VERSION 5.7 ;
  NOWIREEXTENSIONATPIN ON ;
  DIVIDERCHAR "/" ;
  BUSBITCHARS "[]" ;
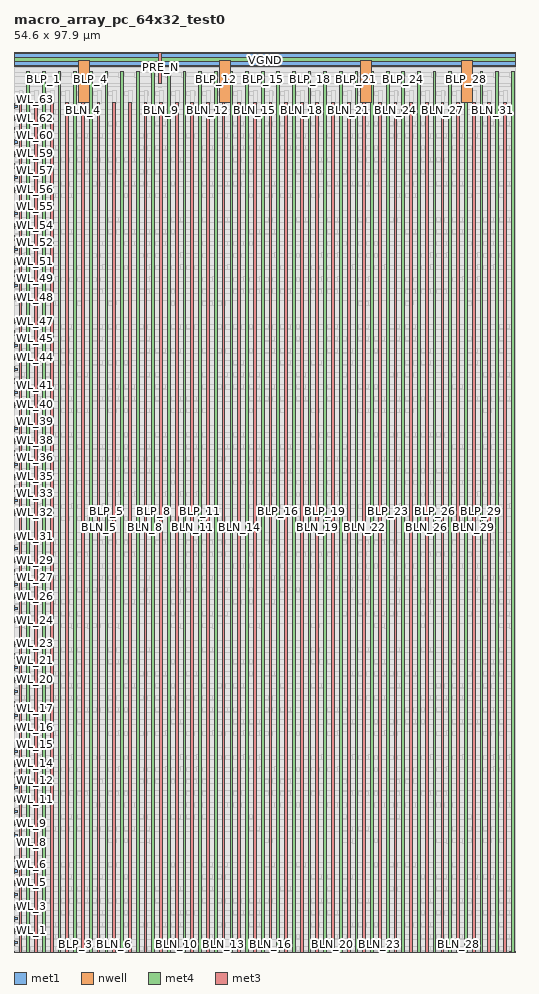
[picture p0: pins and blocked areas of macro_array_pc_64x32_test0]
MACRO macro_array_pc_64x32_test0
  CLASS BLOCK ;
  FOREIGN macro_array_pc_64x32_test0 ;
  ORIGIN 0.000 0.000 ;
  SIZE 54.600 BY 97.900 ;
  PIN VPWR
    USE POWER ;
    PORT
      LAYER met1 ;
        RECT 0.000 96.450 54.500 96.850 ;
    END
    PORT
      LAYER nwell ;
        RECT 7.050 92.400 8.250 96.980 ;
    END
    PORT
      LAYER nwell ;
        RECT 22.350 92.400 23.550 96.980 ;
    END
    PORT
      LAYER nwell ;
        RECT 37.650 92.400 38.850 96.980 ;
    END
    PORT
      LAYER nwell ;
        RECT 48.700 92.400 49.900 96.980 ;
    END
    PORT
      LAYER met4 ;
        RECT 0.000 96.350 54.500 97.650 ;
    END
  END VPWR
  PIN VGND
    USE GROUND ;
    PORT
      LAYER met1 ;
        RECT 0.000 97.300 54.500 97.700 ;
    END
  END VGND
  PIN PRE_N
    ANTENNAGATEAREA 9.599999 ;
    PORT
      LAYER met3 ;
        RECT 15.685 94.435 16.095 97.900 ;
    END
  END PRE_N
  PIN BLP_0
    ANTENNADIFFAREA 1.995200 ;
    PORT
      LAYER met4 ;
        RECT 1.400 0.000 1.700 95.800 ;
    END
  END BLP_0
  PIN BLN_0
    ANTENNADIFFAREA 3.456800 ;
    PORT
      LAYER met3 ;
        RECT 0.550 0.000 0.850 92.400 ;
    END
  END BLN_0
  PIN BLP_1
    ANTENNADIFFAREA 1.629800 ;
    PORT
      LAYER met4 ;
        RECT 3.100 0.000 3.400 95.800 ;
    END
  END BLP_1
  PIN BLN_1
    ANTENNADIFFAREA 2.969600 ;
    PORT
      LAYER met3 ;
        RECT 2.250 0.000 2.550 92.400 ;
    END
  END BLN_1
  PIN BLP_2
    ANTENNADIFFAREA 2.604200 ;
    PORT
      LAYER met4 ;
        RECT 4.800 0.000 5.100 95.800 ;
    END
  END BLP_2
  PIN BLN_2
    ANTENNADIFFAREA 1.995200 ;
    PORT
      LAYER met3 ;
        RECT 3.950 0.000 4.250 92.400 ;
    END
  END BLN_2
  PIN BLP_3
    ANTENNADIFFAREA 2.117000 ;
    PORT
      LAYER met4 ;
        RECT 6.500 0.000 6.800 95.800 ;
    END
  END BLP_3
  PIN BLN_3
    ANTENNADIFFAREA 2.726000 ;
    PORT
      LAYER met3 ;
        RECT 5.650 0.000 5.950 92.400 ;
    END
  END BLN_3
  PIN BLP_4
    ANTENNADIFFAREA 1.995200 ;
    PORT
      LAYER met4 ;
        RECT 8.200 0.000 8.500 95.800 ;
    END
  END BLP_4
  PIN BLN_4
    ANTENNADIFFAREA 2.969600 ;
    PORT
      LAYER met3 ;
        RECT 7.350 0.000 7.650 92.400 ;
    END
  END BLN_4
  PIN BLP_5
    ANTENNADIFFAREA 2.604200 ;
    PORT
      LAYER met4 ;
        RECT 9.900 0.000 10.200 95.800 ;
    END
  END BLP_5
  PIN BLN_5
    ANTENNADIFFAREA 1.873400 ;
    PORT
      LAYER met3 ;
        RECT 9.050 0.000 9.350 92.400 ;
    END
  END BLN_5
  PIN BLP_6
    ANTENNADIFFAREA 1.629800 ;
    PORT
      LAYER met4 ;
        RECT 11.600 0.000 11.900 95.800 ;
    END
  END BLP_6
  PIN BLN_6
    ANTENNADIFFAREA 2.360600 ;
    PORT
      LAYER met3 ;
        RECT 10.750 0.000 11.050 92.400 ;
    END
  END BLN_6
  PIN BLP_7
    ANTENNADIFFAREA 1.873400 ;
    PORT
      LAYER met4 ;
        RECT 13.300 0.000 13.600 95.800 ;
    END
  END BLP_7
  PIN BLN_7
    ANTENNADIFFAREA 2.726000 ;
    PORT
      LAYER met3 ;
        RECT 12.450 0.000 12.750 92.400 ;
    END
  END BLN_7
  PIN BLP_8
    ANTENNADIFFAREA 2.482400 ;
    PORT
      LAYER met4 ;
        RECT 15.000 0.000 15.300 95.800 ;
    END
  END BLP_8
  PIN BLN_8
    ANTENNADIFFAREA 2.360600 ;
    PORT
      LAYER met3 ;
        RECT 14.150 0.000 14.450 92.400 ;
    END
  END BLN_8
  PIN BLP_9
    ANTENNADIFFAREA 2.238800 ;
    PORT
      LAYER met4 ;
        RECT 16.700 0.000 17.000 95.800 ;
    END
  END BLP_9
  PIN BLN_9
    ANTENNADIFFAREA 1.751600 ;
    PORT
      LAYER met3 ;
        RECT 15.850 0.000 16.150 92.400 ;
    END
  END BLN_9
  PIN BLP_10
    ANTENNADIFFAREA 2.847800 ;
    PORT
      LAYER met4 ;
        RECT 18.400 0.000 18.700 95.800 ;
    END
  END BLP_10
  PIN BLN_10
    ANTENNADIFFAREA 2.117000 ;
    PORT
      LAYER met3 ;
        RECT 17.550 0.000 17.850 92.400 ;
    END
  END BLN_10
  PIN BLP_11
    ANTENNADIFFAREA 1.873400 ;
    PORT
      LAYER met4 ;
        RECT 20.100 0.000 20.400 95.800 ;
    END
  END BLP_11
  PIN BLN_11
    ANTENNADIFFAREA 1.629800 ;
    PORT
      LAYER met3 ;
        RECT 19.250 0.000 19.550 92.400 ;
    END
  END BLN_11
  PIN BLP_12
    ANTENNADIFFAREA 2.482400 ;
    PORT
      LAYER met4 ;
        RECT 21.800 0.000 22.100 95.800 ;
    END
  END BLP_12
  PIN BLN_12
    ANTENNADIFFAREA 3.091400 ;
    PORT
      LAYER met3 ;
        RECT 20.950 0.000 21.250 92.400 ;
    END
  END BLN_12
  PIN BLP_13
    ANTENNADIFFAREA 1.751600 ;
    PORT
      LAYER met4 ;
        RECT 23.500 0.000 23.800 95.800 ;
    END
  END BLP_13
  PIN BLN_13
    ANTENNADIFFAREA 1.995200 ;
    PORT
      LAYER met3 ;
        RECT 22.650 0.000 22.950 92.400 ;
    END
  END BLN_13
  PIN BLP_14
    ANTENNADIFFAREA 2.604200 ;
    PORT
      LAYER met4 ;
        RECT 25.200 0.000 25.500 95.800 ;
    END
  END BLP_14
  PIN BLN_14
    ANTENNADIFFAREA 1.751600 ;
    PORT
      LAYER met3 ;
        RECT 24.350 0.000 24.650 92.400 ;
    END
  END BLN_14
  PIN BLP_15
    ANTENNADIFFAREA 2.969600 ;
    PORT
      LAYER met4 ;
        RECT 26.900 0.000 27.200 95.800 ;
    END
  END BLP_15
  PIN BLN_15
    ANTENNADIFFAREA 1.995200 ;
    PORT
      LAYER met3 ;
        RECT 26.050 0.000 26.350 92.400 ;
    END
  END BLN_15
  PIN BLP_16
    ANTENNADIFFAREA 1.873400 ;
    PORT
      LAYER met4 ;
        RECT 28.600 0.000 28.900 95.800 ;
    END
  END BLP_16
  PIN BLN_16
    ANTENNADIFFAREA 2.482400 ;
    PORT
      LAYER met3 ;
        RECT 27.750 0.000 28.050 92.400 ;
    END
  END BLN_16
  PIN BLP_17
    ANTENNADIFFAREA 1.873400 ;
    PORT
      LAYER met4 ;
        RECT 30.300 0.000 30.600 95.800 ;
    END
  END BLP_17
  PIN BLN_17
    ANTENNADIFFAREA 1.873400 ;
    PORT
      LAYER met3 ;
        RECT 29.450 0.000 29.750 92.400 ;
    END
  END BLN_17
  PIN BLP_18
    ANTENNADIFFAREA 1.508000 ;
    PORT
      LAYER met4 ;
        RECT 32.000 0.000 32.300 95.800 ;
    END
  END BLP_18
  PIN BLN_18
    ANTENNADIFFAREA 1.873400 ;
    PORT
      LAYER met3 ;
        RECT 31.150 0.000 31.450 92.400 ;
    END
  END BLN_18
  PIN BLP_19
    ANTENNADIFFAREA 1.751600 ;
    PORT
      LAYER met4 ;
        RECT 33.700 0.000 34.000 95.800 ;
    END
  END BLP_19
  PIN BLN_19
    ANTENNADIFFAREA 2.117000 ;
    PORT
      LAYER met3 ;
        RECT 32.850 0.000 33.150 92.400 ;
    END
  END BLN_19
  PIN BLP_20
    ANTENNADIFFAREA 2.969600 ;
    PORT
      LAYER met4 ;
        RECT 35.400 0.000 35.700 95.800 ;
    END
  END BLP_20
  PIN BLN_20
    ANTENNADIFFAREA 1.873400 ;
    PORT
      LAYER met3 ;
        RECT 34.550 0.000 34.850 92.400 ;
    END
  END BLN_20
  PIN BLP_21
    ANTENNADIFFAREA 2.117000 ;
    PORT
      LAYER met4 ;
        RECT 37.100 0.000 37.400 95.800 ;
    END
  END BLP_21
  PIN BLN_21
    ANTENNADIFFAREA 2.847800 ;
    PORT
      LAYER met3 ;
        RECT 36.250 0.000 36.550 92.400 ;
    END
  END BLN_21
  PIN BLP_22
    ANTENNADIFFAREA 2.360600 ;
    PORT
      LAYER met4 ;
        RECT 38.800 0.000 39.100 95.800 ;
    END
  END BLP_22
  PIN BLN_22
    ANTENNADIFFAREA 1.873400 ;
    PORT
      LAYER met3 ;
        RECT 37.950 0.000 38.250 92.400 ;
    END
  END BLN_22
  PIN BLP_23
    ANTENNADIFFAREA 2.117000 ;
    PORT
      LAYER met4 ;
        RECT 40.500 0.000 40.800 95.800 ;
    END
  END BLP_23
  PIN BLN_23
    ANTENNADIFFAREA 2.360600 ;
    PORT
      LAYER met3 ;
        RECT 39.650 0.000 39.950 92.400 ;
    END
  END BLN_23
  PIN BLP_24
    ANTENNADIFFAREA 2.117000 ;
    PORT
      LAYER met4 ;
        RECT 42.200 0.000 42.500 95.800 ;
    END
  END BLP_24
  PIN BLN_24
    ANTENNADIFFAREA 2.238800 ;
    PORT
      LAYER met3 ;
        RECT 41.350 0.000 41.650 92.400 ;
    END
  END BLN_24
  PIN BLP_25
    ANTENNADIFFAREA 1.751600 ;
    PORT
      LAYER met4 ;
        RECT 43.900 0.000 44.200 95.800 ;
    END
  END BLP_25
  PIN BLN_25
    ANTENNADIFFAREA 2.482400 ;
    PORT
      LAYER met3 ;
        RECT 43.050 0.000 43.350 92.400 ;
    END
  END BLN_25
  PIN BLP_26
    ANTENNADIFFAREA 2.604200 ;
    PORT
      LAYER met4 ;
        RECT 45.600 0.000 45.900 95.800 ;
    END
  END BLP_26
  PIN BLN_26
    ANTENNADIFFAREA 2.117000 ;
    PORT
      LAYER met3 ;
        RECT 44.750 0.000 45.050 92.400 ;
    END
  END BLN_26
  PIN BLP_27
    ANTENNADIFFAREA 2.238800 ;
    PORT
      LAYER met4 ;
        RECT 47.300 0.000 47.600 95.800 ;
    END
  END BLP_27
  PIN BLN_27
    ANTENNADIFFAREA 1.508000 ;
    PORT
      LAYER met3 ;
        RECT 46.450 0.000 46.750 92.400 ;
    END
  END BLN_27
  PIN BLP_28
    ANTENNADIFFAREA 2.360600 ;
    PORT
      LAYER met4 ;
        RECT 49.000 0.000 49.300 95.800 ;
    END
  END BLP_28
  PIN BLN_28
    ANTENNADIFFAREA 2.117000 ;
    PORT
      LAYER met3 ;
        RECT 48.150 0.000 48.450 92.400 ;
    END
  END BLN_28
  PIN BLP_29
    ANTENNADIFFAREA 1.995200 ;
    PORT
      LAYER met4 ;
        RECT 50.700 0.000 51.000 95.800 ;
    END
  END BLP_29
  PIN BLN_29
    ANTENNADIFFAREA 2.117000 ;
    PORT
      LAYER met3 ;
        RECT 49.850 0.000 50.150 92.400 ;
    END
  END BLN_29
  PIN BLP_30
    ANTENNADIFFAREA 1.995200 ;
    PORT
      LAYER met4 ;
        RECT 52.400 0.000 52.700 95.800 ;
    END
  END BLP_30
  PIN BLN_30
    ANTENNADIFFAREA 1.995200 ;
    PORT
      LAYER met3 ;
        RECT 51.550 0.000 51.850 92.400 ;
    END
  END BLN_30
  PIN BLP_31
    ANTENNADIFFAREA 2.847800 ;
    PORT
      LAYER met4 ;
        RECT 54.100 0.000 54.400 95.800 ;
    END
  END BLP_31
  PIN BLN_31
    ANTENNADIFFAREA 2.117000 ;
    PORT
      LAYER met3 ;
        RECT 53.250 0.000 53.550 92.400 ;
    END
  END BLN_31
  PIN WL_0
    ANTENNAGATEAREA 2.284800 ;
    PORT
      LAYER met1 ;
        RECT 0.000 0.900 0.390 1.120 ;
    END
  END WL_0
  PIN WL_1
    ANTENNAGATEAREA 2.284800 ;
    PORT
      LAYER met1 ;
        RECT 0.000 2.200 0.390 2.420 ;
    END
  END WL_1
  PIN WL_2
    ANTENNAGATEAREA 2.284800 ;
    PORT
      LAYER met1 ;
        RECT 0.000 3.500 0.390 3.720 ;
    END
  END WL_2
  PIN WL_3
    ANTENNAGATEAREA 2.284800 ;
    PORT
      LAYER met1 ;
        RECT 0.000 4.800 0.390 5.020 ;
    END
  END WL_3
  PIN WL_4
    ANTENNAGATEAREA 2.284800 ;
    PORT
      LAYER met1 ;
        RECT 0.000 6.100 0.390 6.320 ;
    END
  END WL_4
  PIN WL_5
    ANTENNAGATEAREA 2.284800 ;
    PORT
      LAYER met1 ;
        RECT 0.000 7.400 0.390 7.620 ;
    END
  END WL_5
  PIN WL_6
    ANTENNAGATEAREA 2.284800 ;
    PORT
      LAYER met1 ;
        RECT 0.000 8.700 0.390 8.920 ;
    END
  END WL_6
  PIN WL_7
    ANTENNAGATEAREA 2.284800 ;
    PORT
      LAYER met1 ;
        RECT 0.000 10.000 0.390 10.220 ;
    END
  END WL_7
  PIN WL_8
    ANTENNAGATEAREA 2.284800 ;
    PORT
      LAYER met1 ;
        RECT 0.000 12.600 0.390 12.820 ;
    END
  END WL_8
  PIN WL_9
    ANTENNAGATEAREA 2.284800 ;
    PORT
      LAYER met1 ;
        RECT 0.000 13.900 0.390 14.120 ;
    END
  END WL_9
  PIN WL_10
    ANTENNAGATEAREA 2.284800 ;
    PORT
      LAYER met1 ;
        RECT 0.000 15.200 0.390 15.420 ;
    END
  END WL_10
  PIN WL_11
    ANTENNAGATEAREA 2.284800 ;
    PORT
      LAYER met1 ;
        RECT 0.000 16.500 0.390 16.720 ;
    END
  END WL_11
  PIN WL_12
    ANTENNAGATEAREA 2.284800 ;
    PORT
      LAYER met1 ;
        RECT 0.000 17.800 0.390 18.020 ;
    END
  END WL_12
  PIN WL_13
    ANTENNAGATEAREA 2.284800 ;
    PORT
      LAYER met1 ;
        RECT 0.000 19.100 0.390 19.320 ;
    END
  END WL_13
  PIN WL_14
    ANTENNAGATEAREA 2.284800 ;
    PORT
      LAYER met1 ;
        RECT 0.000 20.400 0.390 20.620 ;
    END
  END WL_14
  PIN WL_15
    ANTENNAGATEAREA 2.284800 ;
    PORT
      LAYER met1 ;
        RECT 0.000 21.700 0.390 21.920 ;
    END
  END WL_15
  PIN WL_16
    ANTENNAGATEAREA 2.284800 ;
    PORT
      LAYER met1 ;
        RECT 0.000 24.300 0.390 24.520 ;
    END
  END WL_16
  PIN WL_17
    ANTENNAGATEAREA 2.284800 ;
    PORT
      LAYER met1 ;
        RECT 0.000 25.600 0.390 25.820 ;
    END
  END WL_17
  PIN WL_18
    ANTENNAGATEAREA 2.284800 ;
    PORT
      LAYER met1 ;
        RECT 0.000 26.900 0.390 27.120 ;
    END
  END WL_18
  PIN WL_19
    ANTENNAGATEAREA 2.284800 ;
    PORT
      LAYER met1 ;
        RECT 0.000 28.200 0.390 28.420 ;
    END
  END WL_19
  PIN WL_20
    ANTENNAGATEAREA 2.284800 ;
    PORT
      LAYER met1 ;
        RECT 0.000 29.500 0.390 29.720 ;
    END
  END WL_20
  PIN WL_21
    ANTENNAGATEAREA 2.284800 ;
    PORT
      LAYER met1 ;
        RECT 0.000 30.800 0.390 31.020 ;
    END
  END WL_21
  PIN WL_22
    ANTENNAGATEAREA 2.284800 ;
    PORT
      LAYER met1 ;
        RECT 0.000 32.100 0.390 32.320 ;
    END
  END WL_22
  PIN WL_23
    ANTENNAGATEAREA 2.284800 ;
    PORT
      LAYER met1 ;
        RECT 0.000 33.400 0.390 33.620 ;
    END
  END WL_23
  PIN WL_24
    ANTENNAGATEAREA 2.284800 ;
    PORT
      LAYER met1 ;
        RECT 0.000 36.000 0.390 36.220 ;
    END
  END WL_24
  PIN WL_25
    ANTENNAGATEAREA 2.284800 ;
    PORT
      LAYER met1 ;
        RECT 0.000 37.300 0.390 37.520 ;
    END
  END WL_25
  PIN WL_26
    ANTENNAGATEAREA 2.284800 ;
    PORT
      LAYER met1 ;
        RECT 0.000 38.600 0.390 38.820 ;
    END
  END WL_26
  PIN WL_27
    ANTENNAGATEAREA 2.284800 ;
    PORT
      LAYER met1 ;
        RECT 0.000 39.900 0.390 40.120 ;
    END
  END WL_27
  PIN WL_28
    ANTENNAGATEAREA 2.284800 ;
    PORT
      LAYER met1 ;
        RECT 0.000 41.200 0.390 41.420 ;
    END
  END WL_28
  PIN WL_29
    ANTENNAGATEAREA 2.284800 ;
    PORT
      LAYER met1 ;
        RECT 0.000 42.500 0.390 42.720 ;
    END
  END WL_29
  PIN WL_30
    ANTENNAGATEAREA 2.284800 ;
    PORT
      LAYER met1 ;
        RECT 0.000 43.800 0.390 44.020 ;
    END
  END WL_30
  PIN WL_31
    ANTENNAGATEAREA 2.284800 ;
    PORT
      LAYER met1 ;
        RECT 0.000 45.100 0.390 45.320 ;
    END
  END WL_31
  PIN WL_32
    ANTENNAGATEAREA 2.284800 ;
    PORT
      LAYER met1 ;
        RECT 0.000 47.700 0.390 47.920 ;
    END
  END WL_32
  PIN WL_33
    ANTENNAGATEAREA 2.284800 ;
    PORT
      LAYER met1 ;
        RECT 0.000 49.000 0.390 49.220 ;
    END
  END WL_33
  PIN WL_34
    ANTENNAGATEAREA 2.284800 ;
    PORT
      LAYER met1 ;
        RECT 0.000 50.300 0.390 50.520 ;
    END
  END WL_34
  PIN WL_35
    ANTENNAGATEAREA 2.284800 ;
    PORT
      LAYER met1 ;
        RECT 0.000 51.600 0.390 51.820 ;
    END
  END WL_35
  PIN WL_36
    ANTENNAGATEAREA 2.284800 ;
    PORT
      LAYER met1 ;
        RECT 0.000 52.900 0.390 53.120 ;
    END
  END WL_36
  PIN WL_37
    ANTENNAGATEAREA 2.284800 ;
    PORT
      LAYER met1 ;
        RECT 0.000 54.200 0.390 54.420 ;
    END
  END WL_37
  PIN WL_38
    ANTENNAGATEAREA 2.284800 ;
    PORT
      LAYER met1 ;
        RECT 0.000 55.500 0.390 55.720 ;
    END
  END WL_38
  PIN WL_39
    ANTENNAGATEAREA 2.284800 ;
    PORT
      LAYER met1 ;
        RECT 0.000 56.800 0.390 57.020 ;
    END
  END WL_39
  PIN WL_40
    ANTENNAGATEAREA 2.284800 ;
    PORT
      LAYER met1 ;
        RECT 0.000 59.400 0.390 59.620 ;
    END
  END WL_40
  PIN WL_41
    ANTENNAGATEAREA 2.284800 ;
    PORT
      LAYER met1 ;
        RECT 0.000 60.700 0.390 60.920 ;
    END
  END WL_41
  PIN WL_42
    ANTENNAGATEAREA 2.284800 ;
    PORT
      LAYER met1 ;
        RECT 0.000 62.000 0.390 62.220 ;
    END
  END WL_42
  PIN WL_43
    ANTENNAGATEAREA 2.284800 ;
    PORT
      LAYER met1 ;
        RECT 0.000 63.300 0.390 63.520 ;
    END
  END WL_43
  PIN WL_44
    ANTENNAGATEAREA 2.284800 ;
    PORT
      LAYER met1 ;
        RECT 0.000 64.600 0.390 64.820 ;
    END
  END WL_44
  PIN WL_45
    ANTENNAGATEAREA 2.284800 ;
    PORT
      LAYER met1 ;
        RECT 0.000 65.900 0.390 66.120 ;
    END
  END WL_45
  PIN WL_46
    ANTENNAGATEAREA 2.284800 ;
    PORT
      LAYER met1 ;
        RECT 0.000 67.200 0.390 67.420 ;
    END
  END WL_46
  PIN WL_47
    ANTENNAGATEAREA 2.284800 ;
    PORT
      LAYER met1 ;
        RECT 0.000 68.500 0.390 68.720 ;
    END
  END WL_47
  PIN WL_48
    ANTENNAGATEAREA 2.284800 ;
    PORT
      LAYER met1 ;
        RECT 0.000 71.100 0.390 71.320 ;
    END
  END WL_48
  PIN WL_49
    ANTENNAGATEAREA 2.284800 ;
    PORT
      LAYER met1 ;
        RECT 0.000 72.400 0.390 72.620 ;
    END
  END WL_49
  PIN WL_50
    ANTENNAGATEAREA 2.284800 ;
    PORT
      LAYER met1 ;
        RECT 0.000 73.700 0.390 73.920 ;
    END
  END WL_50
  PIN WL_51
    ANTENNAGATEAREA 2.284800 ;
    PORT
      LAYER met1 ;
        RECT 0.000 75.000 0.390 75.220 ;
    END
  END WL_51
  PIN WL_52
    ANTENNAGATEAREA 2.284800 ;
    PORT
      LAYER met1 ;
        RECT 0.000 76.300 0.390 76.520 ;
    END
  END WL_52
  PIN WL_53
    ANTENNAGATEAREA 2.284800 ;
    PORT
      LAYER met1 ;
        RECT 0.000 77.600 0.390 77.820 ;
    END
  END WL_53
  PIN WL_54
    ANTENNAGATEAREA 2.284800 ;
    PORT
      LAYER met1 ;
        RECT 0.000 78.900 0.390 79.120 ;
    END
  END WL_54
  PIN WL_55
    ANTENNAGATEAREA 2.284800 ;
    PORT
      LAYER met1 ;
        RECT 0.000 80.200 0.390 80.420 ;
    END
  END WL_55
  PIN WL_56
    ANTENNAGATEAREA 2.284800 ;
    PORT
      LAYER met1 ;
        RECT 0.000 82.800 0.390 83.020 ;
    END
  END WL_56
  PIN WL_57
    ANTENNAGATEAREA 2.284800 ;
    PORT
      LAYER met1 ;
        RECT 0.000 84.100 0.390 84.320 ;
    END
  END WL_57
  PIN WL_58
    ANTENNAGATEAREA 2.284800 ;
    PORT
      LAYER met1 ;
        RECT 0.000 85.400 0.390 85.620 ;
    END
  END WL_58
  PIN WL_59
    ANTENNAGATEAREA 2.284800 ;
    PORT
      LAYER met1 ;
        RECT 0.000 86.700 0.390 86.920 ;
    END
  END WL_59
  PIN WL_60
    ANTENNAGATEAREA 2.284800 ;
    PORT
      LAYER met1 ;
        RECT 0.000 88.000 0.390 88.220 ;
    END
  END WL_60
  PIN WL_61
    ANTENNAGATEAREA 2.284800 ;
    PORT
      LAYER met1 ;
        RECT 0.000 89.300 0.390 89.520 ;
    END
  END WL_61
  PIN WL_62
    ANTENNAGATEAREA 2.284800 ;
    PORT
      LAYER met1 ;
        RECT 0.000 90.600 0.390 90.820 ;
    END
  END WL_62
  PIN WL_63
    ANTENNAGATEAREA 2.284800 ;
    PORT
      LAYER met1 ;
        RECT 0.000 91.900 0.390 92.120 ;
    END
  END WL_63
  OBS
      LAYER li1 ;
        RECT 0.140 0.040 53.830 97.650 ;
      LAYER met1 ;
        RECT 0.080 92.400 54.600 96.170 ;
        RECT 0.670 91.620 54.600 92.400 ;
        RECT 0.080 91.100 54.600 91.620 ;
        RECT 0.670 90.320 54.600 91.100 ;
        RECT 0.080 89.800 54.600 90.320 ;
        RECT 0.670 89.020 54.600 89.800 ;
        RECT 0.080 88.500 54.600 89.020 ;
        RECT 0.670 87.720 54.600 88.500 ;
        RECT 0.080 87.200 54.600 87.720 ;
        RECT 0.670 86.420 54.600 87.200 ;
        RECT 0.080 85.900 54.600 86.420 ;
        RECT 0.670 85.120 54.600 85.900 ;
        RECT 0.080 84.600 54.600 85.120 ;
        RECT 0.670 83.820 54.600 84.600 ;
        RECT 0.080 83.300 54.600 83.820 ;
        RECT 0.670 82.520 54.600 83.300 ;
        RECT 0.080 80.700 54.600 82.520 ;
        RECT 0.670 79.920 54.600 80.700 ;
        RECT 0.080 79.400 54.600 79.920 ;
        RECT 0.670 78.620 54.600 79.400 ;
        RECT 0.080 78.100 54.600 78.620 ;
        RECT 0.670 77.320 54.600 78.100 ;
        RECT 0.080 76.800 54.600 77.320 ;
        RECT 0.670 76.020 54.600 76.800 ;
        RECT 0.080 75.500 54.600 76.020 ;
        RECT 0.670 74.720 54.600 75.500 ;
        RECT 0.080 74.200 54.600 74.720 ;
        RECT 0.670 73.420 54.600 74.200 ;
        RECT 0.080 72.900 54.600 73.420 ;
        RECT 0.670 72.120 54.600 72.900 ;
        RECT 0.080 71.600 54.600 72.120 ;
        RECT 0.670 70.820 54.600 71.600 ;
        RECT 0.080 69.000 54.600 70.820 ;
        RECT 0.670 68.220 54.600 69.000 ;
        RECT 0.080 67.700 54.600 68.220 ;
        RECT 0.670 66.920 54.600 67.700 ;
        RECT 0.080 66.400 54.600 66.920 ;
        RECT 0.670 65.620 54.600 66.400 ;
        RECT 0.080 65.100 54.600 65.620 ;
        RECT 0.670 64.320 54.600 65.100 ;
        RECT 0.080 63.800 54.600 64.320 ;
        RECT 0.670 63.020 54.600 63.800 ;
        RECT 0.080 62.500 54.600 63.020 ;
        RECT 0.670 61.720 54.600 62.500 ;
        RECT 0.080 61.200 54.600 61.720 ;
        RECT 0.670 60.420 54.600 61.200 ;
        RECT 0.080 59.900 54.600 60.420 ;
        RECT 0.670 59.120 54.600 59.900 ;
        RECT 0.080 57.300 54.600 59.120 ;
        RECT 0.670 56.520 54.600 57.300 ;
        RECT 0.080 56.000 54.600 56.520 ;
        RECT 0.670 55.220 54.600 56.000 ;
        RECT 0.080 54.700 54.600 55.220 ;
        RECT 0.670 53.920 54.600 54.700 ;
        RECT 0.080 53.400 54.600 53.920 ;
        RECT 0.670 52.620 54.600 53.400 ;
        RECT 0.080 52.100 54.600 52.620 ;
        RECT 0.670 51.320 54.600 52.100 ;
        RECT 0.080 50.800 54.600 51.320 ;
        RECT 0.670 50.020 54.600 50.800 ;
        RECT 0.080 49.500 54.600 50.020 ;
        RECT 0.670 48.720 54.600 49.500 ;
        RECT 0.080 48.200 54.600 48.720 ;
        RECT 0.670 47.420 54.600 48.200 ;
        RECT 0.080 45.600 54.600 47.420 ;
        RECT 0.670 44.820 54.600 45.600 ;
        RECT 0.080 44.300 54.600 44.820 ;
        RECT 0.670 43.520 54.600 44.300 ;
        RECT 0.080 43.000 54.600 43.520 ;
        RECT 0.670 42.220 54.600 43.000 ;
        RECT 0.080 41.700 54.600 42.220 ;
        RECT 0.670 40.920 54.600 41.700 ;
        RECT 0.080 40.400 54.600 40.920 ;
        RECT 0.670 39.620 54.600 40.400 ;
        RECT 0.080 39.100 54.600 39.620 ;
        RECT 0.670 38.320 54.600 39.100 ;
        RECT 0.080 37.800 54.600 38.320 ;
        RECT 0.670 37.020 54.600 37.800 ;
        RECT 0.080 36.500 54.600 37.020 ;
        RECT 0.670 35.720 54.600 36.500 ;
        RECT 0.080 33.900 54.600 35.720 ;
        RECT 0.670 33.120 54.600 33.900 ;
        RECT 0.080 32.600 54.600 33.120 ;
        RECT 0.670 31.820 54.600 32.600 ;
        RECT 0.080 31.300 54.600 31.820 ;
        RECT 0.670 30.520 54.600 31.300 ;
        RECT 0.080 30.000 54.600 30.520 ;
        RECT 0.670 29.220 54.600 30.000 ;
        RECT 0.080 28.700 54.600 29.220 ;
        RECT 0.670 27.920 54.600 28.700 ;
        RECT 0.080 27.400 54.600 27.920 ;
        RECT 0.670 26.620 54.600 27.400 ;
        RECT 0.080 26.100 54.600 26.620 ;
        RECT 0.670 25.320 54.600 26.100 ;
        RECT 0.080 24.800 54.600 25.320 ;
        RECT 0.670 24.020 54.600 24.800 ;
        RECT 0.080 22.200 54.600 24.020 ;
        RECT 0.670 21.420 54.600 22.200 ;
        RECT 0.080 20.900 54.600 21.420 ;
        RECT 0.670 20.120 54.600 20.900 ;
        RECT 0.080 19.600 54.600 20.120 ;
        RECT 0.670 18.820 54.600 19.600 ;
        RECT 0.080 18.300 54.600 18.820 ;
        RECT 0.670 17.520 54.600 18.300 ;
        RECT 0.080 17.000 54.600 17.520 ;
        RECT 0.670 16.220 54.600 17.000 ;
        RECT 0.080 15.700 54.600 16.220 ;
        RECT 0.670 14.920 54.600 15.700 ;
        RECT 0.080 14.400 54.600 14.920 ;
        RECT 0.670 13.620 54.600 14.400 ;
        RECT 0.080 13.100 54.600 13.620 ;
        RECT 0.670 12.320 54.600 13.100 ;
        RECT 0.080 10.500 54.600 12.320 ;
        RECT 0.670 9.720 54.600 10.500 ;
        RECT 0.080 9.200 54.600 9.720 ;
        RECT 0.670 8.420 54.600 9.200 ;
        RECT 0.080 7.900 54.600 8.420 ;
        RECT 0.670 7.120 54.600 7.900 ;
        RECT 0.080 6.600 54.600 7.120 ;
        RECT 0.670 5.820 54.600 6.600 ;
        RECT 0.080 5.300 54.600 5.820 ;
        RECT 0.670 4.520 54.600 5.300 ;
        RECT 0.080 4.000 54.600 4.520 ;
        RECT 0.670 3.220 54.600 4.000 ;
        RECT 0.080 2.700 54.600 3.220 ;
        RECT 0.670 1.920 54.600 2.700 ;
        RECT 0.080 1.400 54.600 1.920 ;
        RECT 0.670 0.620 54.600 1.400 ;
        RECT 0.080 0.170 54.600 0.620 ;
      LAYER met2 ;
        RECT 1.780 48.270 3.245 48.710 ;
        RECT 5.180 48.270 6.645 48.710 ;
        RECT 6.880 48.270 7.680 48.710 ;
        RECT 8.580 48.270 10.045 48.710 ;
        RECT 15.380 48.270 16.180 48.710 ;
        RECT 20.480 48.270 21.280 48.710 ;
        RECT 25.580 48.270 27.045 48.710 ;
        RECT 28.980 48.270 29.780 48.710 ;
        RECT 34.080 48.270 34.880 48.710 ;
        RECT 37.480 48.270 38.945 48.710 ;
        RECT 39.180 48.270 40.645 48.710 ;
        RECT 40.880 48.270 42.345 48.710 ;
        RECT 42.580 48.270 43.380 48.710 ;
        RECT 45.980 48.270 46.780 48.710 ;
        RECT 47.680 48.270 48.480 48.710 ;
        RECT 49.380 48.270 50.180 48.710 ;
        RECT 52.780 48.270 54.245 48.710 ;
        RECT 0.100 94.110 54.040 94.490 ;
        RECT 42.580 72.970 43.380 73.410 ;
        RECT 47.680 72.970 49.145 73.410 ;
        RECT 49.380 72.970 50.845 73.410 ;
        RECT 44.280 74.270 45.745 74.710 ;
        RECT 49.380 74.270 50.845 74.710 ;
        RECT 51.080 74.270 52.545 74.710 ;
        RECT 44.280 75.570 45.745 76.010 ;
        RECT 45.980 75.570 47.445 76.010 ;
        RECT 49.380 75.570 50.845 76.010 ;
        RECT 51.080 75.570 51.880 76.010 ;
        RECT 52.780 75.570 53.580 76.010 ;
        RECT 45.980 76.870 47.445 77.310 ;
        RECT 49.380 76.870 50.180 77.310 ;
        RECT 51.080 76.870 52.545 77.310 ;
        RECT 42.580 78.170 44.045 78.610 ;
        RECT 45.980 78.170 47.445 78.610 ;
        RECT 47.680 78.170 49.145 78.610 ;
        RECT 51.080 78.170 52.545 78.610 ;
        RECT 40.880 79.470 41.680 79.910 ;
        RECT 45.980 79.470 46.780 79.910 ;
        RECT 47.680 79.470 49.145 79.910 ;
        RECT 51.080 79.470 52.545 79.910 ;
        RECT 52.780 79.470 54.245 79.910 ;
        RECT 40.880 82.070 42.345 82.510 ;
        RECT 42.580 82.070 44.045 82.510 ;
        RECT 49.380 82.070 50.180 82.510 ;
        RECT 52.780 82.070 53.580 82.510 ;
        RECT 42.580 83.370 43.380 83.810 ;
        RECT 45.980 83.370 47.445 83.810 ;
        RECT 47.680 83.370 49.145 83.810 ;
        RECT 52.780 83.370 54.245 83.810 ;
        RECT 42.580 84.670 44.045 85.110 ;
        RECT 44.280 84.670 45.080 85.110 ;
        RECT 47.680 84.670 48.480 85.110 ;
        RECT 44.280 85.970 45.745 86.410 ;
        RECT 45.980 85.970 46.780 86.410 ;
        RECT 44.280 87.270 45.080 87.710 ;
        RECT 47.680 87.270 48.480 87.710 ;
        RECT 49.380 87.270 50.180 87.710 ;
        RECT 52.780 87.270 54.245 87.710 ;
        RECT 40.880 88.570 41.680 89.010 ;
        RECT 42.580 88.570 43.380 89.010 ;
        RECT 44.280 88.570 45.745 89.010 ;
        RECT 45.980 88.570 47.445 89.010 ;
        RECT 47.680 88.570 49.145 89.010 ;
        RECT 49.380 88.570 50.845 89.010 ;
        RECT 40.880 89.870 41.680 90.310 ;
        RECT 42.580 89.870 44.045 90.310 ;
        RECT 44.280 89.870 45.080 90.310 ;
        RECT 51.080 89.870 52.545 90.310 ;
        RECT 52.780 89.870 54.245 90.310 ;
        RECT 40.880 91.170 42.345 91.610 ;
        RECT 44.280 91.170 45.080 91.610 ;
        RECT 45.980 91.170 46.780 91.610 ;
        RECT 51.080 91.170 51.880 91.610 ;
        RECT 40.900 93.160 41.790 93.630 ;
        RECT 42.600 93.160 43.490 93.630 ;
        RECT 44.300 93.160 45.190 93.630 ;
        RECT 46.000 93.160 46.890 93.630 ;
        RECT 47.700 93.160 48.590 93.630 ;
        RECT 49.400 93.160 50.290 93.630 ;
        RECT 51.100 93.160 51.990 93.630 ;
        RECT 52.800 93.160 53.690 93.630 ;
        RECT 40.900 95.210 42.435 95.680 ;
        RECT 42.600 95.210 44.135 95.680 ;
        RECT 44.300 95.210 45.835 95.680 ;
        RECT 46.000 95.210 47.535 95.680 ;
        RECT 47.700 95.210 49.235 95.680 ;
        RECT 49.400 95.210 50.935 95.680 ;
        RECT 51.100 95.210 52.635 95.680 ;
        RECT 52.800 95.210 54.335 95.680 ;
        RECT 32.380 85.970 33.845 86.410 ;
        RECT 34.080 85.970 34.880 86.410 ;
        RECT 37.480 85.970 38.280 86.410 ;
        RECT 39.180 85.970 40.645 86.410 ;
        RECT 27.280 78.170 28.745 78.610 ;
        RECT 34.080 78.170 35.545 78.610 ;
        RECT 28.980 87.270 30.445 87.710 ;
        RECT 30.680 87.270 32.145 87.710 ;
        RECT 37.480 87.270 38.280 87.710 ;
        RECT 39.180 87.270 39.980 87.710 ;
        RECT 37.480 72.970 38.945 73.410 ;
        RECT 27.280 72.970 28.080 73.410 ;
        RECT 27.280 75.570 28.745 76.010 ;
        RECT 30.680 75.570 31.480 76.010 ;
        RECT 28.980 88.570 29.780 89.010 ;
        RECT 30.680 88.570 32.145 89.010 ;
        RECT 34.080 88.570 34.880 89.010 ;
        RECT 35.780 88.570 37.245 89.010 ;
        RECT 37.480 88.570 38.280 89.010 ;
        RECT 27.280 79.470 28.080 79.910 ;
        RECT 30.680 79.470 32.145 79.910 ;
        RECT 34.080 79.470 35.545 79.910 ;
        RECT 37.480 79.470 38.280 79.910 ;
        RECT 32.380 75.570 33.845 76.010 ;
        RECT 34.080 75.570 35.545 76.010 ;
        RECT 27.280 89.870 28.080 90.310 ;
        RECT 28.980 89.870 29.780 90.310 ;
        RECT 32.380 89.870 33.180 90.310 ;
        RECT 37.480 89.870 38.945 90.310 ;
        RECT 39.180 89.870 39.980 90.310 ;
        RECT 37.480 75.570 38.280 76.010 ;
        RECT 39.180 75.570 39.980 76.010 ;
        RECT 30.680 72.970 31.480 73.410 ;
        RECT 27.280 82.070 28.080 82.510 ;
        RECT 28.980 82.070 30.445 82.510 ;
        RECT 27.280 91.170 28.080 91.610 ;
        RECT 28.980 91.170 29.780 91.610 ;
        RECT 30.680 91.170 31.480 91.610 ;
        RECT 32.380 91.170 33.845 91.610 ;
        RECT 34.080 91.170 35.545 91.610 ;
        RECT 35.780 91.170 36.580 91.610 ;
        RECT 32.380 82.070 33.180 82.510 ;
        RECT 32.380 72.970 33.845 73.410 ;
        RECT 28.980 74.270 29.780 74.710 ;
        RECT 32.380 74.270 33.180 74.710 ;
        RECT 27.300 93.160 28.190 93.630 ;
        RECT 29.000 93.160 29.890 93.630 ;
        RECT 30.700 93.160 31.590 93.630 ;
        RECT 32.400 93.160 33.290 93.630 ;
        RECT 34.100 93.160 34.990 93.630 ;
        RECT 35.800 93.160 36.690 93.630 ;
        RECT 37.500 93.160 38.390 93.630 ;
        RECT 39.200 93.160 40.090 93.630 ;
        RECT 34.080 74.270 34.880 74.710 ;
        RECT 27.280 83.370 28.745 83.810 ;
        RECT 34.080 83.370 35.545 83.810 ;
        RECT 35.780 83.370 37.245 83.810 ;
        RECT 37.480 83.370 38.945 83.810 ;
        RECT 34.080 76.870 35.545 77.310 ;
        RECT 35.780 76.870 36.580 77.310 ;
        RECT 37.480 76.870 38.280 77.310 ;
        RECT 27.300 95.210 28.835 95.680 ;
        RECT 29.000 95.210 30.535 95.680 ;
        RECT 30.700 95.210 32.235 95.680 ;
        RECT 32.400 95.210 33.935 95.680 ;
        RECT 34.100 95.210 35.635 95.680 ;
        RECT 35.800 95.210 37.335 95.680 ;
        RECT 37.500 95.210 39.035 95.680 ;
        RECT 39.200 95.210 40.735 95.680 ;
        RECT 39.180 76.870 39.980 77.310 ;
        RECT 30.680 84.670 32.145 85.110 ;
        RECT 32.380 84.670 33.845 85.110 ;
        RECT 35.780 84.670 36.580 85.110 ;
        RECT 39.180 84.670 39.980 85.110 ;
        RECT 35.780 74.270 37.245 74.710 ;
        RECT 39.180 74.270 40.645 74.710 ;
        RECT 34.080 72.970 35.545 73.410 ;
        RECT 30.680 59.970 32.145 60.410 ;
        RECT 34.080 59.970 34.880 60.410 ;
        RECT 39.180 59.970 40.645 60.410 ;
        RECT 27.280 61.270 28.745 61.710 ;
        RECT 30.680 61.270 32.145 61.710 ;
        RECT 34.080 61.270 34.880 61.710 ;
        RECT 35.780 61.270 36.580 61.710 ;
        RECT 37.480 61.270 38.945 61.710 ;
        RECT 39.180 61.270 39.980 61.710 ;
        RECT 30.680 62.570 32.145 63.010 ;
        RECT 35.780 62.570 36.580 63.010 ;
        RECT 28.980 63.870 30.445 64.310 ;
        RECT 32.380 63.870 33.845 64.310 ;
        RECT 35.780 63.870 37.245 64.310 ;
        RECT 27.280 65.170 28.745 65.610 ;
        RECT 28.980 65.170 30.445 65.610 ;
        RECT 34.080 65.170 35.545 65.610 ;
        RECT 35.780 65.170 37.245 65.610 ;
        RECT 39.180 65.170 39.980 65.610 ;
        RECT 27.280 66.470 28.745 66.910 ;
        RECT 30.680 66.470 31.480 66.910 ;
        RECT 34.080 66.470 35.545 66.910 ;
        RECT 35.780 66.470 36.580 66.910 ;
        RECT 37.480 66.470 38.945 66.910 ;
        RECT 39.180 66.470 40.645 66.910 ;
        RECT 27.280 67.770 28.080 68.210 ;
        RECT 28.980 67.770 30.445 68.210 ;
        RECT 30.680 67.770 31.480 68.210 ;
        RECT 34.080 67.770 35.545 68.210 ;
        RECT 37.480 67.770 38.945 68.210 ;
        RECT 37.480 70.370 38.945 70.810 ;
        RECT 27.280 71.670 28.080 72.110 ;
        RECT 28.980 71.670 30.445 72.110 ;
        RECT 32.380 71.670 33.845 72.110 ;
        RECT 34.080 71.670 35.545 72.110 ;
        RECT 30.680 49.570 31.480 50.010 ;
        RECT 34.080 49.570 35.545 50.010 ;
        RECT 35.780 49.570 36.580 50.010 ;
        RECT 30.680 50.870 32.145 51.310 ;
        RECT 34.080 50.870 34.880 51.310 ;
        RECT 27.280 52.170 28.745 52.610 ;
        RECT 28.980 52.170 30.445 52.610 ;
        RECT 35.780 52.170 36.580 52.610 ;
        RECT 27.280 53.470 28.080 53.910 ;
        RECT 28.980 53.470 29.780 53.910 ;
        RECT 27.280 49.570 28.080 50.010 ;
        RECT 34.080 53.470 35.545 53.910 ;
        RECT 35.780 53.470 36.580 53.910 ;
        RECT 39.180 53.470 40.645 53.910 ;
        RECT 28.980 54.770 30.445 55.210 ;
        RECT 32.380 54.770 33.180 55.210 ;
        RECT 35.780 54.770 36.580 55.210 ;
        RECT 32.380 56.070 33.180 56.510 ;
        RECT 34.080 56.070 34.880 56.510 ;
        RECT 35.780 56.070 36.580 56.510 ;
        RECT 39.180 56.070 39.980 56.510 ;
        RECT 28.980 58.670 29.780 59.110 ;
        RECT 32.380 58.670 33.180 59.110 ;
        RECT 37.480 58.670 38.945 59.110 ;
        RECT 39.180 58.670 40.645 59.110 ;
        RECT 27.280 59.970 28.080 60.410 ;
        RECT 28.980 59.970 29.780 60.410 ;
        RECT 47.680 50.870 49.145 51.310 ;
        RECT 40.880 53.470 42.345 53.910 ;
        RECT 51.080 50.870 51.880 51.310 ;
        RECT 40.880 59.970 42.345 60.410 ;
        RECT 42.580 59.970 43.380 60.410 ;
        RECT 40.880 67.770 42.345 68.210 ;
        RECT 42.580 67.770 44.045 68.210 ;
        RECT 52.780 67.770 54.245 68.210 ;
        RECT 44.280 59.970 45.080 60.410 ;
        RECT 42.580 70.370 43.380 70.810 ;
        RECT 49.380 70.370 50.180 70.810 ;
        RECT 49.380 59.970 50.845 60.410 ;
        RECT 51.080 59.970 51.880 60.410 ;
        RECT 52.780 59.970 54.245 60.410 ;
        RECT 52.780 50.870 54.245 51.310 ;
        RECT 42.580 71.670 44.045 72.110 ;
        RECT 44.280 71.670 45.745 72.110 ;
        RECT 45.980 71.670 47.445 72.110 ;
        RECT 49.380 71.670 50.180 72.110 ;
        RECT 49.380 49.570 50.845 50.010 ;
        RECT 47.680 54.770 49.145 55.210 ;
        RECT 51.080 54.770 51.880 55.210 ;
        RECT 51.080 49.570 51.880 50.010 ;
        RECT 52.780 49.570 53.580 50.010 ;
        RECT 47.680 61.270 49.145 61.710 ;
        RECT 42.580 52.170 43.380 52.610 ;
        RECT 44.280 52.170 45.080 52.610 ;
        RECT 40.880 62.570 41.680 63.010 ;
        RECT 42.580 62.570 43.380 63.010 ;
        RECT 47.680 62.570 48.480 63.010 ;
        RECT 51.080 62.570 51.880 63.010 ;
        RECT 52.780 62.570 54.245 63.010 ;
        RECT 40.880 56.070 41.680 56.510 ;
        RECT 42.580 56.070 44.045 56.510 ;
        RECT 44.280 56.070 45.745 56.510 ;
        RECT 42.580 63.870 43.380 64.310 ;
        RECT 44.280 63.870 45.745 64.310 ;
        RECT 49.380 63.870 50.845 64.310 ;
        RECT 45.980 56.070 46.780 56.510 ;
        RECT 51.080 56.070 51.880 56.510 ;
        RECT 45.980 52.170 47.445 52.610 ;
        RECT 52.780 52.170 53.580 52.610 ;
        RECT 44.280 49.570 45.080 50.010 ;
        RECT 44.280 65.170 45.745 65.610 ;
        RECT 49.380 65.170 50.845 65.610 ;
        RECT 52.780 65.170 53.580 65.610 ;
        RECT 47.680 49.570 48.480 50.010 ;
        RECT 40.880 58.670 42.345 59.110 ;
        RECT 42.580 58.670 43.380 59.110 ;
        RECT 51.080 58.670 51.880 59.110 ;
        RECT 42.580 50.870 43.380 51.310 ;
        RECT 44.280 50.870 45.745 51.310 ;
        RECT 40.880 66.470 42.345 66.910 ;
        RECT 42.580 66.470 44.045 66.910 ;
        RECT 49.380 66.470 50.180 66.910 ;
        RECT 52.780 66.470 53.580 66.910 ;
        RECT 13.680 74.270 15.145 74.710 ;
        RECT 15.380 74.270 16.180 74.710 ;
        RECT 17.080 74.270 18.545 74.710 ;
        RECT 18.780 74.270 19.580 74.710 ;
        RECT 22.180 74.270 23.645 74.710 ;
        RECT 13.680 75.570 14.480 76.010 ;
        RECT 15.380 75.570 16.180 76.010 ;
        RECT 17.080 75.570 18.545 76.010 ;
        RECT 20.480 75.570 21.280 76.010 ;
        RECT 23.880 75.570 24.680 76.010 ;
        RECT 13.680 76.870 15.145 77.310 ;
        RECT 15.380 76.870 16.845 77.310 ;
        RECT 20.480 76.870 21.280 77.310 ;
        RECT 22.180 76.870 23.645 77.310 ;
        RECT 23.880 76.870 25.345 77.310 ;
        RECT 25.580 76.870 26.380 77.310 ;
        RECT 13.680 78.170 15.145 78.610 ;
        RECT 15.380 78.170 16.845 78.610 ;
        RECT 17.080 78.170 17.880 78.610 ;
        RECT 25.580 78.170 27.045 78.610 ;
        RECT 17.080 79.470 18.545 79.910 ;
        RECT 20.480 79.470 21.280 79.910 ;
        RECT 22.180 79.470 23.645 79.910 ;
        RECT 13.680 82.070 15.145 82.510 ;
        RECT 15.380 82.070 16.845 82.510 ;
        RECT 20.480 82.070 21.945 82.510 ;
        RECT 25.580 82.070 26.380 82.510 ;
        RECT 13.680 83.370 14.480 83.810 ;
        RECT 17.080 83.370 17.880 83.810 ;
        RECT 20.480 83.370 21.945 83.810 ;
        RECT 22.180 83.370 23.645 83.810 ;
        RECT 23.880 83.370 24.680 83.810 ;
        RECT 13.680 84.670 14.480 85.110 ;
        RECT 15.380 84.670 16.180 85.110 ;
        RECT 23.880 84.670 25.345 85.110 ;
        RECT 25.580 84.670 26.380 85.110 ;
        RECT 13.680 85.970 15.145 86.410 ;
        RECT 17.080 85.970 18.545 86.410 ;
        RECT 20.480 85.970 21.280 86.410 ;
        RECT 23.880 85.970 24.680 86.410 ;
        RECT 13.680 87.270 14.480 87.710 ;
        RECT 15.380 87.270 16.845 87.710 ;
        RECT 20.480 87.270 21.945 87.710 ;
        RECT 23.880 87.270 25.345 87.710 ;
        RECT 25.580 87.270 27.045 87.710 ;
        RECT 13.680 88.570 14.480 89.010 ;
        RECT 18.780 88.570 19.580 89.010 ;
        RECT 22.180 88.570 23.645 89.010 ;
        RECT 23.880 88.570 25.345 89.010 ;
        RECT 25.580 88.570 27.045 89.010 ;
        RECT 15.380 89.870 16.845 90.310 ;
        RECT 23.880 89.870 25.345 90.310 ;
        RECT 13.680 91.170 14.480 91.610 ;
        RECT 15.380 91.170 16.845 91.610 ;
        RECT 25.580 91.170 26.380 91.610 ;
        RECT 13.700 93.160 14.590 93.630 ;
        RECT 15.400 93.160 16.290 93.630 ;
        RECT 17.100 93.160 17.990 93.630 ;
        RECT 18.800 93.160 19.690 93.630 ;
        RECT 20.500 93.160 21.390 93.630 ;
        RECT 22.200 93.160 23.090 93.630 ;
        RECT 23.900 93.160 24.790 93.630 ;
        RECT 25.600 93.160 26.490 93.630 ;
        RECT 13.700 95.210 15.235 95.680 ;
        RECT 15.400 95.210 16.935 95.680 ;
        RECT 17.100 95.210 18.635 95.680 ;
        RECT 18.800 95.210 20.335 95.680 ;
        RECT 20.500 95.210 22.035 95.680 ;
        RECT 22.200 95.210 23.735 95.680 ;
        RECT 23.900 95.210 25.435 95.680 ;
        RECT 25.600 95.210 27.135 95.680 ;
        RECT 13.680 72.970 15.145 73.410 ;
        RECT 20.480 72.970 21.945 73.410 ;
        RECT 23.880 72.970 25.345 73.410 ;
        RECT 25.580 72.970 27.045 73.410 ;
        RECT 5.180 82.070 6.645 82.510 ;
        RECT 11.980 82.070 12.780 82.510 ;
        RECT 6.880 74.270 7.680 74.710 ;
        RECT 8.580 74.270 10.045 74.710 ;
        RECT 0.080 75.570 1.545 76.010 ;
        RECT 0.080 88.570 0.880 89.010 ;
        RECT 1.780 88.570 3.245 89.010 ;
        RECT 6.880 88.570 8.345 89.010 ;
        RECT 8.580 88.570 10.045 89.010 ;
        RECT 0.080 78.170 0.880 78.610 ;
        RECT 0.080 83.370 1.545 83.810 ;
        RECT 3.480 83.370 4.280 83.810 ;
        RECT 5.180 83.370 5.980 83.810 ;
        RECT 8.580 83.370 9.380 83.810 ;
        RECT 3.480 89.870 4.280 90.310 ;
        RECT 10.280 89.870 11.080 90.310 ;
        RECT 11.980 83.370 13.445 83.810 ;
        RECT 5.180 78.170 6.645 78.610 ;
        RECT 0.080 91.170 1.545 91.610 ;
        RECT 1.780 91.170 2.580 91.610 ;
        RECT 3.480 91.170 4.945 91.610 ;
        RECT 6.880 91.170 8.345 91.610 ;
        RECT 10.280 78.170 11.080 78.610 ;
        RECT 11.980 78.170 13.445 78.610 ;
        RECT 1.780 75.570 2.580 76.010 ;
        RECT 0.100 93.160 0.990 93.630 ;
        RECT 1.800 93.160 2.690 93.630 ;
        RECT 3.500 93.160 4.390 93.630 ;
        RECT 5.200 93.160 6.090 93.630 ;
        RECT 6.900 93.160 7.790 93.630 ;
        RECT 8.600 93.160 9.490 93.630 ;
        RECT 10.300 93.160 11.190 93.630 ;
        RECT 12.000 93.160 12.890 93.630 ;
        RECT 0.080 76.870 1.545 77.310 ;
        RECT 6.880 84.670 8.345 85.110 ;
        RECT 10.280 84.670 11.080 85.110 ;
        RECT 8.580 76.870 10.045 77.310 ;
        RECT 11.980 76.870 13.445 77.310 ;
        RECT 3.480 79.470 4.280 79.910 ;
        RECT 10.280 79.470 11.745 79.910 ;
        RECT 0.080 85.970 0.880 86.410 ;
        RECT 1.780 72.970 3.245 73.410 ;
        RECT 3.480 72.970 4.945 73.410 ;
        RECT 5.180 72.970 5.980 73.410 ;
        RECT 0.100 95.210 1.635 95.680 ;
        RECT 1.800 95.210 3.335 95.680 ;
        RECT 3.500 95.210 5.035 95.680 ;
        RECT 5.200 95.210 6.735 95.680 ;
        RECT 6.900 95.210 8.435 95.680 ;
        RECT 8.600 95.210 10.135 95.680 ;
        RECT 10.300 95.210 11.835 95.680 ;
        RECT 12.000 95.210 13.535 95.680 ;
        RECT 5.180 85.970 5.980 86.410 ;
        RECT 6.880 85.970 8.345 86.410 ;
        RECT 8.580 85.970 9.380 86.410 ;
        RECT 10.280 85.970 11.080 86.410 ;
        RECT 11.980 85.970 13.445 86.410 ;
        RECT 3.480 75.570 4.280 76.010 ;
        RECT 8.580 75.570 9.380 76.010 ;
        RECT 11.980 74.270 12.780 74.710 ;
        RECT 6.880 72.970 7.680 73.410 ;
        RECT 8.580 72.970 9.380 73.410 ;
        RECT 3.480 82.070 4.945 82.510 ;
        RECT 1.780 87.270 2.580 87.710 ;
        RECT 3.480 87.270 4.945 87.710 ;
        RECT 6.880 87.270 7.680 87.710 ;
        RECT 0.080 74.270 0.880 74.710 ;
        RECT 1.780 74.270 2.580 74.710 ;
        RECT 7.940 96.390 8.460 96.910 ;
        RECT 0.080 52.170 0.880 52.610 ;
        RECT 10.280 61.270 11.745 61.710 ;
        RECT 11.980 61.270 13.445 61.710 ;
        RECT 6.880 70.370 7.680 70.810 ;
        RECT 10.280 70.370 11.080 70.810 ;
        RECT 8.580 59.970 10.045 60.410 ;
        RECT 10.280 59.970 11.745 60.410 ;
        RECT 11.980 59.970 13.445 60.410 ;
        RECT 0.080 71.670 1.545 72.110 ;
        RECT 3.480 71.670 4.280 72.110 ;
        RECT 5.180 66.470 5.980 66.910 ;
        RECT 8.580 66.470 10.045 66.910 ;
        RECT 5.180 58.670 6.645 59.110 ;
        RECT 6.880 58.670 8.345 59.110 ;
        RECT 10.280 58.670 11.080 59.110 ;
        RECT 3.480 61.270 4.945 61.710 ;
        RECT 11.980 54.770 12.780 55.210 ;
        RECT 1.780 63.870 3.245 64.310 ;
        RECT 3.480 63.870 4.280 64.310 ;
        RECT 5.180 63.870 5.980 64.310 ;
        RECT 8.580 63.870 10.045 64.310 ;
        RECT 10.280 63.870 11.080 64.310 ;
        RECT 6.880 50.870 7.680 51.310 ;
        RECT 11.980 58.670 12.780 59.110 ;
        RECT 8.580 53.470 10.045 53.910 ;
        RECT 0.080 67.770 0.880 68.210 ;
        RECT 8.580 71.670 10.045 72.110 ;
        RECT 10.280 49.570 11.745 50.010 ;
        RECT 11.980 49.570 13.445 50.010 ;
        RECT 11.980 63.870 12.780 64.310 ;
        RECT 11.980 56.070 12.780 56.510 ;
        RECT 0.080 62.570 1.545 63.010 ;
        RECT 3.480 62.570 4.280 63.010 ;
        RECT 6.880 62.570 8.345 63.010 ;
        RECT 5.180 61.270 5.980 61.710 ;
        RECT 6.880 49.570 7.680 50.010 ;
        RECT 3.480 53.470 4.945 53.910 ;
        RECT 5.180 53.470 5.980 53.910 ;
        RECT 1.780 67.770 2.580 68.210 ;
        RECT 5.180 67.770 6.645 68.210 ;
        RECT 8.580 67.770 10.045 68.210 ;
        RECT 10.280 67.770 11.080 68.210 ;
        RECT 10.280 53.470 11.745 53.910 ;
        RECT 0.080 66.470 0.880 66.910 ;
        RECT 11.980 52.170 13.445 52.610 ;
        RECT 3.480 56.070 4.945 56.510 ;
        RECT 5.180 56.070 6.645 56.510 ;
        RECT 11.980 53.470 12.780 53.910 ;
        RECT 1.780 59.970 3.245 60.410 ;
        RECT 5.180 59.970 6.645 60.410 ;
        RECT 0.080 70.370 0.880 70.810 ;
        RECT 1.780 70.370 2.580 70.810 ;
        RECT 3.480 70.370 4.945 70.810 ;
        RECT 1.780 49.570 2.580 50.010 ;
        RECT 0.080 54.770 0.880 55.210 ;
        RECT 1.780 54.770 2.580 55.210 ;
        RECT 6.880 54.770 7.680 55.210 ;
        RECT 8.580 54.770 10.045 55.210 ;
        RECT 1.780 61.270 3.245 61.710 ;
        RECT 0.080 65.170 0.880 65.610 ;
        RECT 1.780 65.170 2.580 65.610 ;
        RECT 5.180 65.170 5.980 65.610 ;
        RECT 18.780 58.670 20.245 59.110 ;
        RECT 20.480 58.670 21.280 59.110 ;
        RECT 25.580 58.670 26.380 59.110 ;
        RECT 25.580 54.770 27.045 55.210 ;
        RECT 13.680 52.170 15.145 52.610 ;
        RECT 17.080 52.170 17.880 52.610 ;
        RECT 25.580 52.170 27.045 52.610 ;
        RECT 20.480 50.870 21.280 51.310 ;
        RECT 23.880 50.870 24.680 51.310 ;
        RECT 25.580 50.870 26.380 51.310 ;
        RECT 22.180 61.270 22.980 61.710 ;
        RECT 18.780 56.070 20.245 56.510 ;
        RECT 20.480 56.070 21.280 56.510 ;
        RECT 23.880 56.070 25.345 56.510 ;
        RECT 13.680 62.570 15.145 63.010 ;
        RECT 15.380 62.570 16.180 63.010 ;
        RECT 20.480 62.570 21.280 63.010 ;
        RECT 22.180 62.570 23.645 63.010 ;
        RECT 13.680 67.770 14.480 68.210 ;
        RECT 13.680 71.670 15.145 72.110 ;
        RECT 17.080 71.670 17.880 72.110 ;
        RECT 20.480 71.670 21.280 72.110 ;
        RECT 23.880 71.670 25.345 72.110 ;
        RECT 25.580 71.670 27.045 72.110 ;
        RECT 15.380 59.970 16.180 60.410 ;
        RECT 17.080 59.970 18.545 60.410 ;
        RECT 18.780 59.970 20.245 60.410 ;
        RECT 25.580 59.970 27.045 60.410 ;
        RECT 25.580 53.470 27.045 53.910 ;
        RECT 17.080 67.770 18.545 68.210 ;
        RECT 18.780 67.770 19.580 68.210 ;
        RECT 15.380 49.570 16.845 50.010 ;
        RECT 22.180 67.770 22.980 68.210 ;
        RECT 23.880 67.770 24.680 68.210 ;
        RECT 25.580 67.770 26.380 68.210 ;
        RECT 23.880 62.570 25.345 63.010 ;
        RECT 25.580 62.570 27.045 63.010 ;
        RECT 23.880 61.270 25.345 61.710 ;
        RECT 15.380 61.270 16.845 61.710 ;
        RECT 25.580 61.270 27.045 61.710 ;
        RECT 20.480 61.270 21.280 61.710 ;
        RECT 13.680 53.470 14.480 53.910 ;
        RECT 15.380 53.470 16.845 53.910 ;
        RECT 18.780 53.470 19.580 53.910 ;
        RECT 22.180 53.470 22.980 53.910 ;
        RECT 13.680 54.770 15.145 55.210 ;
        RECT 18.780 54.770 20.245 55.210 ;
        RECT 13.680 66.470 15.145 66.910 ;
        RECT 23.880 63.870 25.345 64.310 ;
        RECT 20.480 54.770 21.280 55.210 ;
        RECT 13.680 65.170 15.145 65.610 ;
        RECT 15.380 65.170 16.845 65.610 ;
        RECT 17.080 65.170 18.545 65.610 ;
        RECT 20.480 65.170 21.280 65.610 ;
        RECT 22.180 65.170 22.980 65.610 ;
        RECT 25.580 65.170 26.380 65.610 ;
        RECT 15.380 56.070 16.845 56.510 ;
        RECT 17.080 49.570 18.545 50.010 ;
        RECT 18.780 49.570 20.245 50.010 ;
        RECT 20.480 49.570 21.280 50.010 ;
        RECT 17.080 50.870 17.880 51.310 ;
        RECT 22.180 54.770 23.645 55.210 ;
        RECT 17.080 70.370 17.880 70.810 ;
        RECT 20.480 70.370 21.945 70.810 ;
        RECT 22.180 70.370 22.980 70.810 ;
        RECT 23.880 54.770 25.345 55.210 ;
        RECT 13.680 58.670 15.145 59.110 ;
        RECT 17.080 58.670 18.545 59.110 ;
        RECT 17.080 24.870 18.545 25.310 ;
        RECT 23.880 24.870 25.345 25.310 ;
        RECT 25.580 24.870 27.045 25.310 ;
        RECT 15.380 26.170 16.180 26.610 ;
        RECT 17.080 26.170 17.880 26.610 ;
        RECT 20.480 26.170 21.945 26.610 ;
        RECT 22.180 26.170 23.645 26.610 ;
        RECT 23.880 26.170 24.680 26.610 ;
        RECT 13.680 27.470 14.480 27.910 ;
        RECT 15.380 27.470 16.180 27.910 ;
        RECT 17.080 27.470 17.880 27.910 ;
        RECT 18.780 27.470 19.580 27.910 ;
        RECT 20.480 27.470 21.945 27.910 ;
        RECT 15.380 28.770 16.180 29.210 ;
        RECT 17.080 28.770 17.880 29.210 ;
        RECT 20.480 28.770 21.280 29.210 ;
        RECT 22.180 28.770 22.980 29.210 ;
        RECT 23.880 28.770 25.345 29.210 ;
        RECT 13.680 30.070 14.480 30.510 ;
        RECT 15.380 30.070 16.845 30.510 ;
        RECT 18.780 30.070 20.245 30.510 ;
        RECT 25.580 30.070 26.380 30.510 ;
        RECT 17.080 31.370 17.880 31.810 ;
        RECT 23.880 31.370 25.345 31.810 ;
        RECT 25.580 31.370 26.380 31.810 ;
        RECT 13.680 32.670 15.145 33.110 ;
        RECT 20.480 32.670 21.945 33.110 ;
        RECT 17.080 35.270 18.545 35.710 ;
        RECT 20.480 35.270 21.945 35.710 ;
        RECT 25.580 35.270 27.045 35.710 ;
        RECT 17.080 36.570 17.880 37.010 ;
        RECT 20.480 36.570 21.945 37.010 ;
        RECT 22.180 36.570 23.645 37.010 ;
        RECT 13.680 37.870 15.145 38.310 ;
        RECT 17.080 37.870 18.545 38.310 ;
        RECT 23.880 37.870 24.680 38.310 ;
        RECT 25.580 37.870 26.380 38.310 ;
        RECT 13.680 39.170 14.480 39.610 ;
        RECT 17.080 39.170 18.545 39.610 ;
        RECT 18.780 39.170 20.245 39.610 ;
        RECT 20.480 39.170 21.280 39.610 ;
        RECT 22.180 39.170 23.645 39.610 ;
        RECT 25.580 39.170 26.380 39.610 ;
        RECT 13.680 40.470 15.145 40.910 ;
        RECT 17.080 40.470 18.545 40.910 ;
        RECT 20.480 40.470 21.945 40.910 ;
        RECT 18.780 41.770 20.245 42.210 ;
        RECT 20.480 41.770 21.280 42.210 ;
        RECT 23.880 41.770 25.345 42.210 ;
        RECT 25.580 41.770 27.045 42.210 ;
        RECT 18.780 43.070 20.245 43.510 ;
        RECT 20.480 43.070 21.945 43.510 ;
        RECT 22.180 43.070 22.980 43.510 ;
        RECT 25.580 43.070 26.380 43.510 ;
        RECT 15.380 44.370 16.845 44.810 ;
        RECT 18.780 44.370 20.245 44.810 ;
        RECT 20.480 44.370 21.945 44.810 ;
        RECT 22.180 44.370 22.980 44.810 ;
        RECT 17.080 46.970 17.880 47.410 ;
        RECT 22.180 46.970 22.980 47.410 ;
        RECT 5.180 35.270 6.645 35.710 ;
        RECT 6.880 35.270 8.345 35.710 ;
        RECT 8.580 35.270 9.380 35.710 ;
        RECT 10.280 35.270 11.745 35.710 ;
        RECT 0.080 28.770 0.880 29.210 ;
        RECT 3.480 28.770 4.280 29.210 ;
        RECT 5.180 28.770 6.645 29.210 ;
        RECT 0.080 36.570 0.880 37.010 ;
        RECT 1.780 36.570 2.580 37.010 ;
        RECT 5.180 36.570 5.980 37.010 ;
        RECT 6.880 36.570 7.680 37.010 ;
        RECT 6.880 28.770 7.680 29.210 ;
        RECT 11.980 28.770 13.445 29.210 ;
        RECT 0.080 26.170 1.545 26.610 ;
        RECT 0.080 37.870 1.545 38.310 ;
        RECT 3.480 37.870 4.945 38.310 ;
        RECT 5.180 37.870 5.980 38.310 ;
        RECT 11.980 37.870 13.445 38.310 ;
        RECT 3.480 26.170 4.280 26.610 ;
        RECT 6.880 26.170 8.345 26.610 ;
        RECT 0.080 27.470 1.545 27.910 ;
        RECT 1.780 27.470 2.580 27.910 ;
        RECT 0.080 39.170 0.880 39.610 ;
        RECT 1.780 39.170 2.580 39.610 ;
        RECT 3.480 39.170 4.280 39.610 ;
        RECT 6.880 39.170 8.345 39.610 ;
        RECT 8.580 39.170 9.380 39.610 ;
        RECT 0.080 30.070 0.880 30.510 ;
        RECT 1.780 30.070 2.580 30.510 ;
        RECT 3.480 30.070 4.945 30.510 ;
        RECT 5.180 30.070 5.980 30.510 ;
        RECT 6.880 30.070 7.680 30.510 ;
        RECT 3.480 27.470 4.945 27.910 ;
        RECT 1.780 40.470 2.580 40.910 ;
        RECT 3.480 40.470 4.945 40.910 ;
        RECT 5.180 40.470 5.980 40.910 ;
        RECT 8.580 40.470 10.045 40.910 ;
        RECT 10.280 40.470 11.080 40.910 ;
        RECT 5.180 27.470 6.645 27.910 ;
        RECT 6.880 27.470 7.680 27.910 ;
        RECT 10.280 27.470 11.080 27.910 ;
        RECT 0.080 41.770 1.545 42.210 ;
        RECT 1.780 41.770 2.580 42.210 ;
        RECT 8.580 41.770 10.045 42.210 ;
        RECT 3.480 31.370 4.280 31.810 ;
        RECT 6.880 31.370 7.680 31.810 ;
        RECT 10.280 31.370 11.745 31.810 ;
        RECT 11.980 31.370 12.780 31.810 ;
        RECT 3.480 43.070 4.945 43.510 ;
        RECT 6.880 43.070 8.345 43.510 ;
        RECT 11.980 43.070 13.445 43.510 ;
        RECT 8.580 26.170 9.380 26.610 ;
        RECT 10.280 26.170 11.745 26.610 ;
        RECT 11.980 26.170 12.780 26.610 ;
        RECT 5.180 32.670 6.645 33.110 ;
        RECT 0.080 44.370 0.880 44.810 ;
        RECT 1.780 44.370 3.245 44.810 ;
        RECT 3.480 44.370 4.945 44.810 ;
        RECT 8.580 44.370 10.045 44.810 ;
        RECT 10.280 44.370 11.080 44.810 ;
        RECT 11.980 44.370 12.780 44.810 ;
        RECT 6.880 32.670 7.680 33.110 ;
        RECT 10.280 32.670 11.080 33.110 ;
        RECT 6.880 24.870 7.680 25.310 ;
        RECT 1.780 24.870 3.245 25.310 ;
        RECT 5.180 46.970 5.980 47.410 ;
        RECT 6.880 46.970 8.345 47.410 ;
        RECT 8.580 46.970 10.045 47.410 ;
        RECT 10.280 46.970 11.080 47.410 ;
        RECT 11.980 46.970 12.780 47.410 ;
        RECT 0.080 35.270 1.545 35.710 ;
        RECT 1.780 35.270 2.580 35.710 ;
        RECT 0.080 15.770 0.880 16.210 ;
        RECT 3.480 15.770 4.280 16.210 ;
        RECT 8.580 15.770 9.380 16.210 ;
        RECT 11.980 15.770 13.445 16.210 ;
        RECT 0.080 17.070 0.880 17.510 ;
        RECT 5.180 17.070 5.980 17.510 ;
        RECT 6.880 17.070 8.345 17.510 ;
        RECT 10.280 17.070 11.745 17.510 ;
        RECT 11.980 17.070 12.780 17.510 ;
        RECT 0.080 18.370 0.880 18.810 ;
        RECT 1.780 18.370 2.580 18.810 ;
        RECT 8.580 18.370 10.045 18.810 ;
        RECT 0.080 19.670 0.880 20.110 ;
        RECT 1.780 19.670 2.580 20.110 ;
        RECT 3.480 19.670 4.280 20.110 ;
        RECT 5.180 19.670 5.980 20.110 ;
        RECT 6.880 19.670 7.680 20.110 ;
        RECT 10.280 19.670 11.745 20.110 ;
        RECT 0.080 20.970 0.880 21.410 ;
        RECT 1.780 20.970 3.245 21.410 ;
        RECT 5.180 20.970 6.645 21.410 ;
        RECT 8.580 20.970 9.380 21.410 ;
        RECT 11.980 20.970 12.780 21.410 ;
        RECT 1.780 23.570 3.245 24.010 ;
        RECT 3.480 23.570 4.945 24.010 ;
        RECT 6.880 23.570 7.680 24.010 ;
        RECT 10.280 23.570 11.745 24.010 ;
        RECT 11.980 23.570 12.780 24.010 ;
        RECT 0.080 0.170 0.880 0.610 ;
        RECT 1.780 0.170 3.245 0.610 ;
        RECT 3.480 0.170 4.945 0.610 ;
        RECT 6.880 0.170 7.680 0.610 ;
        RECT 11.980 0.170 12.780 0.610 ;
        RECT 0.080 1.470 1.545 1.910 ;
        RECT 1.780 1.470 2.580 1.910 ;
        RECT 3.480 1.470 4.945 1.910 ;
        RECT 5.180 1.470 5.980 1.910 ;
        RECT 6.880 1.470 7.680 1.910 ;
        RECT 8.580 1.470 9.380 1.910 ;
        RECT 0.080 2.770 0.880 3.210 ;
        RECT 1.780 2.770 2.580 3.210 ;
        RECT 3.480 2.770 4.945 3.210 ;
        RECT 6.880 2.770 7.680 3.210 ;
        RECT 8.580 2.770 10.045 3.210 ;
        RECT 11.980 2.770 12.780 3.210 ;
        RECT 1.780 4.070 2.580 4.510 ;
        RECT 5.180 4.070 5.980 4.510 ;
        RECT 8.580 4.070 10.045 4.510 ;
        RECT 11.980 4.070 12.780 4.510 ;
        RECT 0.080 5.370 0.880 5.810 ;
        RECT 3.480 5.370 4.280 5.810 ;
        RECT 5.180 5.370 5.980 5.810 ;
        RECT 6.880 5.370 8.345 5.810 ;
        RECT 8.580 5.370 9.380 5.810 ;
        RECT 10.280 5.370 11.080 5.810 ;
        RECT 11.980 5.370 12.780 5.810 ;
        RECT 0.080 6.670 1.545 7.110 ;
        RECT 5.180 6.670 6.645 7.110 ;
        RECT 6.880 6.670 8.345 7.110 ;
        RECT 8.580 6.670 9.380 7.110 ;
        RECT 5.180 7.970 6.645 8.410 ;
        RECT 8.580 7.970 10.045 8.410 ;
        RECT 11.980 7.970 12.780 8.410 ;
        RECT 0.080 9.270 0.880 9.710 ;
        RECT 5.180 9.270 5.980 9.710 ;
        RECT 10.280 9.270 11.080 9.710 ;
        RECT 0.080 11.870 0.880 12.310 ;
        RECT 1.780 11.870 2.580 12.310 ;
        RECT 10.280 11.870 11.080 12.310 ;
        RECT 11.980 11.870 12.780 12.310 ;
        RECT 0.080 13.170 1.545 13.610 ;
        RECT 3.480 13.170 4.945 13.610 ;
        RECT 5.180 13.170 5.980 13.610 ;
        RECT 6.880 13.170 7.680 13.610 ;
        RECT 8.580 13.170 9.380 13.610 ;
        RECT 10.280 13.170 11.080 13.610 ;
        RECT 11.980 13.170 13.445 13.610 ;
        RECT 0.080 14.470 0.880 14.910 ;
        RECT 5.180 14.470 6.645 14.910 ;
        RECT 6.880 14.470 7.680 14.910 ;
        RECT 23.880 23.570 25.345 24.010 ;
        RECT 25.580 23.570 27.045 24.010 ;
        RECT 17.080 0.170 18.545 0.610 ;
        RECT 18.780 0.170 19.580 0.610 ;
        RECT 17.080 1.470 17.880 1.910 ;
        RECT 13.680 14.470 14.480 14.910 ;
        RECT 17.080 14.470 18.545 14.910 ;
        RECT 18.780 14.470 19.580 14.910 ;
        RECT 20.480 14.470 21.280 14.910 ;
        RECT 25.580 14.470 26.380 14.910 ;
        RECT 15.380 6.670 16.180 7.110 ;
        RECT 17.080 6.670 18.545 7.110 ;
        RECT 20.480 6.670 21.945 7.110 ;
        RECT 17.080 4.070 18.545 4.510 ;
        RECT 18.780 15.770 19.580 16.210 ;
        RECT 20.480 15.770 21.280 16.210 ;
        RECT 22.180 15.770 23.645 16.210 ;
        RECT 23.880 15.770 24.680 16.210 ;
        RECT 18.780 4.070 19.580 4.510 ;
        RECT 23.880 4.070 25.345 4.510 ;
        RECT 20.480 7.970 21.945 8.410 ;
        RECT 22.180 7.970 22.980 8.410 ;
        RECT 25.580 4.070 27.045 4.510 ;
        RECT 18.780 17.070 19.580 17.510 ;
        RECT 20.480 17.070 21.280 17.510 ;
        RECT 23.880 17.070 24.680 17.510 ;
        RECT 20.480 1.470 21.945 1.910 ;
        RECT 23.880 1.470 24.680 1.910 ;
        RECT 17.080 9.270 17.880 9.710 ;
        RECT 13.680 18.370 14.480 18.810 ;
        RECT 15.380 18.370 16.180 18.810 ;
        RECT 17.080 18.370 17.880 18.810 ;
        RECT 18.780 18.370 20.245 18.810 ;
        RECT 20.480 18.370 21.280 18.810 ;
        RECT 20.480 9.270 21.945 9.710 ;
        RECT 22.180 9.270 23.645 9.710 ;
        RECT 13.680 2.770 14.480 3.210 ;
        RECT 15.380 2.770 16.845 3.210 ;
        RECT 17.080 2.770 18.545 3.210 ;
        RECT 22.180 2.770 22.980 3.210 ;
        RECT 13.680 19.670 14.480 20.110 ;
        RECT 15.380 19.670 16.845 20.110 ;
        RECT 17.080 19.670 18.545 20.110 ;
        RECT 18.780 19.670 20.245 20.110 ;
        RECT 20.480 19.670 21.280 20.110 ;
        RECT 23.880 19.670 24.680 20.110 ;
        RECT 25.580 19.670 27.045 20.110 ;
        RECT 13.680 11.870 15.145 12.310 ;
        RECT 25.580 2.770 27.045 3.210 ;
        RECT 15.380 5.370 16.180 5.810 ;
        RECT 20.480 5.370 21.280 5.810 ;
        RECT 22.180 5.370 22.980 5.810 ;
        RECT 17.080 20.970 18.545 21.410 ;
        RECT 18.780 20.970 20.245 21.410 ;
        RECT 22.180 20.970 22.980 21.410 ;
        RECT 23.880 20.970 25.345 21.410 ;
        RECT 25.580 20.970 27.045 21.410 ;
        RECT 23.880 5.370 24.680 5.810 ;
        RECT 25.580 5.370 27.045 5.810 ;
        RECT 13.680 0.170 14.480 0.610 ;
        RECT 13.680 13.170 15.145 13.610 ;
        RECT 25.580 13.170 27.045 13.610 ;
        RECT 13.680 23.570 14.480 24.010 ;
        RECT 15.380 23.570 16.845 24.010 ;
        RECT 18.780 23.570 19.580 24.010 ;
        RECT 20.480 23.570 21.945 24.010 ;
        RECT 22.180 23.570 22.980 24.010 ;
        RECT 49.380 30.070 50.180 30.510 ;
        RECT 51.080 30.070 52.545 30.510 ;
        RECT 52.780 30.070 53.580 30.510 ;
        RECT 47.680 31.370 48.480 31.810 ;
        RECT 51.080 31.370 52.545 31.810 ;
        RECT 52.780 31.370 53.580 31.810 ;
        RECT 40.880 32.670 42.345 33.110 ;
        RECT 44.280 32.670 45.745 33.110 ;
        RECT 52.780 32.670 53.580 33.110 ;
        RECT 44.280 35.270 45.080 35.710 ;
        RECT 52.780 35.270 54.245 35.710 ;
        RECT 40.880 36.570 41.680 37.010 ;
        RECT 44.280 36.570 45.080 37.010 ;
        RECT 49.380 36.570 50.180 37.010 ;
        RECT 52.780 36.570 54.245 37.010 ;
        RECT 40.880 37.870 42.345 38.310 ;
        RECT 44.280 37.870 45.745 38.310 ;
        RECT 51.080 37.870 52.545 38.310 ;
        RECT 52.780 37.870 54.245 38.310 ;
        RECT 40.880 39.170 42.345 39.610 ;
        RECT 44.280 39.170 45.080 39.610 ;
        RECT 49.380 39.170 50.845 39.610 ;
        RECT 52.780 39.170 53.580 39.610 ;
        RECT 40.880 40.470 41.680 40.910 ;
        RECT 42.580 40.470 43.380 40.910 ;
        RECT 45.980 40.470 47.445 40.910 ;
        RECT 49.380 40.470 50.845 40.910 ;
        RECT 51.080 40.470 52.545 40.910 ;
        RECT 52.780 40.470 54.245 40.910 ;
        RECT 42.580 41.770 43.380 42.210 ;
        RECT 47.680 41.770 49.145 42.210 ;
        RECT 49.380 41.770 50.845 42.210 ;
        RECT 40.880 43.070 41.680 43.510 ;
        RECT 44.280 43.070 45.745 43.510 ;
        RECT 45.980 43.070 46.780 43.510 ;
        RECT 47.680 43.070 48.480 43.510 ;
        RECT 49.380 43.070 50.180 43.510 ;
        RECT 52.780 43.070 54.245 43.510 ;
        RECT 40.880 44.370 41.680 44.810 ;
        RECT 47.680 44.370 48.480 44.810 ;
        RECT 51.080 44.370 52.545 44.810 ;
        RECT 42.580 46.970 43.380 47.410 ;
        RECT 44.280 46.970 45.080 47.410 ;
        RECT 47.680 46.970 49.145 47.410 ;
        RECT 49.380 46.970 50.845 47.410 ;
        RECT 40.880 24.870 41.680 25.310 ;
        RECT 42.580 24.870 44.045 25.310 ;
        RECT 44.280 24.870 45.080 25.310 ;
        RECT 47.680 24.870 49.145 25.310 ;
        RECT 49.380 24.870 50.845 25.310 ;
        RECT 52.780 24.870 53.580 25.310 ;
        RECT 42.580 26.170 43.380 26.610 ;
        RECT 44.280 26.170 45.080 26.610 ;
        RECT 45.980 26.170 47.445 26.610 ;
        RECT 51.080 26.170 52.545 26.610 ;
        RECT 44.280 27.470 45.745 27.910 ;
        RECT 45.980 27.470 47.445 27.910 ;
        RECT 47.680 27.470 49.145 27.910 ;
        RECT 40.880 28.770 42.345 29.210 ;
        RECT 45.980 28.770 46.780 29.210 ;
        RECT 47.680 28.770 49.145 29.210 ;
        RECT 51.080 28.770 51.880 29.210 ;
        RECT 40.880 30.070 41.680 30.510 ;
        RECT 42.580 30.070 44.045 30.510 ;
        RECT 47.680 30.070 48.480 30.510 ;
        RECT 32.380 31.370 33.180 31.810 ;
        RECT 34.080 31.370 34.880 31.810 ;
        RECT 27.280 44.370 28.080 44.810 ;
        RECT 35.780 44.370 36.580 44.810 ;
        RECT 37.480 44.370 38.945 44.810 ;
        RECT 39.180 44.370 40.645 44.810 ;
        RECT 27.280 40.470 28.745 40.910 ;
        RECT 28.980 40.470 30.445 40.910 ;
        RECT 34.080 40.470 35.545 40.910 ;
        RECT 34.080 24.870 34.880 25.310 ;
        RECT 35.780 24.870 37.245 25.310 ;
        RECT 39.180 24.870 39.980 25.310 ;
        RECT 30.680 46.970 31.480 47.410 ;
        RECT 32.380 46.970 33.180 47.410 ;
        RECT 34.080 46.970 35.545 47.410 ;
        RECT 39.180 46.970 39.980 47.410 ;
        RECT 35.780 40.470 37.245 40.910 ;
        RECT 37.480 40.470 38.945 40.910 ;
        RECT 39.180 31.370 40.645 31.810 ;
        RECT 32.380 35.270 33.180 35.710 ;
        RECT 27.280 37.870 28.745 38.310 ;
        RECT 37.480 37.870 38.945 38.310 ;
        RECT 39.180 35.270 40.645 35.710 ;
        RECT 32.380 32.670 33.180 33.110 ;
        RECT 28.980 41.770 29.780 42.210 ;
        RECT 32.380 41.770 33.180 42.210 ;
        RECT 27.280 26.170 28.080 26.610 ;
        RECT 28.980 26.170 30.445 26.610 ;
        RECT 34.080 26.170 35.545 26.610 ;
        RECT 35.780 26.170 36.580 26.610 ;
        RECT 37.480 41.770 38.280 42.210 ;
        RECT 39.180 41.770 39.980 42.210 ;
        RECT 37.480 32.670 38.945 33.110 ;
        RECT 35.780 36.570 36.580 37.010 ;
        RECT 27.280 27.470 28.080 27.910 ;
        RECT 37.480 27.470 38.280 27.910 ;
        RECT 39.180 27.470 40.645 27.910 ;
        RECT 28.980 39.170 29.780 39.610 ;
        RECT 28.980 43.070 29.780 43.510 ;
        RECT 30.680 43.070 32.145 43.510 ;
        RECT 28.980 28.770 29.780 29.210 ;
        RECT 32.380 28.770 33.845 29.210 ;
        RECT 32.380 43.070 33.845 43.510 ;
        RECT 34.080 43.070 35.545 43.510 ;
        RECT 37.480 43.070 38.280 43.510 ;
        RECT 30.680 39.170 31.480 39.610 ;
        RECT 27.280 30.070 28.745 30.510 ;
        RECT 35.780 30.070 37.245 30.510 ;
        RECT 37.480 30.070 38.280 30.510 ;
        RECT 39.180 30.070 40.645 30.510 ;
        RECT 35.780 39.170 37.245 39.610 ;
        RECT 37.480 36.570 38.280 37.010 ;
        RECT 39.180 36.570 40.645 37.010 ;
        RECT 35.780 5.370 36.580 5.810 ;
        RECT 37.480 5.370 38.945 5.810 ;
        RECT 35.780 13.170 37.245 13.610 ;
        RECT 37.480 13.170 38.945 13.610 ;
        RECT 30.680 19.670 31.480 20.110 ;
        RECT 32.380 19.670 33.180 20.110 ;
        RECT 32.380 20.970 33.845 21.410 ;
        RECT 35.780 20.970 37.245 21.410 ;
        RECT 30.680 0.170 31.480 0.610 ;
        RECT 35.780 0.170 36.580 0.610 ;
        RECT 37.480 0.170 38.280 0.610 ;
        RECT 35.780 14.470 36.580 14.910 ;
        RECT 30.680 1.470 31.480 1.910 ;
        RECT 34.080 1.470 35.545 1.910 ;
        RECT 37.480 20.970 38.945 21.410 ;
        RECT 39.180 20.970 39.980 21.410 ;
        RECT 34.080 19.670 35.545 20.110 ;
        RECT 39.180 19.670 39.980 20.110 ;
        RECT 39.180 9.270 39.980 9.710 ;
        RECT 32.380 2.770 33.180 3.210 ;
        RECT 35.780 1.470 36.580 1.910 ;
        RECT 27.280 23.570 28.080 24.010 ;
        RECT 28.980 6.670 30.445 7.110 ;
        RECT 34.080 6.670 34.880 7.110 ;
        RECT 35.780 6.670 36.580 7.110 ;
        RECT 27.280 15.770 28.745 16.210 ;
        RECT 28.980 15.770 29.780 16.210 ;
        RECT 30.680 15.770 31.480 16.210 ;
        RECT 34.080 15.770 35.545 16.210 ;
        RECT 35.780 15.770 36.580 16.210 ;
        RECT 39.180 15.770 40.645 16.210 ;
        RECT 30.680 23.570 31.480 24.010 ;
        RECT 34.080 23.570 35.545 24.010 ;
        RECT 39.180 23.570 40.645 24.010 ;
        RECT 27.280 9.270 28.745 9.710 ;
        RECT 27.280 18.370 28.080 18.810 ;
        RECT 35.780 7.970 37.245 8.410 ;
        RECT 32.380 4.070 33.180 4.510 ;
        RECT 34.080 4.070 35.545 4.510 ;
        RECT 37.480 2.770 38.280 3.210 ;
        RECT 39.180 2.770 39.980 3.210 ;
        RECT 27.280 11.870 28.080 12.310 ;
        RECT 27.280 5.370 28.080 5.810 ;
        RECT 35.780 11.870 37.245 12.310 ;
        RECT 39.180 11.870 39.980 12.310 ;
        RECT 32.380 7.970 33.845 8.410 ;
        RECT 34.080 7.970 34.880 8.410 ;
        RECT 27.280 17.070 28.080 17.510 ;
        RECT 28.980 17.070 30.445 17.510 ;
        RECT 32.380 17.070 33.180 17.510 ;
        RECT 35.780 17.070 37.245 17.510 ;
        RECT 37.480 17.070 38.945 17.510 ;
        RECT 39.180 17.070 39.980 17.510 ;
        RECT 28.980 18.370 30.445 18.810 ;
        RECT 35.780 18.370 36.580 18.810 ;
        RECT 30.680 9.270 32.145 9.710 ;
        RECT 35.780 2.770 37.245 3.210 ;
        RECT 27.280 19.670 28.745 20.110 ;
        RECT 32.380 5.370 33.845 5.810 ;
        RECT 34.080 5.370 34.880 5.810 ;
        RECT 40.880 20.970 41.680 21.410 ;
        RECT 44.280 20.970 45.745 21.410 ;
        RECT 40.880 14.470 42.345 14.910 ;
        RECT 49.380 14.470 50.180 14.910 ;
        RECT 44.280 0.170 45.745 0.610 ;
        RECT 47.680 20.970 49.145 21.410 ;
        RECT 40.880 9.270 41.680 9.710 ;
        RECT 42.580 9.270 44.045 9.710 ;
        RECT 47.680 9.270 48.480 9.710 ;
        RECT 47.680 1.470 49.145 1.910 ;
        RECT 49.380 7.970 50.845 8.410 ;
        RECT 51.080 19.670 52.545 20.110 ;
        RECT 52.780 19.670 53.580 20.110 ;
        RECT 51.080 7.970 52.545 8.410 ;
        RECT 40.880 18.370 42.345 18.810 ;
        RECT 40.880 23.570 41.680 24.010 ;
        RECT 45.980 23.570 47.445 24.010 ;
        RECT 47.680 23.570 48.480 24.010 ;
        RECT 40.880 6.670 41.680 7.110 ;
        RECT 45.980 6.670 47.445 7.110 ;
        RECT 51.080 23.570 51.880 24.010 ;
        RECT 52.780 23.570 53.580 24.010 ;
        RECT 49.380 13.170 50.180 13.610 ;
        RECT 42.580 18.370 43.380 18.810 ;
        RECT 52.780 4.070 54.245 4.510 ;
        RECT 51.080 20.970 52.545 21.410 ;
        RECT 52.780 20.970 54.245 21.410 ;
        RECT 42.580 2.770 43.380 3.210 ;
        RECT 44.280 2.770 45.745 3.210 ;
        RECT 52.780 2.770 53.580 3.210 ;
        RECT 51.080 13.170 51.880 13.610 ;
        RECT 44.280 5.370 45.745 5.810 ;
        RECT 40.880 15.770 41.680 16.210 ;
        RECT 42.580 15.770 44.045 16.210 ;
        RECT 45.980 15.770 46.780 16.210 ;
        RECT 47.680 15.770 48.480 16.210 ;
        RECT 52.780 15.770 54.245 16.210 ;
        RECT 52.780 6.670 54.245 7.110 ;
        RECT 47.680 5.370 49.145 5.810 ;
        RECT 49.380 5.370 50.180 5.810 ;
        RECT 44.280 4.070 45.080 4.510 ;
        RECT 45.980 4.070 46.780 4.510 ;
        RECT 52.780 1.470 54.245 1.910 ;
        RECT 49.380 4.070 50.180 4.510 ;
        RECT 45.980 11.870 47.445 12.310 ;
        RECT 47.680 11.870 49.145 12.310 ;
        RECT 49.380 11.870 50.180 12.310 ;
        RECT 51.080 11.870 51.880 12.310 ;
        RECT 47.680 4.070 48.480 4.510 ;
        RECT 44.280 1.470 45.745 1.910 ;
        RECT 45.980 1.470 46.780 1.910 ;
        RECT 51.080 4.070 51.880 4.510 ;
        RECT 44.280 17.070 45.745 17.510 ;
        RECT 45.980 17.070 47.445 17.510 ;
        RECT 40.880 17.070 42.345 17.510 ;
        RECT 44.280 7.970 45.080 8.410 ;
        RECT 52.780 11.870 53.580 12.310 ;
        RECT 45.980 7.970 47.445 8.410 ;
        RECT 47.680 13.170 48.480 13.610 ;
        RECT 42.580 19.670 43.380 20.110 ;
        RECT 52.780 5.370 54.245 5.810 ;
        RECT 52.780 0.170 54.245 0.610 ;
        RECT 45.980 19.670 47.445 20.110 ;
        RECT 47.680 7.970 48.480 8.410 ;
      LAYER met3 ;
        RECT 7.295 48.285 7.350 48.695 ;
        RECT 7.650 48.285 7.705 48.695 ;
        RECT 15.795 48.285 15.850 48.695 ;
        RECT 16.150 48.285 16.205 48.695 ;
        RECT 20.895 48.285 20.950 48.695 ;
        RECT 21.250 48.285 21.305 48.695 ;
        RECT 29.395 48.285 29.450 48.695 ;
        RECT 29.750 48.285 29.805 48.695 ;
        RECT 34.495 48.285 34.550 48.695 ;
        RECT 34.850 48.285 34.905 48.695 ;
        RECT 42.995 48.285 43.050 48.695 ;
        RECT 43.350 48.285 43.405 48.695 ;
        RECT 46.395 48.285 46.450 48.695 ;
        RECT 46.750 48.285 46.805 48.695 ;
        RECT 48.095 48.285 48.150 48.695 ;
        RECT 48.450 48.285 48.505 48.695 ;
        RECT 49.795 48.285 49.850 48.695 ;
        RECT 50.150 48.285 50.205 48.695 ;
        RECT 2.860 48.240 3.400 48.740 ;
        RECT 6.260 48.240 6.800 48.740 ;
        RECT 9.660 48.240 10.200 48.740 ;
        RECT 26.660 48.240 27.200 48.740 ;
        RECT 38.560 48.240 39.100 48.740 ;
        RECT 40.260 48.240 40.800 48.740 ;
        RECT 41.960 48.240 42.500 48.740 ;
        RECT 53.860 48.240 54.400 48.740 ;
        RECT 42.995 72.985 43.050 73.395 ;
        RECT 43.350 72.985 43.405 73.395 ;
        RECT 48.760 72.940 49.300 73.440 ;
        RECT 50.460 72.940 51.000 73.440 ;
        RECT 45.360 74.240 45.900 74.740 ;
        RECT 50.460 74.240 51.000 74.740 ;
        RECT 52.160 74.240 52.700 74.740 ;
        RECT 51.495 75.585 51.550 75.995 ;
        RECT 51.850 75.585 51.905 75.995 ;
        RECT 53.195 75.585 53.250 75.995 ;
        RECT 53.550 75.585 53.605 75.995 ;
        RECT 45.360 75.540 45.900 76.040 ;
        RECT 47.060 75.540 47.600 76.040 ;
        RECT 50.460 75.540 51.000 76.040 ;
        RECT 49.795 76.885 49.850 77.295 ;
        RECT 50.150 76.885 50.205 77.295 ;
        RECT 47.060 76.840 47.600 77.340 ;
        RECT 52.160 76.840 52.700 77.340 ;
        RECT 43.660 78.140 44.200 78.640 ;
        RECT 47.060 78.140 47.600 78.640 ;
        RECT 48.760 78.140 49.300 78.640 ;
        RECT 52.160 78.140 52.700 78.640 ;
        RECT 41.295 79.485 41.350 79.895 ;
        RECT 41.650 79.485 41.705 79.895 ;
        RECT 46.395 79.485 46.450 79.895 ;
        RECT 46.750 79.485 46.805 79.895 ;
        RECT 48.760 79.440 49.300 79.940 ;
        RECT 52.160 79.440 52.700 79.940 ;
        RECT 53.860 79.440 54.400 79.940 ;
        RECT 49.795 82.085 49.850 82.495 ;
        RECT 50.150 82.085 50.205 82.495 ;
        RECT 53.195 82.085 53.250 82.495 ;
        RECT 53.550 82.085 53.605 82.495 ;
        RECT 41.960 82.040 42.500 82.540 ;
        RECT 43.660 82.040 44.200 82.540 ;
        RECT 42.995 83.385 43.050 83.795 ;
        RECT 43.350 83.385 43.405 83.795 ;
        RECT 47.060 83.340 47.600 83.840 ;
        RECT 48.760 83.340 49.300 83.840 ;
        RECT 53.860 83.340 54.400 83.840 ;
        RECT 44.695 84.685 44.750 85.095 ;
        RECT 45.050 84.685 45.105 85.095 ;
        RECT 48.095 84.685 48.150 85.095 ;
        RECT 48.450 84.685 48.505 85.095 ;
        RECT 43.660 84.640 44.200 85.140 ;
        RECT 46.395 85.985 46.450 86.395 ;
        RECT 46.750 85.985 46.805 86.395 ;
        RECT 45.360 85.940 45.900 86.440 ;
        RECT 44.695 87.285 44.750 87.695 ;
        RECT 45.050 87.285 45.105 87.695 ;
        RECT 48.095 87.285 48.150 87.695 ;
        RECT 48.450 87.285 48.505 87.695 ;
        RECT 49.795 87.285 49.850 87.695 ;
        RECT 50.150 87.285 50.205 87.695 ;
        RECT 53.860 87.240 54.400 87.740 ;
        RECT 41.295 88.585 41.350 88.995 ;
        RECT 41.650 88.585 41.705 88.995 ;
        RECT 42.995 88.585 43.050 88.995 ;
        RECT 43.350 88.585 43.405 88.995 ;
        RECT 45.360 88.540 45.900 89.040 ;
        RECT 47.060 88.540 47.600 89.040 ;
        RECT 48.760 88.540 49.300 89.040 ;
        RECT 50.460 88.540 51.000 89.040 ;
        RECT 41.295 89.885 41.350 90.295 ;
        RECT 41.650 89.885 41.705 90.295 ;
        RECT 44.695 89.885 44.750 90.295 ;
        RECT 45.050 89.885 45.105 90.295 ;
        RECT 43.660 89.840 44.200 90.340 ;
        RECT 52.160 89.840 52.700 90.340 ;
        RECT 53.860 89.840 54.400 90.340 ;
        RECT 44.695 91.185 44.750 91.595 ;
        RECT 45.050 91.185 45.105 91.595 ;
        RECT 46.395 91.185 46.450 91.595 ;
        RECT 46.750 91.185 46.805 91.595 ;
        RECT 51.495 91.185 51.550 91.595 ;
        RECT 51.850 91.185 51.905 91.595 ;
        RECT 41.960 91.140 42.500 91.640 ;
        RECT 41.350 92.300 41.770 93.700 ;
        RECT 43.050 92.300 43.470 93.700 ;
        RECT 44.750 92.300 45.170 93.700 ;
        RECT 46.450 92.300 46.870 93.700 ;
        RECT 48.150 92.300 48.570 93.700 ;
        RECT 49.850 92.300 50.270 93.700 ;
        RECT 51.550 92.300 51.970 93.700 ;
        RECT 53.250 92.300 53.670 93.700 ;
        RECT 42.040 95.130 42.485 95.690 ;
        RECT 43.740 95.130 44.185 95.690 ;
        RECT 45.440 95.130 45.885 95.690 ;
        RECT 47.140 95.130 47.585 95.690 ;
        RECT 48.840 95.130 49.285 95.690 ;
        RECT 50.540 95.130 50.985 95.690 ;
        RECT 52.240 95.130 52.685 95.690 ;
        RECT 53.940 95.130 54.385 95.690 ;
        RECT 31.760 84.640 32.300 85.140 ;
        RECT 33.460 84.640 34.000 85.140 ;
        RECT 36.195 84.685 36.250 85.095 ;
        RECT 36.550 84.685 36.605 85.095 ;
        RECT 39.595 84.685 39.650 85.095 ;
        RECT 39.950 84.685 40.005 85.095 ;
        RECT 40.260 85.940 40.800 86.440 ;
        RECT 37.895 87.285 37.950 87.695 ;
        RECT 38.250 87.285 38.305 87.695 ;
        RECT 39.595 87.285 39.650 87.695 ;
        RECT 39.950 87.285 40.005 87.695 ;
        RECT 34.495 88.585 34.550 88.995 ;
        RECT 34.850 88.585 34.905 88.995 ;
        RECT 37.895 88.585 37.950 88.995 ;
        RECT 38.250 88.585 38.305 88.995 ;
        RECT 36.860 88.540 37.400 89.040 ;
        RECT 39.595 89.885 39.650 90.295 ;
        RECT 39.950 89.885 40.005 90.295 ;
        RECT 38.560 89.840 39.100 90.340 ;
        RECT 36.195 91.185 36.250 91.595 ;
        RECT 36.550 91.185 36.605 91.595 ;
        RECT 35.160 91.140 35.700 91.640 ;
        RECT 34.550 92.300 34.970 93.700 ;
        RECT 36.250 92.300 36.670 93.700 ;
        RECT 37.950 92.300 38.370 93.700 ;
        RECT 39.650 92.300 40.070 93.700 ;
        RECT 35.240 95.130 35.685 95.690 ;
        RECT 36.940 95.130 37.385 95.690 ;
        RECT 38.640 95.130 39.085 95.690 ;
        RECT 40.340 95.130 40.785 95.690 ;
        RECT 34.495 85.985 34.550 86.395 ;
        RECT 34.850 85.985 34.905 86.395 ;
        RECT 37.895 85.985 37.950 86.395 ;
        RECT 38.250 85.985 38.305 86.395 ;
        RECT 29.750 91.185 29.805 91.595 ;
        RECT 31.095 91.185 31.150 91.595 ;
        RECT 31.450 91.185 31.505 91.595 ;
        RECT 29.395 88.585 29.450 88.995 ;
        RECT 31.760 88.540 32.300 89.040 ;
        RECT 33.460 91.140 34.000 91.640 ;
        RECT 29.750 88.585 29.805 88.995 ;
        RECT 27.750 92.300 28.170 93.700 ;
        RECT 29.450 92.300 29.870 93.700 ;
        RECT 31.150 92.300 31.570 93.700 ;
        RECT 32.850 92.300 33.270 93.700 ;
        RECT 27.695 89.885 27.750 90.295 ;
        RECT 28.050 89.885 28.105 90.295 ;
        RECT 29.395 89.885 29.450 90.295 ;
        RECT 29.750 89.885 29.805 90.295 ;
        RECT 28.440 95.130 28.885 95.690 ;
        RECT 30.140 95.130 30.585 95.690 ;
        RECT 31.840 95.130 32.285 95.690 ;
        RECT 33.540 95.130 33.985 95.690 ;
        RECT 32.795 89.885 32.850 90.295 ;
        RECT 33.150 89.885 33.205 90.295 ;
        RECT 33.460 85.940 34.000 86.440 ;
        RECT 30.060 87.240 30.600 87.740 ;
        RECT 31.760 87.240 32.300 87.740 ;
        RECT 27.695 91.185 27.750 91.595 ;
        RECT 28.050 91.185 28.105 91.595 ;
        RECT 29.395 91.185 29.450 91.595 ;
        RECT 28.360 78.140 28.900 78.640 ;
        RECT 33.460 72.940 34.000 73.440 ;
        RECT 27.695 72.985 27.750 73.395 ;
        RECT 27.695 79.485 27.750 79.895 ;
        RECT 28.050 79.485 28.105 79.895 ;
        RECT 28.050 72.985 28.105 73.395 ;
        RECT 33.460 75.540 34.000 76.040 ;
        RECT 29.395 74.285 29.450 74.695 ;
        RECT 29.750 74.285 29.805 74.695 ;
        RECT 28.360 83.340 28.900 83.840 ;
        RECT 33.150 74.285 33.205 74.695 ;
        RECT 31.095 75.585 31.150 75.995 ;
        RECT 32.795 82.085 32.850 82.495 ;
        RECT 33.150 82.085 33.205 82.495 ;
        RECT 31.095 72.985 31.150 73.395 ;
        RECT 31.450 72.985 31.505 73.395 ;
        RECT 28.360 75.540 28.900 76.040 ;
        RECT 31.760 79.440 32.300 79.940 ;
        RECT 32.795 74.285 32.850 74.695 ;
        RECT 31.450 75.585 31.505 75.995 ;
        RECT 30.060 82.040 30.600 82.540 ;
        RECT 27.695 82.085 27.750 82.495 ;
        RECT 28.050 82.085 28.105 82.495 ;
        RECT 37.895 79.485 37.950 79.895 ;
        RECT 38.250 79.485 38.305 79.895 ;
        RECT 35.160 75.540 35.700 76.040 ;
        RECT 39.595 76.885 39.650 77.295 ;
        RECT 36.860 74.240 37.400 74.740 ;
        RECT 38.560 72.940 39.100 73.440 ;
        RECT 35.160 83.340 35.700 83.840 ;
        RECT 36.860 83.340 37.400 83.840 ;
        RECT 38.560 83.340 39.100 83.840 ;
        RECT 35.160 79.440 35.700 79.940 ;
        RECT 39.595 75.585 39.650 75.995 ;
        RECT 39.950 75.585 40.005 75.995 ;
        RECT 39.950 76.885 40.005 77.295 ;
        RECT 35.160 72.940 35.700 73.440 ;
        RECT 35.160 78.140 35.700 78.640 ;
        RECT 37.895 75.585 37.950 75.995 ;
        RECT 38.250 75.585 38.305 75.995 ;
        RECT 40.260 74.240 40.800 74.740 ;
        RECT 36.195 76.885 36.250 77.295 ;
        RECT 36.550 76.885 36.605 77.295 ;
        RECT 34.850 74.285 34.905 74.695 ;
        RECT 38.250 76.885 38.305 77.295 ;
        RECT 34.495 74.285 34.550 74.695 ;
        RECT 35.160 76.840 35.700 77.340 ;
        RECT 37.895 76.885 37.950 77.295 ;
        RECT 35.160 53.440 35.700 53.940 ;
        RECT 40.260 53.440 40.800 53.940 ;
        RECT 32.795 54.785 32.850 55.195 ;
        RECT 33.150 54.785 33.205 55.195 ;
        RECT 36.195 54.785 36.250 55.195 ;
        RECT 36.550 54.785 36.605 55.195 ;
        RECT 30.060 54.740 30.600 55.240 ;
        RECT 32.795 56.085 32.850 56.495 ;
        RECT 33.150 56.085 33.205 56.495 ;
        RECT 34.495 56.085 34.550 56.495 ;
        RECT 34.850 56.085 34.905 56.495 ;
        RECT 36.195 56.085 36.250 56.495 ;
        RECT 36.550 56.085 36.605 56.495 ;
        RECT 39.595 56.085 39.650 56.495 ;
        RECT 39.950 56.085 40.005 56.495 ;
        RECT 29.395 58.685 29.450 59.095 ;
        RECT 29.750 58.685 29.805 59.095 ;
        RECT 32.795 58.685 32.850 59.095 ;
        RECT 33.150 58.685 33.205 59.095 ;
        RECT 38.560 58.640 39.100 59.140 ;
        RECT 40.260 58.640 40.800 59.140 ;
        RECT 27.695 59.985 27.750 60.395 ;
        RECT 28.050 59.985 28.105 60.395 ;
        RECT 29.395 59.985 29.450 60.395 ;
        RECT 29.750 59.985 29.805 60.395 ;
        RECT 34.495 59.985 34.550 60.395 ;
        RECT 34.850 59.985 34.905 60.395 ;
        RECT 31.760 59.940 32.300 60.440 ;
        RECT 40.260 59.940 40.800 60.440 ;
        RECT 34.495 61.285 34.550 61.695 ;
        RECT 34.850 61.285 34.905 61.695 ;
        RECT 36.195 61.285 36.250 61.695 ;
        RECT 36.550 61.285 36.605 61.695 ;
        RECT 39.595 61.285 39.650 61.695 ;
        RECT 39.950 61.285 40.005 61.695 ;
        RECT 28.360 61.240 28.900 61.740 ;
        RECT 31.760 61.240 32.300 61.740 ;
        RECT 38.560 61.240 39.100 61.740 ;
        RECT 36.195 62.585 36.250 62.995 ;
        RECT 36.550 62.585 36.605 62.995 ;
        RECT 31.760 62.540 32.300 63.040 ;
        RECT 30.060 63.840 30.600 64.340 ;
        RECT 33.460 63.840 34.000 64.340 ;
        RECT 36.860 63.840 37.400 64.340 ;
        RECT 39.595 65.185 39.650 65.595 ;
        RECT 39.950 65.185 40.005 65.595 ;
        RECT 28.360 65.140 28.900 65.640 ;
        RECT 30.060 65.140 30.600 65.640 ;
        RECT 35.160 65.140 35.700 65.640 ;
        RECT 36.860 65.140 37.400 65.640 ;
        RECT 31.095 66.485 31.150 66.895 ;
        RECT 31.450 66.485 31.505 66.895 ;
        RECT 36.195 66.485 36.250 66.895 ;
        RECT 36.550 66.485 36.605 66.895 ;
        RECT 28.360 66.440 28.900 66.940 ;
        RECT 35.160 66.440 35.700 66.940 ;
        RECT 38.560 66.440 39.100 66.940 ;
        RECT 40.260 66.440 40.800 66.940 ;
        RECT 27.695 67.785 27.750 68.195 ;
        RECT 28.050 67.785 28.105 68.195 ;
        RECT 31.095 67.785 31.150 68.195 ;
        RECT 31.450 67.785 31.505 68.195 ;
        RECT 30.060 67.740 30.600 68.240 ;
        RECT 35.160 67.740 35.700 68.240 ;
        RECT 38.560 67.740 39.100 68.240 ;
        RECT 38.560 70.340 39.100 70.840 ;
        RECT 27.695 71.685 27.750 72.095 ;
        RECT 28.050 71.685 28.105 72.095 ;
        RECT 30.060 71.640 30.600 72.140 ;
        RECT 33.460 71.640 34.000 72.140 ;
        RECT 35.160 71.640 35.700 72.140 ;
        RECT 27.695 49.585 27.750 49.995 ;
        RECT 28.050 49.585 28.105 49.995 ;
        RECT 31.095 49.585 31.150 49.995 ;
        RECT 31.450 49.585 31.505 49.995 ;
        RECT 36.195 49.585 36.250 49.995 ;
        RECT 36.550 49.585 36.605 49.995 ;
        RECT 35.160 49.540 35.700 50.040 ;
        RECT 34.495 50.885 34.550 51.295 ;
        RECT 34.850 50.885 34.905 51.295 ;
        RECT 31.760 50.840 32.300 51.340 ;
        RECT 36.195 52.185 36.250 52.595 ;
        RECT 36.550 52.185 36.605 52.595 ;
        RECT 28.360 52.140 28.900 52.640 ;
        RECT 30.060 52.140 30.600 52.640 ;
        RECT 27.695 53.485 27.750 53.895 ;
        RECT 28.050 53.485 28.105 53.895 ;
        RECT 29.395 53.485 29.450 53.895 ;
        RECT 29.750 53.485 29.805 53.895 ;
        RECT 36.195 53.485 36.250 53.895 ;
        RECT 36.550 53.485 36.605 53.895 ;
        RECT 41.295 56.085 41.350 56.495 ;
        RECT 41.650 56.085 41.705 56.495 ;
        RECT 45.360 63.840 45.900 64.340 ;
        RECT 50.460 63.840 51.000 64.340 ;
        RECT 46.395 56.085 46.450 56.495 ;
        RECT 46.750 56.085 46.805 56.495 ;
        RECT 53.195 65.185 53.250 65.595 ;
        RECT 53.550 65.185 53.605 65.595 ;
        RECT 51.495 56.085 51.550 56.495 ;
        RECT 51.850 56.085 51.905 56.495 ;
        RECT 43.660 56.040 44.200 56.540 ;
        RECT 45.360 56.040 45.900 56.540 ;
        RECT 45.360 65.140 45.900 65.640 ;
        RECT 50.460 65.140 51.000 65.640 ;
        RECT 53.550 49.585 53.605 49.995 ;
        RECT 47.060 52.140 47.600 52.640 ;
        RECT 44.695 49.585 44.750 49.995 ;
        RECT 50.460 49.540 51.000 50.040 ;
        RECT 49.795 66.485 49.850 66.895 ;
        RECT 50.150 66.485 50.205 66.895 ;
        RECT 53.195 66.485 53.250 66.895 ;
        RECT 53.550 66.485 53.605 66.895 ;
        RECT 42.995 58.685 43.050 59.095 ;
        RECT 43.350 58.685 43.405 59.095 ;
        RECT 51.495 58.685 51.550 59.095 ;
        RECT 51.850 58.685 51.905 59.095 ;
        RECT 41.960 66.440 42.500 66.940 ;
        RECT 43.660 66.440 44.200 66.940 ;
        RECT 45.050 49.585 45.105 49.995 ;
        RECT 48.095 49.585 48.150 49.995 ;
        RECT 41.960 58.640 42.500 59.140 ;
        RECT 42.995 50.885 43.050 51.295 ;
        RECT 43.350 50.885 43.405 51.295 ;
        RECT 51.495 50.885 51.550 51.295 ;
        RECT 51.850 50.885 51.905 51.295 ;
        RECT 41.960 67.740 42.500 68.240 ;
        RECT 43.660 67.740 44.200 68.240 ;
        RECT 53.860 67.740 54.400 68.240 ;
        RECT 42.995 70.385 43.050 70.795 ;
        RECT 43.350 70.385 43.405 70.795 ;
        RECT 49.795 70.385 49.850 70.795 ;
        RECT 50.150 70.385 50.205 70.795 ;
        RECT 41.960 53.440 42.500 53.940 ;
        RECT 48.450 49.585 48.505 49.995 ;
        RECT 42.995 59.985 43.050 60.395 ;
        RECT 49.795 71.685 49.850 72.095 ;
        RECT 50.150 71.685 50.205 72.095 ;
        RECT 43.350 59.985 43.405 60.395 ;
        RECT 44.695 59.985 44.750 60.395 ;
        RECT 45.050 59.985 45.105 60.395 ;
        RECT 43.660 71.640 44.200 72.140 ;
        RECT 45.360 71.640 45.900 72.140 ;
        RECT 47.060 71.640 47.600 72.140 ;
        RECT 51.495 59.985 51.550 60.395 ;
        RECT 51.850 59.985 51.905 60.395 ;
        RECT 45.360 50.840 45.900 51.340 ;
        RECT 48.760 50.840 49.300 51.340 ;
        RECT 41.960 59.940 42.500 60.440 ;
        RECT 50.460 59.940 51.000 60.440 ;
        RECT 53.860 59.940 54.400 60.440 ;
        RECT 53.860 50.840 54.400 51.340 ;
        RECT 51.495 54.785 51.550 55.195 ;
        RECT 51.850 54.785 51.905 55.195 ;
        RECT 51.495 49.585 51.550 49.995 ;
        RECT 48.760 54.740 49.300 55.240 ;
        RECT 51.850 49.585 51.905 49.995 ;
        RECT 42.995 52.185 43.050 52.595 ;
        RECT 43.350 52.185 43.405 52.595 ;
        RECT 44.695 52.185 44.750 52.595 ;
        RECT 48.760 61.240 49.300 61.740 ;
        RECT 45.050 52.185 45.105 52.595 ;
        RECT 53.195 52.185 53.250 52.595 ;
        RECT 41.295 62.585 41.350 62.995 ;
        RECT 41.650 62.585 41.705 62.995 ;
        RECT 42.995 62.585 43.050 62.995 ;
        RECT 43.350 62.585 43.405 62.995 ;
        RECT 48.095 62.585 48.150 62.995 ;
        RECT 48.450 62.585 48.505 62.995 ;
        RECT 51.495 62.585 51.550 62.995 ;
        RECT 51.850 62.585 51.905 62.995 ;
        RECT 53.550 52.185 53.605 52.595 ;
        RECT 53.860 62.540 54.400 63.040 ;
        RECT 42.995 63.885 43.050 64.295 ;
        RECT 43.350 63.885 43.405 64.295 ;
        RECT 53.195 49.585 53.250 49.995 ;
        RECT 14.760 72.940 15.300 73.440 ;
        RECT 21.560 72.940 22.100 73.440 ;
        RECT 24.960 72.940 25.500 73.440 ;
        RECT 26.660 72.940 27.200 73.440 ;
        RECT 15.795 74.285 15.850 74.695 ;
        RECT 16.150 74.285 16.205 74.695 ;
        RECT 19.195 74.285 19.250 74.695 ;
        RECT 19.550 74.285 19.605 74.695 ;
        RECT 14.760 74.240 15.300 74.740 ;
        RECT 18.160 74.240 18.700 74.740 ;
        RECT 23.260 74.240 23.800 74.740 ;
        RECT 14.095 75.585 14.150 75.995 ;
        RECT 14.450 75.585 14.505 75.995 ;
        RECT 15.795 75.585 15.850 75.995 ;
        RECT 16.150 75.585 16.205 75.995 ;
        RECT 20.895 75.585 20.950 75.995 ;
        RECT 21.250 75.585 21.305 75.995 ;
        RECT 24.295 75.585 24.350 75.995 ;
        RECT 24.650 75.585 24.705 75.995 ;
        RECT 18.160 75.540 18.700 76.040 ;
        RECT 20.895 76.885 20.950 77.295 ;
        RECT 21.250 76.885 21.305 77.295 ;
        RECT 25.995 76.885 26.050 77.295 ;
        RECT 26.350 76.885 26.405 77.295 ;
        RECT 14.760 76.840 15.300 77.340 ;
        RECT 16.460 76.840 17.000 77.340 ;
        RECT 23.260 76.840 23.800 77.340 ;
        RECT 24.960 76.840 25.500 77.340 ;
        RECT 17.495 78.185 17.550 78.595 ;
        RECT 17.850 78.185 17.905 78.595 ;
        RECT 14.760 78.140 15.300 78.640 ;
        RECT 16.460 78.140 17.000 78.640 ;
        RECT 26.660 78.140 27.200 78.640 ;
        RECT 20.895 79.485 20.950 79.895 ;
        RECT 21.250 79.485 21.305 79.895 ;
        RECT 18.160 79.440 18.700 79.940 ;
        RECT 23.260 79.440 23.800 79.940 ;
        RECT 25.995 82.085 26.050 82.495 ;
        RECT 26.350 82.085 26.405 82.495 ;
        RECT 14.760 82.040 15.300 82.540 ;
        RECT 16.460 82.040 17.000 82.540 ;
        RECT 21.560 82.040 22.100 82.540 ;
        RECT 14.095 83.385 14.150 83.795 ;
        RECT 14.450 83.385 14.505 83.795 ;
        RECT 17.495 83.385 17.550 83.795 ;
        RECT 17.850 83.385 17.905 83.795 ;
        RECT 24.295 83.385 24.350 83.795 ;
        RECT 24.650 83.385 24.705 83.795 ;
        RECT 21.560 83.340 22.100 83.840 ;
        RECT 23.260 83.340 23.800 83.840 ;
        RECT 14.095 84.685 14.150 85.095 ;
        RECT 14.450 84.685 14.505 85.095 ;
        RECT 15.795 84.685 15.850 85.095 ;
        RECT 16.150 84.685 16.205 85.095 ;
        RECT 25.995 84.685 26.050 85.095 ;
        RECT 26.350 84.685 26.405 85.095 ;
        RECT 24.960 84.640 25.500 85.140 ;
        RECT 20.895 85.985 20.950 86.395 ;
        RECT 21.250 85.985 21.305 86.395 ;
        RECT 24.295 85.985 24.350 86.395 ;
        RECT 24.650 85.985 24.705 86.395 ;
        RECT 14.760 85.940 15.300 86.440 ;
        RECT 18.160 85.940 18.700 86.440 ;
        RECT 14.095 87.285 14.150 87.695 ;
        RECT 14.450 87.285 14.505 87.695 ;
        RECT 16.460 87.240 17.000 87.740 ;
        RECT 21.560 87.240 22.100 87.740 ;
        RECT 24.960 87.240 25.500 87.740 ;
        RECT 26.660 87.240 27.200 87.740 ;
        RECT 14.095 88.585 14.150 88.995 ;
        RECT 14.450 88.585 14.505 88.995 ;
        RECT 19.195 88.585 19.250 88.995 ;
        RECT 19.550 88.585 19.605 88.995 ;
        RECT 23.260 88.540 23.800 89.040 ;
        RECT 24.960 88.540 25.500 89.040 ;
        RECT 26.660 88.540 27.200 89.040 ;
        RECT 16.460 89.840 17.000 90.340 ;
        RECT 24.960 89.840 25.500 90.340 ;
        RECT 14.095 91.185 14.150 91.595 ;
        RECT 14.450 91.185 14.505 91.595 ;
        RECT 25.995 91.185 26.050 91.595 ;
        RECT 26.350 91.185 26.405 91.595 ;
        RECT 16.460 91.140 17.000 91.640 ;
        RECT 14.150 92.300 14.570 93.700 ;
        RECT 15.850 92.300 16.270 93.700 ;
        RECT 17.550 92.300 17.970 93.700 ;
        RECT 19.250 92.300 19.670 93.700 ;
        RECT 20.950 92.300 21.370 93.700 ;
        RECT 22.650 92.300 23.070 93.700 ;
        RECT 24.350 92.300 24.770 93.700 ;
        RECT 26.050 92.300 26.470 93.700 ;
        RECT 15.685 94.090 16.095 94.135 ;
        RECT 14.840 95.130 15.285 95.690 ;
        RECT 16.540 95.130 16.985 95.690 ;
        RECT 18.240 95.130 18.685 95.690 ;
        RECT 19.940 95.130 20.385 95.690 ;
        RECT 21.640 95.130 22.085 95.690 ;
        RECT 23.340 95.130 23.785 95.690 ;
        RECT 25.040 95.130 25.485 95.690 ;
        RECT 26.740 95.130 27.185 95.690 ;
        RECT 7.960 84.640 8.500 85.140 ;
        RECT 13.060 78.140 13.600 78.640 ;
        RECT 0.495 85.985 0.550 86.395 ;
        RECT 0.850 85.985 0.905 86.395 ;
        RECT 5.595 85.985 5.650 86.395 ;
        RECT 5.950 85.985 6.005 86.395 ;
        RECT 8.995 85.985 9.050 86.395 ;
        RECT 9.350 85.985 9.405 86.395 ;
        RECT 10.695 85.985 10.750 86.395 ;
        RECT 11.050 85.985 11.105 86.395 ;
        RECT 12.750 74.285 12.805 74.695 ;
        RECT 2.860 72.940 3.400 73.440 ;
        RECT 4.560 72.940 5.100 73.440 ;
        RECT 3.895 79.485 3.950 79.895 ;
        RECT 7.960 85.940 8.500 86.440 ;
        RECT 13.060 85.940 13.600 86.440 ;
        RECT 4.250 79.485 4.305 79.895 ;
        RECT 0.495 74.285 0.550 74.695 ;
        RECT 2.195 87.285 2.250 87.695 ;
        RECT 2.550 87.285 2.605 87.695 ;
        RECT 7.295 87.285 7.350 87.695 ;
        RECT 7.650 87.285 7.705 87.695 ;
        RECT 0.850 74.285 0.905 74.695 ;
        RECT 11.360 79.440 11.900 79.940 ;
        RECT 4.560 87.240 5.100 87.740 ;
        RECT 9.660 74.240 10.200 74.740 ;
        RECT 1.160 75.540 1.700 76.040 ;
        RECT 12.395 82.085 12.450 82.495 ;
        RECT 12.750 82.085 12.805 82.495 ;
        RECT 0.495 88.585 0.550 88.995 ;
        RECT 0.850 88.585 0.905 88.995 ;
        RECT 2.195 74.285 2.250 74.695 ;
        RECT 2.550 74.285 2.605 74.695 ;
        RECT 4.560 82.040 5.100 82.540 ;
        RECT 6.260 82.040 6.800 82.540 ;
        RECT 2.860 88.540 3.400 89.040 ;
        RECT 7.960 88.540 8.500 89.040 ;
        RECT 9.660 88.540 10.200 89.040 ;
        RECT 7.295 74.285 7.350 74.695 ;
        RECT 2.195 75.585 2.250 75.995 ;
        RECT 2.550 75.585 2.605 75.995 ;
        RECT 3.895 89.885 3.950 90.295 ;
        RECT 4.250 89.885 4.305 90.295 ;
        RECT 10.695 89.885 10.750 90.295 ;
        RECT 11.050 89.885 11.105 90.295 ;
        RECT 3.895 83.385 3.950 83.795 ;
        RECT 4.250 83.385 4.305 83.795 ;
        RECT 2.195 91.185 2.250 91.595 ;
        RECT 2.550 91.185 2.605 91.595 ;
        RECT 5.595 83.385 5.650 83.795 ;
        RECT 5.950 83.385 6.005 83.795 ;
        RECT 8.995 83.385 9.050 83.795 ;
        RECT 9.350 83.385 9.405 83.795 ;
        RECT 1.160 91.140 1.700 91.640 ;
        RECT 4.560 91.140 5.100 91.640 ;
        RECT 7.960 91.140 8.500 91.640 ;
        RECT 1.160 76.840 1.700 77.340 ;
        RECT 0.550 92.300 0.970 93.700 ;
        RECT 2.250 92.300 2.670 93.700 ;
        RECT 3.950 92.300 4.370 93.700 ;
        RECT 5.650 92.300 6.070 93.700 ;
        RECT 7.350 92.300 7.770 93.700 ;
        RECT 9.050 92.300 9.470 93.700 ;
        RECT 10.750 92.300 11.170 93.700 ;
        RECT 12.450 92.300 12.870 93.700 ;
        RECT 9.660 76.840 10.200 77.340 ;
        RECT 13.060 76.840 13.600 77.340 ;
        RECT 3.895 75.585 3.950 75.995 ;
        RECT 4.250 75.585 4.305 75.995 ;
        RECT 8.995 75.585 9.050 75.995 ;
        RECT 1.160 83.340 1.700 83.840 ;
        RECT 13.060 83.340 13.600 83.840 ;
        RECT 9.350 75.585 9.405 75.995 ;
        RECT 0.495 78.185 0.550 78.595 ;
        RECT 1.240 95.130 1.685 95.690 ;
        RECT 2.940 95.130 3.385 95.690 ;
        RECT 4.640 95.130 5.085 95.690 ;
        RECT 6.340 95.130 6.785 95.690 ;
        RECT 8.040 95.130 8.485 95.690 ;
        RECT 9.740 95.130 10.185 95.690 ;
        RECT 11.440 95.130 11.885 95.690 ;
        RECT 13.140 95.130 13.585 95.690 ;
        RECT 10.695 84.685 10.750 85.095 ;
        RECT 11.050 84.685 11.105 85.095 ;
        RECT 0.850 78.185 0.905 78.595 ;
        RECT 10.695 78.185 10.750 78.595 ;
        RECT 11.050 78.185 11.105 78.595 ;
        RECT 7.650 74.285 7.705 74.695 ;
        RECT 12.395 74.285 12.450 74.695 ;
        RECT 6.260 78.140 6.800 78.640 ;
        RECT 5.595 72.985 5.650 73.395 ;
        RECT 5.950 72.985 6.005 73.395 ;
        RECT 7.295 72.985 7.350 73.395 ;
        RECT 7.650 72.985 7.705 73.395 ;
        RECT 8.995 72.985 9.050 73.395 ;
        RECT 9.350 72.985 9.405 73.395 ;
        RECT 7.930 96.380 8.470 96.920 ;
        RECT 5.950 63.885 6.005 64.295 ;
        RECT 10.695 63.885 10.750 64.295 ;
        RECT 11.050 63.885 11.105 64.295 ;
        RECT 12.395 63.885 12.450 64.295 ;
        RECT 12.750 63.885 12.805 64.295 ;
        RECT 11.360 61.240 11.900 61.740 ;
        RECT 5.595 53.485 5.650 53.895 ;
        RECT 5.950 53.485 6.005 53.895 ;
        RECT 12.395 53.485 12.450 53.895 ;
        RECT 7.650 50.885 7.705 51.295 ;
        RECT 2.195 49.585 2.250 49.995 ;
        RECT 6.260 58.640 6.800 59.140 ;
        RECT 6.260 67.740 6.800 68.240 ;
        RECT 9.660 67.740 10.200 68.240 ;
        RECT 7.960 58.640 8.500 59.140 ;
        RECT 12.395 56.085 12.450 56.495 ;
        RECT 4.560 56.040 5.100 56.540 ;
        RECT 2.550 49.585 2.605 49.995 ;
        RECT 11.360 49.540 11.900 50.040 ;
        RECT 0.495 70.385 0.550 70.795 ;
        RECT 6.260 56.040 6.800 56.540 ;
        RECT 12.750 56.085 12.805 56.495 ;
        RECT 2.860 63.840 3.400 64.340 ;
        RECT 9.660 63.840 10.200 64.340 ;
        RECT 13.060 52.140 13.600 52.640 ;
        RECT 13.060 61.240 13.600 61.740 ;
        RECT 0.850 70.385 0.905 70.795 ;
        RECT 2.195 70.385 2.250 70.795 ;
        RECT 2.550 70.385 2.605 70.795 ;
        RECT 7.295 70.385 7.350 70.795 ;
        RECT 7.650 70.385 7.705 70.795 ;
        RECT 10.695 70.385 10.750 70.795 ;
        RECT 11.050 70.385 11.105 70.795 ;
        RECT 13.060 49.540 13.600 50.040 ;
        RECT 7.650 54.785 7.705 55.195 ;
        RECT 12.395 54.785 12.450 55.195 ;
        RECT 7.650 49.585 7.705 49.995 ;
        RECT 9.660 54.740 10.200 55.240 ;
        RECT 4.560 53.440 5.100 53.940 ;
        RECT 4.560 70.340 5.100 70.840 ;
        RECT 0.495 65.185 0.550 65.595 ;
        RECT 3.895 62.585 3.950 62.995 ;
        RECT 4.250 62.585 4.305 62.995 ;
        RECT 12.750 53.485 12.805 53.895 ;
        RECT 0.495 66.485 0.550 66.895 ;
        RECT 0.850 66.485 0.905 66.895 ;
        RECT 7.295 49.585 7.350 49.995 ;
        RECT 0.495 52.185 0.550 52.595 ;
        RECT 12.750 54.785 12.805 55.195 ;
        RECT 5.595 61.285 5.650 61.695 ;
        RECT 5.595 66.485 5.650 66.895 ;
        RECT 5.950 66.485 6.005 66.895 ;
        RECT 1.160 62.540 1.700 63.040 ;
        RECT 7.960 62.540 8.500 63.040 ;
        RECT 7.295 50.885 7.350 51.295 ;
        RECT 5.950 61.285 6.005 61.695 ;
        RECT 9.660 53.440 10.200 53.940 ;
        RECT 3.895 71.685 3.950 72.095 ;
        RECT 4.250 71.685 4.305 72.095 ;
        RECT 11.360 53.440 11.900 53.940 ;
        RECT 1.160 71.640 1.700 72.140 ;
        RECT 9.660 71.640 10.200 72.140 ;
        RECT 13.060 59.940 13.600 60.440 ;
        RECT 7.295 54.785 7.350 55.195 ;
        RECT 10.695 58.685 10.750 59.095 ;
        RECT 11.050 58.685 11.105 59.095 ;
        RECT 12.395 58.685 12.450 59.095 ;
        RECT 12.750 58.685 12.805 59.095 ;
        RECT 9.660 66.440 10.200 66.940 ;
        RECT 0.850 65.185 0.905 65.595 ;
        RECT 2.195 65.185 2.250 65.595 ;
        RECT 3.895 63.885 3.950 64.295 ;
        RECT 4.250 63.885 4.305 64.295 ;
        RECT 5.595 63.885 5.650 64.295 ;
        RECT 0.850 52.185 0.905 52.595 ;
        RECT 2.550 65.185 2.605 65.595 ;
        RECT 5.595 65.185 5.650 65.595 ;
        RECT 5.950 65.185 6.005 65.595 ;
        RECT 2.860 61.240 3.400 61.740 ;
        RECT 0.495 54.785 0.550 55.195 ;
        RECT 0.850 54.785 0.905 55.195 ;
        RECT 2.195 54.785 2.250 55.195 ;
        RECT 2.550 54.785 2.605 55.195 ;
        RECT 4.560 61.240 5.100 61.740 ;
        RECT 0.495 67.785 0.550 68.195 ;
        RECT 0.850 67.785 0.905 68.195 ;
        RECT 2.195 67.785 2.250 68.195 ;
        RECT 2.550 67.785 2.605 68.195 ;
        RECT 10.695 67.785 10.750 68.195 ;
        RECT 2.860 59.940 3.400 60.440 ;
        RECT 6.260 59.940 6.800 60.440 ;
        RECT 9.660 59.940 10.200 60.440 ;
        RECT 11.360 59.940 11.900 60.440 ;
        RECT 11.050 67.785 11.105 68.195 ;
        RECT 22.595 61.285 22.650 61.695 ;
        RECT 19.860 58.640 20.400 59.140 ;
        RECT 14.760 54.740 15.300 55.240 ;
        RECT 19.860 54.740 20.400 55.240 ;
        RECT 22.950 61.285 23.005 61.695 ;
        RECT 17.495 52.185 17.550 52.595 ;
        RECT 17.850 52.185 17.905 52.595 ;
        RECT 21.250 54.785 21.305 55.195 ;
        RECT 20.895 61.285 20.950 61.695 ;
        RECT 14.095 53.485 14.150 53.895 ;
        RECT 21.250 61.285 21.305 61.695 ;
        RECT 15.795 62.585 15.850 62.995 ;
        RECT 16.150 62.585 16.205 62.995 ;
        RECT 20.895 65.185 20.950 65.595 ;
        RECT 21.250 65.185 21.305 65.595 ;
        RECT 22.595 65.185 22.650 65.595 ;
        RECT 22.950 65.185 23.005 65.595 ;
        RECT 20.895 62.585 20.950 62.995 ;
        RECT 17.495 70.385 17.550 70.795 ;
        RECT 17.850 70.385 17.905 70.795 ;
        RECT 22.595 70.385 22.650 70.795 ;
        RECT 22.950 70.385 23.005 70.795 ;
        RECT 21.250 62.585 21.305 62.995 ;
        RECT 15.795 59.985 15.850 60.395 ;
        RECT 16.150 59.985 16.205 60.395 ;
        RECT 21.250 50.885 21.305 51.295 ;
        RECT 20.895 58.685 20.950 59.095 ;
        RECT 21.250 58.685 21.305 59.095 ;
        RECT 25.995 58.685 26.050 59.095 ;
        RECT 24.295 50.885 24.350 51.295 ;
        RECT 14.760 66.440 15.300 66.940 ;
        RECT 21.560 70.340 22.100 70.840 ;
        RECT 26.350 58.685 26.405 59.095 ;
        RECT 23.260 54.740 23.800 55.240 ;
        RECT 24.960 54.740 25.500 55.240 ;
        RECT 24.960 63.840 25.500 64.340 ;
        RECT 20.895 56.085 20.950 56.495 ;
        RECT 25.995 65.185 26.050 65.595 ;
        RECT 14.450 53.485 14.505 53.895 ;
        RECT 19.195 53.485 19.250 53.895 ;
        RECT 19.550 53.485 19.605 53.895 ;
        RECT 26.350 65.185 26.405 65.595 ;
        RECT 26.350 50.885 26.405 51.295 ;
        RECT 14.760 52.140 15.300 52.640 ;
        RECT 26.660 52.140 27.200 52.640 ;
        RECT 21.250 56.085 21.305 56.495 ;
        RECT 14.760 65.140 15.300 65.640 ;
        RECT 22.595 53.485 22.650 53.895 ;
        RECT 22.950 53.485 23.005 53.895 ;
        RECT 16.460 65.140 17.000 65.640 ;
        RECT 17.495 50.885 17.550 51.295 ;
        RECT 17.495 71.685 17.550 72.095 ;
        RECT 17.850 71.685 17.905 72.095 ;
        RECT 20.895 71.685 20.950 72.095 ;
        RECT 21.250 71.685 21.305 72.095 ;
        RECT 26.660 54.740 27.200 55.240 ;
        RECT 16.460 53.440 17.000 53.940 ;
        RECT 26.660 53.440 27.200 53.940 ;
        RECT 16.460 49.540 17.000 50.040 ;
        RECT 18.160 65.140 18.700 65.640 ;
        RECT 18.160 59.940 18.700 60.440 ;
        RECT 14.760 71.640 15.300 72.140 ;
        RECT 24.960 71.640 25.500 72.140 ;
        RECT 26.660 71.640 27.200 72.140 ;
        RECT 14.760 62.540 15.300 63.040 ;
        RECT 14.095 67.785 14.150 68.195 ;
        RECT 14.450 67.785 14.505 68.195 ;
        RECT 24.650 50.885 24.705 51.295 ;
        RECT 25.995 50.885 26.050 51.295 ;
        RECT 16.460 61.240 17.000 61.740 ;
        RECT 24.960 61.240 25.500 61.740 ;
        RECT 26.660 61.240 27.200 61.740 ;
        RECT 20.895 54.785 20.950 55.195 ;
        RECT 19.195 67.785 19.250 68.195 ;
        RECT 19.550 67.785 19.605 68.195 ;
        RECT 22.595 67.785 22.650 68.195 ;
        RECT 22.950 67.785 23.005 68.195 ;
        RECT 24.295 67.785 24.350 68.195 ;
        RECT 24.650 67.785 24.705 68.195 ;
        RECT 23.260 62.540 23.800 63.040 ;
        RECT 24.960 62.540 25.500 63.040 ;
        RECT 18.160 49.540 18.700 50.040 ;
        RECT 19.860 49.540 20.400 50.040 ;
        RECT 26.660 62.540 27.200 63.040 ;
        RECT 17.850 50.885 17.905 51.295 ;
        RECT 25.995 67.785 26.050 68.195 ;
        RECT 26.350 67.785 26.405 68.195 ;
        RECT 20.895 49.585 20.950 49.995 ;
        RECT 21.250 49.585 21.305 49.995 ;
        RECT 20.895 50.885 20.950 51.295 ;
        RECT 19.860 59.940 20.400 60.440 ;
        RECT 16.460 56.040 17.000 56.540 ;
        RECT 19.860 56.040 20.400 56.540 ;
        RECT 18.160 67.740 18.700 68.240 ;
        RECT 24.960 56.040 25.500 56.540 ;
        RECT 14.760 58.640 15.300 59.140 ;
        RECT 18.160 58.640 18.700 59.140 ;
        RECT 26.660 59.940 27.200 60.440 ;
        RECT 14.760 37.840 15.300 38.340 ;
        RECT 18.160 37.840 18.700 38.340 ;
        RECT 14.095 39.185 14.150 39.595 ;
        RECT 14.450 39.185 14.505 39.595 ;
        RECT 20.895 39.185 20.950 39.595 ;
        RECT 21.250 39.185 21.305 39.595 ;
        RECT 25.995 39.185 26.050 39.595 ;
        RECT 26.350 39.185 26.405 39.595 ;
        RECT 18.160 39.140 18.700 39.640 ;
        RECT 19.860 39.140 20.400 39.640 ;
        RECT 23.260 39.140 23.800 39.640 ;
        RECT 14.760 40.440 15.300 40.940 ;
        RECT 18.160 40.440 18.700 40.940 ;
        RECT 21.560 40.440 22.100 40.940 ;
        RECT 20.895 41.785 20.950 42.195 ;
        RECT 21.250 41.785 21.305 42.195 ;
        RECT 19.860 41.740 20.400 42.240 ;
        RECT 24.960 41.740 25.500 42.240 ;
        RECT 26.660 41.740 27.200 42.240 ;
        RECT 22.595 43.085 22.650 43.495 ;
        RECT 22.950 43.085 23.005 43.495 ;
        RECT 25.995 43.085 26.050 43.495 ;
        RECT 26.350 43.085 26.405 43.495 ;
        RECT 19.860 43.040 20.400 43.540 ;
        RECT 21.560 43.040 22.100 43.540 ;
        RECT 22.595 44.385 22.650 44.795 ;
        RECT 22.950 44.385 23.005 44.795 ;
        RECT 16.460 44.340 17.000 44.840 ;
        RECT 19.860 44.340 20.400 44.840 ;
        RECT 21.560 44.340 22.100 44.840 ;
        RECT 17.495 46.985 17.550 47.395 ;
        RECT 17.850 46.985 17.905 47.395 ;
        RECT 22.595 46.985 22.650 47.395 ;
        RECT 22.950 46.985 23.005 47.395 ;
        RECT 18.160 24.840 18.700 25.340 ;
        RECT 24.960 24.840 25.500 25.340 ;
        RECT 26.660 24.840 27.200 25.340 ;
        RECT 15.795 26.185 15.850 26.595 ;
        RECT 16.150 26.185 16.205 26.595 ;
        RECT 17.495 26.185 17.550 26.595 ;
        RECT 17.850 26.185 17.905 26.595 ;
        RECT 24.295 26.185 24.350 26.595 ;
        RECT 24.650 26.185 24.705 26.595 ;
        RECT 21.560 26.140 22.100 26.640 ;
        RECT 23.260 26.140 23.800 26.640 ;
        RECT 14.095 27.485 14.150 27.895 ;
        RECT 14.450 27.485 14.505 27.895 ;
        RECT 15.795 27.485 15.850 27.895 ;
        RECT 16.150 27.485 16.205 27.895 ;
        RECT 17.495 27.485 17.550 27.895 ;
        RECT 17.850 27.485 17.905 27.895 ;
        RECT 19.195 27.485 19.250 27.895 ;
        RECT 19.550 27.485 19.605 27.895 ;
        RECT 21.560 27.440 22.100 27.940 ;
        RECT 15.795 28.785 15.850 29.195 ;
        RECT 16.150 28.785 16.205 29.195 ;
        RECT 17.495 28.785 17.550 29.195 ;
        RECT 17.850 28.785 17.905 29.195 ;
        RECT 20.895 28.785 20.950 29.195 ;
        RECT 21.250 28.785 21.305 29.195 ;
        RECT 22.595 28.785 22.650 29.195 ;
        RECT 22.950 28.785 23.005 29.195 ;
        RECT 24.960 28.740 25.500 29.240 ;
        RECT 14.095 30.085 14.150 30.495 ;
        RECT 14.450 30.085 14.505 30.495 ;
        RECT 25.995 30.085 26.050 30.495 ;
        RECT 26.350 30.085 26.405 30.495 ;
        RECT 16.460 30.040 17.000 30.540 ;
        RECT 19.860 30.040 20.400 30.540 ;
        RECT 17.495 31.385 17.550 31.795 ;
        RECT 17.850 31.385 17.905 31.795 ;
        RECT 25.995 31.385 26.050 31.795 ;
        RECT 26.350 31.385 26.405 31.795 ;
        RECT 24.960 31.340 25.500 31.840 ;
        RECT 14.760 32.640 15.300 33.140 ;
        RECT 21.560 32.640 22.100 33.140 ;
        RECT 18.160 35.240 18.700 35.740 ;
        RECT 21.560 35.240 22.100 35.740 ;
        RECT 26.660 35.240 27.200 35.740 ;
        RECT 17.495 36.585 17.550 36.995 ;
        RECT 17.850 36.585 17.905 36.995 ;
        RECT 21.560 36.540 22.100 37.040 ;
        RECT 23.260 36.540 23.800 37.040 ;
        RECT 24.295 37.885 24.350 38.295 ;
        RECT 24.650 37.885 24.705 38.295 ;
        RECT 25.995 37.885 26.050 38.295 ;
        RECT 26.350 37.885 26.405 38.295 ;
        RECT 7.960 39.140 8.500 39.640 ;
        RECT 8.995 39.185 9.050 39.595 ;
        RECT 9.350 39.185 9.405 39.595 ;
        RECT 7.960 43.040 8.500 43.540 ;
        RECT 13.060 43.040 13.600 43.540 ;
        RECT 10.695 40.485 10.750 40.895 ;
        RECT 10.695 44.385 10.750 44.795 ;
        RECT 11.050 44.385 11.105 44.795 ;
        RECT 12.395 44.385 12.450 44.795 ;
        RECT 12.750 44.385 12.805 44.795 ;
        RECT 11.050 40.485 11.105 40.895 ;
        RECT 9.660 44.340 10.200 44.840 ;
        RECT 9.660 40.440 10.200 40.940 ;
        RECT 10.695 46.985 10.750 47.395 ;
        RECT 11.050 46.985 11.105 47.395 ;
        RECT 12.395 46.985 12.450 47.395 ;
        RECT 12.750 46.985 12.805 47.395 ;
        RECT 7.960 46.940 8.500 47.440 ;
        RECT 9.660 46.940 10.200 47.440 ;
        RECT 7.295 36.585 7.350 36.995 ;
        RECT 7.650 36.585 7.705 36.995 ;
        RECT 9.660 41.740 10.200 42.240 ;
        RECT 13.060 37.840 13.600 38.340 ;
        RECT 0.495 44.385 0.550 44.795 ;
        RECT 0.850 39.185 0.905 39.595 ;
        RECT 2.195 39.185 2.250 39.595 ;
        RECT 5.595 46.985 5.650 47.395 ;
        RECT 5.950 46.985 6.005 47.395 ;
        RECT 0.850 44.385 0.905 44.795 ;
        RECT 5.595 40.485 5.650 40.895 ;
        RECT 4.560 43.040 5.100 43.540 ;
        RECT 0.495 39.185 0.550 39.595 ;
        RECT 2.550 39.185 2.605 39.595 ;
        RECT 2.195 41.785 2.250 42.195 ;
        RECT 2.550 41.785 2.605 42.195 ;
        RECT 3.895 39.185 3.950 39.595 ;
        RECT 2.195 40.485 2.250 40.895 ;
        RECT 5.950 40.485 6.005 40.895 ;
        RECT 4.250 39.185 4.305 39.595 ;
        RECT 0.495 36.585 0.550 36.995 ;
        RECT 0.850 36.585 0.905 36.995 ;
        RECT 2.195 36.585 2.250 36.995 ;
        RECT 2.550 36.585 2.605 36.995 ;
        RECT 5.595 36.585 5.650 36.995 ;
        RECT 5.950 36.585 6.005 36.995 ;
        RECT 4.560 40.440 5.100 40.940 ;
        RECT 2.860 44.340 3.400 44.840 ;
        RECT 1.160 41.740 1.700 42.240 ;
        RECT 4.560 44.340 5.100 44.840 ;
        RECT 5.595 37.885 5.650 38.295 ;
        RECT 5.950 37.885 6.005 38.295 ;
        RECT 1.160 37.840 1.700 38.340 ;
        RECT 4.560 37.840 5.100 38.340 ;
        RECT 2.550 40.485 2.605 40.895 ;
        RECT 0.850 28.785 0.905 29.195 ;
        RECT 6.260 28.740 6.800 29.240 ;
        RECT 3.895 28.785 3.950 29.195 ;
        RECT 6.260 32.640 6.800 33.140 ;
        RECT 0.495 30.085 0.550 30.495 ;
        RECT 2.195 35.285 2.250 35.695 ;
        RECT 2.550 35.285 2.605 35.695 ;
        RECT 1.160 35.240 1.700 35.740 ;
        RECT 6.260 35.240 6.800 35.740 ;
        RECT 2.860 24.840 3.400 25.340 ;
        RECT 0.850 30.085 0.905 30.495 ;
        RECT 2.195 30.085 2.250 30.495 ;
        RECT 2.550 30.085 2.605 30.495 ;
        RECT 5.595 30.085 5.650 30.495 ;
        RECT 5.950 30.085 6.005 30.495 ;
        RECT 4.250 28.785 4.305 29.195 ;
        RECT 1.160 26.140 1.700 26.640 ;
        RECT 2.195 27.485 2.250 27.895 ;
        RECT 1.160 27.440 1.700 27.940 ;
        RECT 4.560 30.040 5.100 30.540 ;
        RECT 4.560 27.440 5.100 27.940 ;
        RECT 3.895 26.185 3.950 26.595 ;
        RECT 4.250 26.185 4.305 26.595 ;
        RECT 6.260 27.440 6.800 27.940 ;
        RECT 3.895 31.385 3.950 31.795 ;
        RECT 4.250 31.385 4.305 31.795 ;
        RECT 2.550 27.485 2.605 27.895 ;
        RECT 0.495 28.785 0.550 29.195 ;
        RECT 8.995 35.285 9.050 35.695 ;
        RECT 9.350 35.285 9.405 35.695 ;
        RECT 7.295 28.785 7.350 29.195 ;
        RECT 7.650 28.785 7.705 29.195 ;
        RECT 7.960 35.240 8.500 35.740 ;
        RECT 11.360 35.240 11.900 35.740 ;
        RECT 7.650 24.885 7.705 25.295 ;
        RECT 7.295 31.385 7.350 31.795 ;
        RECT 7.650 31.385 7.705 31.795 ;
        RECT 12.395 31.385 12.450 31.795 ;
        RECT 12.750 31.385 12.805 31.795 ;
        RECT 7.295 30.085 7.350 30.495 ;
        RECT 7.650 30.085 7.705 30.495 ;
        RECT 10.695 27.485 10.750 27.895 ;
        RECT 13.060 28.740 13.600 29.240 ;
        RECT 11.360 31.340 11.900 31.840 ;
        RECT 11.050 27.485 11.105 27.895 ;
        RECT 7.295 32.685 7.350 33.095 ;
        RECT 7.650 32.685 7.705 33.095 ;
        RECT 10.695 32.685 10.750 33.095 ;
        RECT 11.050 32.685 11.105 33.095 ;
        RECT 7.960 26.140 8.500 26.640 ;
        RECT 11.360 26.140 11.900 26.640 ;
        RECT 8.995 26.185 9.050 26.595 ;
        RECT 9.350 26.185 9.405 26.595 ;
        RECT 12.395 26.185 12.450 26.595 ;
        RECT 12.750 26.185 12.805 26.595 ;
        RECT 7.295 24.885 7.350 25.295 ;
        RECT 7.295 27.485 7.350 27.895 ;
        RECT 7.650 27.485 7.705 27.895 ;
        RECT 0.495 11.885 0.550 12.295 ;
        RECT 0.850 11.885 0.905 12.295 ;
        RECT 2.195 11.885 2.250 12.295 ;
        RECT 2.550 11.885 2.605 12.295 ;
        RECT 10.695 11.885 10.750 12.295 ;
        RECT 11.050 11.885 11.105 12.295 ;
        RECT 12.395 11.885 12.450 12.295 ;
        RECT 12.750 11.885 12.805 12.295 ;
        RECT 12.750 23.585 12.805 23.995 ;
        RECT 11.360 23.540 11.900 24.040 ;
        RECT 7.295 23.585 7.350 23.995 ;
        RECT 7.650 23.585 7.705 23.995 ;
        RECT 12.395 23.585 12.450 23.995 ;
        RECT 7.295 13.185 7.350 13.595 ;
        RECT 7.650 13.185 7.705 13.595 ;
        RECT 8.995 13.185 9.050 13.595 ;
        RECT 9.350 13.185 9.405 13.595 ;
        RECT 10.695 13.185 10.750 13.595 ;
        RECT 11.050 13.185 11.105 13.595 ;
        RECT 13.060 13.140 13.600 13.640 ;
        RECT 7.295 14.485 7.350 14.895 ;
        RECT 7.650 14.485 7.705 14.895 ;
        RECT 8.995 15.785 9.050 16.195 ;
        RECT 9.350 15.785 9.405 16.195 ;
        RECT 13.060 15.740 13.600 16.240 ;
        RECT 12.395 17.085 12.450 17.495 ;
        RECT 12.750 17.085 12.805 17.495 ;
        RECT 7.960 17.040 8.500 17.540 ;
        RECT 11.360 17.040 11.900 17.540 ;
        RECT 9.660 18.340 10.200 18.840 ;
        RECT 7.295 19.685 7.350 20.095 ;
        RECT 7.650 19.685 7.705 20.095 ;
        RECT 11.360 19.640 11.900 20.140 ;
        RECT 8.995 20.985 9.050 21.395 ;
        RECT 9.350 20.985 9.405 21.395 ;
        RECT 12.395 20.985 12.450 21.395 ;
        RECT 12.750 20.985 12.805 21.395 ;
        RECT 2.860 20.940 3.400 21.440 ;
        RECT 5.595 13.185 5.650 13.595 ;
        RECT 5.950 13.185 6.005 13.595 ;
        RECT 0.495 17.085 0.550 17.495 ;
        RECT 0.850 17.085 0.905 17.495 ;
        RECT 5.595 17.085 5.650 17.495 ;
        RECT 5.950 17.085 6.005 17.495 ;
        RECT 1.160 13.140 1.700 13.640 ;
        RECT 4.560 13.140 5.100 13.640 ;
        RECT 6.260 20.940 6.800 21.440 ;
        RECT 0.495 14.485 0.550 14.895 ;
        RECT 0.495 18.385 0.550 18.795 ;
        RECT 0.850 18.385 0.905 18.795 ;
        RECT 2.195 18.385 2.250 18.795 ;
        RECT 2.550 18.385 2.605 18.795 ;
        RECT 0.850 14.485 0.905 14.895 ;
        RECT 0.495 19.685 0.550 20.095 ;
        RECT 0.850 19.685 0.905 20.095 ;
        RECT 2.195 19.685 2.250 20.095 ;
        RECT 2.550 19.685 2.605 20.095 ;
        RECT 3.895 19.685 3.950 20.095 ;
        RECT 4.250 19.685 4.305 20.095 ;
        RECT 5.595 19.685 5.650 20.095 ;
        RECT 5.950 19.685 6.005 20.095 ;
        RECT 2.860 23.540 3.400 24.040 ;
        RECT 4.560 23.540 5.100 24.040 ;
        RECT 6.260 14.440 6.800 14.940 ;
        RECT 0.495 20.985 0.550 21.395 ;
        RECT 0.850 20.985 0.905 21.395 ;
        RECT 0.495 15.785 0.550 16.195 ;
        RECT 0.850 15.785 0.905 16.195 ;
        RECT 3.895 15.785 3.950 16.195 ;
        RECT 4.250 15.785 4.305 16.195 ;
        RECT 0.850 9.285 0.905 9.695 ;
        RECT 5.595 9.285 5.650 9.695 ;
        RECT 5.950 9.285 6.005 9.695 ;
        RECT 0.495 0.185 0.550 0.595 ;
        RECT 0.850 0.185 0.905 0.595 ;
        RECT 2.860 0.140 3.400 0.640 ;
        RECT 4.560 0.140 5.100 0.640 ;
        RECT 2.195 1.485 2.250 1.895 ;
        RECT 2.550 1.485 2.605 1.895 ;
        RECT 5.595 1.485 5.650 1.895 ;
        RECT 5.950 1.485 6.005 1.895 ;
        RECT 1.160 1.440 1.700 1.940 ;
        RECT 4.560 1.440 5.100 1.940 ;
        RECT 0.495 2.785 0.550 3.195 ;
        RECT 0.850 2.785 0.905 3.195 ;
        RECT 2.195 2.785 2.250 3.195 ;
        RECT 2.550 2.785 2.605 3.195 ;
        RECT 4.560 2.740 5.100 3.240 ;
        RECT 2.195 4.085 2.250 4.495 ;
        RECT 2.550 4.085 2.605 4.495 ;
        RECT 5.595 4.085 5.650 4.495 ;
        RECT 5.950 4.085 6.005 4.495 ;
        RECT 0.495 5.385 0.550 5.795 ;
        RECT 0.850 5.385 0.905 5.795 ;
        RECT 3.895 5.385 3.950 5.795 ;
        RECT 4.250 5.385 4.305 5.795 ;
        RECT 5.595 5.385 5.650 5.795 ;
        RECT 5.950 5.385 6.005 5.795 ;
        RECT 1.160 6.640 1.700 7.140 ;
        RECT 6.260 6.640 6.800 7.140 ;
        RECT 6.260 7.940 6.800 8.440 ;
        RECT 0.495 9.285 0.550 9.695 ;
        RECT 11.050 9.285 11.105 9.695 ;
        RECT 12.395 4.085 12.450 4.495 ;
        RECT 12.750 4.085 12.805 4.495 ;
        RECT 9.660 4.040 10.200 4.540 ;
        RECT 7.650 0.185 7.705 0.595 ;
        RECT 7.295 1.485 7.350 1.895 ;
        RECT 7.650 1.485 7.705 1.895 ;
        RECT 7.295 2.785 7.350 3.195 ;
        RECT 7.650 2.785 7.705 3.195 ;
        RECT 12.395 2.785 12.450 3.195 ;
        RECT 8.995 5.385 9.050 5.795 ;
        RECT 9.350 5.385 9.405 5.795 ;
        RECT 10.695 5.385 10.750 5.795 ;
        RECT 11.050 5.385 11.105 5.795 ;
        RECT 12.395 5.385 12.450 5.795 ;
        RECT 12.750 5.385 12.805 5.795 ;
        RECT 7.960 5.340 8.500 5.840 ;
        RECT 8.995 6.685 9.050 7.095 ;
        RECT 9.350 6.685 9.405 7.095 ;
        RECT 12.750 2.785 12.805 3.195 ;
        RECT 8.995 1.485 9.050 1.895 ;
        RECT 7.960 6.640 8.500 7.140 ;
        RECT 12.395 7.985 12.450 8.395 ;
        RECT 12.750 7.985 12.805 8.395 ;
        RECT 9.660 2.740 10.200 3.240 ;
        RECT 9.660 7.940 10.200 8.440 ;
        RECT 9.350 1.485 9.405 1.895 ;
        RECT 12.395 0.185 12.450 0.595 ;
        RECT 12.750 0.185 12.805 0.595 ;
        RECT 7.295 0.185 7.350 0.595 ;
        RECT 10.695 9.285 10.750 9.695 ;
        RECT 14.760 11.840 15.300 12.340 ;
        RECT 21.250 17.085 21.305 17.495 ;
        RECT 24.295 17.085 24.350 17.495 ;
        RECT 24.650 17.085 24.705 17.495 ;
        RECT 20.895 18.385 20.950 18.795 ;
        RECT 21.250 18.385 21.305 18.795 ;
        RECT 20.895 17.085 20.950 17.495 ;
        RECT 20.895 19.685 20.950 20.095 ;
        RECT 21.250 19.685 21.305 20.095 ;
        RECT 24.295 19.685 24.350 20.095 ;
        RECT 24.650 19.685 24.705 20.095 ;
        RECT 26.660 19.640 27.200 20.140 ;
        RECT 22.595 20.985 22.650 21.395 ;
        RECT 22.950 20.985 23.005 21.395 ;
        RECT 24.960 20.940 25.500 21.440 ;
        RECT 26.660 20.940 27.200 21.440 ;
        RECT 26.660 13.140 27.200 13.640 ;
        RECT 22.595 23.585 22.650 23.995 ;
        RECT 22.950 23.585 23.005 23.995 ;
        RECT 21.560 23.540 22.100 24.040 ;
        RECT 24.960 23.540 25.500 24.040 ;
        RECT 26.660 23.540 27.200 24.040 ;
        RECT 20.895 14.485 20.950 14.895 ;
        RECT 21.250 14.485 21.305 14.895 ;
        RECT 25.995 14.485 26.050 14.895 ;
        RECT 26.350 14.485 26.405 14.895 ;
        RECT 20.895 15.785 20.950 16.195 ;
        RECT 21.250 15.785 21.305 16.195 ;
        RECT 24.295 15.785 24.350 16.195 ;
        RECT 24.650 15.785 24.705 16.195 ;
        RECT 23.260 15.740 23.800 16.240 ;
        RECT 19.860 18.340 20.400 18.840 ;
        RECT 14.095 18.385 14.150 18.795 ;
        RECT 14.095 19.685 14.150 20.095 ;
        RECT 14.095 23.585 14.150 23.995 ;
        RECT 14.450 23.585 14.505 23.995 ;
        RECT 19.195 23.585 19.250 23.995 ;
        RECT 19.550 23.585 19.605 23.995 ;
        RECT 14.450 19.685 14.505 20.095 ;
        RECT 14.450 18.385 14.505 18.795 ;
        RECT 14.095 14.485 14.150 14.895 ;
        RECT 14.450 14.485 14.505 14.895 ;
        RECT 16.460 23.540 17.000 24.040 ;
        RECT 15.795 18.385 15.850 18.795 ;
        RECT 16.150 18.385 16.205 18.795 ;
        RECT 17.495 18.385 17.550 18.795 ;
        RECT 19.195 14.485 19.250 14.895 ;
        RECT 19.550 14.485 19.605 14.895 ;
        RECT 16.460 19.640 17.000 20.140 ;
        RECT 18.160 19.640 18.700 20.140 ;
        RECT 19.860 19.640 20.400 20.140 ;
        RECT 17.850 18.385 17.905 18.795 ;
        RECT 18.160 14.440 18.700 14.940 ;
        RECT 19.195 15.785 19.250 16.195 ;
        RECT 19.550 15.785 19.605 16.195 ;
        RECT 19.195 17.085 19.250 17.495 ;
        RECT 19.550 17.085 19.605 17.495 ;
        RECT 14.760 13.140 15.300 13.640 ;
        RECT 18.160 20.940 18.700 21.440 ;
        RECT 19.860 20.940 20.400 21.440 ;
        RECT 16.150 5.385 16.205 5.795 ;
        RECT 18.160 0.140 18.700 0.640 ;
        RECT 15.795 6.685 15.850 7.095 ;
        RECT 17.495 9.285 17.550 9.695 ;
        RECT 17.850 9.285 17.905 9.695 ;
        RECT 14.450 0.185 14.505 0.595 ;
        RECT 14.095 2.785 14.150 3.195 ;
        RECT 16.460 2.740 17.000 3.240 ;
        RECT 14.450 2.785 14.505 3.195 ;
        RECT 16.150 6.685 16.205 7.095 ;
        RECT 19.195 4.085 19.250 4.495 ;
        RECT 18.160 6.640 18.700 7.140 ;
        RECT 18.160 2.740 18.700 3.240 ;
        RECT 18.160 4.040 18.700 4.540 ;
        RECT 19.195 0.185 19.250 0.595 ;
        RECT 19.550 0.185 19.605 0.595 ;
        RECT 15.795 5.385 15.850 5.795 ;
        RECT 14.095 0.185 14.150 0.595 ;
        RECT 17.495 1.485 17.550 1.895 ;
        RECT 19.550 4.085 19.605 4.495 ;
        RECT 17.850 1.485 17.905 1.895 ;
        RECT 23.260 9.240 23.800 9.740 ;
        RECT 26.660 5.340 27.200 5.840 ;
        RECT 26.660 2.740 27.200 3.240 ;
        RECT 21.560 1.440 22.100 1.940 ;
        RECT 21.560 7.940 22.100 8.440 ;
        RECT 22.595 2.785 22.650 3.195 ;
        RECT 22.950 2.785 23.005 3.195 ;
        RECT 21.560 6.640 22.100 7.140 ;
        RECT 24.650 1.485 24.705 1.895 ;
        RECT 22.950 5.385 23.005 5.795 ;
        RECT 22.595 7.985 22.650 8.395 ;
        RECT 22.950 7.985 23.005 8.395 ;
        RECT 24.960 4.040 25.500 4.540 ;
        RECT 21.560 9.240 22.100 9.740 ;
        RECT 20.895 5.385 20.950 5.795 ;
        RECT 21.250 5.385 21.305 5.795 ;
        RECT 22.595 5.385 22.650 5.795 ;
        RECT 24.295 5.385 24.350 5.795 ;
        RECT 24.650 5.385 24.705 5.795 ;
        RECT 26.660 4.040 27.200 4.540 ;
        RECT 24.295 1.485 24.350 1.895 ;
        RECT 47.060 27.440 47.600 27.940 ;
        RECT 48.760 27.440 49.300 27.940 ;
        RECT 46.395 28.785 46.450 29.195 ;
        RECT 46.750 28.785 46.805 29.195 ;
        RECT 51.495 28.785 51.550 29.195 ;
        RECT 51.850 28.785 51.905 29.195 ;
        RECT 41.960 28.740 42.500 29.240 ;
        RECT 48.760 28.740 49.300 29.240 ;
        RECT 41.295 30.085 41.350 30.495 ;
        RECT 41.650 30.085 41.705 30.495 ;
        RECT 48.095 30.085 48.150 30.495 ;
        RECT 48.450 30.085 48.505 30.495 ;
        RECT 49.795 30.085 49.850 30.495 ;
        RECT 50.150 30.085 50.205 30.495 ;
        RECT 53.195 30.085 53.250 30.495 ;
        RECT 53.550 30.085 53.605 30.495 ;
        RECT 43.660 30.040 44.200 30.540 ;
        RECT 52.160 30.040 52.700 30.540 ;
        RECT 48.095 31.385 48.150 31.795 ;
        RECT 48.450 31.385 48.505 31.795 ;
        RECT 53.195 31.385 53.250 31.795 ;
        RECT 53.550 31.385 53.605 31.795 ;
        RECT 52.160 31.340 52.700 31.840 ;
        RECT 53.195 32.685 53.250 33.095 ;
        RECT 53.550 32.685 53.605 33.095 ;
        RECT 41.960 32.640 42.500 33.140 ;
        RECT 45.360 32.640 45.900 33.140 ;
        RECT 44.695 35.285 44.750 35.695 ;
        RECT 45.050 35.285 45.105 35.695 ;
        RECT 53.860 35.240 54.400 35.740 ;
        RECT 41.295 36.585 41.350 36.995 ;
        RECT 41.650 36.585 41.705 36.995 ;
        RECT 44.695 36.585 44.750 36.995 ;
        RECT 45.050 36.585 45.105 36.995 ;
        RECT 49.795 36.585 49.850 36.995 ;
        RECT 50.150 36.585 50.205 36.995 ;
        RECT 53.860 36.540 54.400 37.040 ;
        RECT 41.960 37.840 42.500 38.340 ;
        RECT 45.360 37.840 45.900 38.340 ;
        RECT 52.160 37.840 52.700 38.340 ;
        RECT 53.860 37.840 54.400 38.340 ;
        RECT 44.695 39.185 44.750 39.595 ;
        RECT 45.050 39.185 45.105 39.595 ;
        RECT 53.195 39.185 53.250 39.595 ;
        RECT 53.550 39.185 53.605 39.595 ;
        RECT 41.960 39.140 42.500 39.640 ;
        RECT 50.460 39.140 51.000 39.640 ;
        RECT 41.295 40.485 41.350 40.895 ;
        RECT 41.650 40.485 41.705 40.895 ;
        RECT 42.995 40.485 43.050 40.895 ;
        RECT 43.350 40.485 43.405 40.895 ;
        RECT 47.060 40.440 47.600 40.940 ;
        RECT 50.460 40.440 51.000 40.940 ;
        RECT 52.160 40.440 52.700 40.940 ;
        RECT 53.860 40.440 54.400 40.940 ;
        RECT 42.995 41.785 43.050 42.195 ;
        RECT 43.350 41.785 43.405 42.195 ;
        RECT 48.760 41.740 49.300 42.240 ;
        RECT 50.460 41.740 51.000 42.240 ;
        RECT 41.295 43.085 41.350 43.495 ;
        RECT 41.650 43.085 41.705 43.495 ;
        RECT 46.395 43.085 46.450 43.495 ;
        RECT 46.750 43.085 46.805 43.495 ;
        RECT 48.095 43.085 48.150 43.495 ;
        RECT 48.450 43.085 48.505 43.495 ;
        RECT 49.795 43.085 49.850 43.495 ;
        RECT 50.150 43.085 50.205 43.495 ;
        RECT 45.360 43.040 45.900 43.540 ;
        RECT 53.860 43.040 54.400 43.540 ;
        RECT 41.295 44.385 41.350 44.795 ;
        RECT 41.650 44.385 41.705 44.795 ;
        RECT 48.095 44.385 48.150 44.795 ;
        RECT 48.450 44.385 48.505 44.795 ;
        RECT 52.160 44.340 52.700 44.840 ;
        RECT 41.295 24.885 41.350 25.295 ;
        RECT 41.650 24.885 41.705 25.295 ;
        RECT 42.995 46.985 43.050 47.395 ;
        RECT 43.350 46.985 43.405 47.395 ;
        RECT 44.695 46.985 44.750 47.395 ;
        RECT 45.050 46.985 45.105 47.395 ;
        RECT 44.695 24.885 44.750 25.295 ;
        RECT 45.050 24.885 45.105 25.295 ;
        RECT 48.760 46.940 49.300 47.440 ;
        RECT 50.460 46.940 51.000 47.440 ;
        RECT 53.195 24.885 53.250 25.295 ;
        RECT 53.550 24.885 53.605 25.295 ;
        RECT 43.660 24.840 44.200 25.340 ;
        RECT 48.760 24.840 49.300 25.340 ;
        RECT 50.460 24.840 51.000 25.340 ;
        RECT 42.995 26.185 43.050 26.595 ;
        RECT 43.350 26.185 43.405 26.595 ;
        RECT 44.695 26.185 44.750 26.595 ;
        RECT 45.050 26.185 45.105 26.595 ;
        RECT 47.060 26.140 47.600 26.640 ;
        RECT 52.160 26.140 52.700 26.640 ;
        RECT 45.360 27.440 45.900 27.940 ;
        RECT 38.250 41.785 38.305 42.195 ;
        RECT 39.595 41.785 39.650 42.195 ;
        RECT 39.950 41.785 40.005 42.195 ;
        RECT 29.750 28.785 29.805 29.195 ;
        RECT 28.360 30.040 28.900 30.540 ;
        RECT 40.260 31.340 40.800 31.840 ;
        RECT 36.860 30.040 37.400 30.540 ;
        RECT 29.395 43.085 29.450 43.495 ;
        RECT 29.750 43.085 29.805 43.495 ;
        RECT 37.895 43.085 37.950 43.495 ;
        RECT 38.250 43.085 38.305 43.495 ;
        RECT 40.260 36.540 40.800 37.040 ;
        RECT 32.795 32.685 32.850 33.095 ;
        RECT 28.360 37.840 28.900 38.340 ;
        RECT 38.560 37.840 39.100 38.340 ;
        RECT 33.150 32.685 33.205 33.095 ;
        RECT 40.260 30.040 40.800 30.540 ;
        RECT 37.895 30.085 37.950 30.495 ;
        RECT 38.560 32.640 39.100 33.140 ;
        RECT 31.760 43.040 32.300 43.540 ;
        RECT 33.460 43.040 34.000 43.540 ;
        RECT 35.160 43.040 35.700 43.540 ;
        RECT 29.395 39.185 29.450 39.595 ;
        RECT 29.750 39.185 29.805 39.595 ;
        RECT 27.695 44.385 27.750 44.795 ;
        RECT 28.050 44.385 28.105 44.795 ;
        RECT 36.195 44.385 36.250 44.795 ;
        RECT 36.550 44.385 36.605 44.795 ;
        RECT 31.095 39.185 31.150 39.595 ;
        RECT 31.450 39.185 31.505 39.595 ;
        RECT 38.250 30.085 38.305 30.495 ;
        RECT 32.795 31.385 32.850 31.795 ;
        RECT 38.560 44.340 39.100 44.840 ;
        RECT 40.260 44.340 40.800 44.840 ;
        RECT 32.795 35.285 32.850 35.695 ;
        RECT 34.495 24.885 34.550 25.295 ;
        RECT 34.850 24.885 34.905 25.295 ;
        RECT 39.595 24.885 39.650 25.295 ;
        RECT 39.950 24.885 40.005 25.295 ;
        RECT 33.150 35.285 33.205 35.695 ;
        RECT 36.860 39.140 37.400 39.640 ;
        RECT 31.095 46.985 31.150 47.395 ;
        RECT 31.450 46.985 31.505 47.395 ;
        RECT 32.795 46.985 32.850 47.395 ;
        RECT 33.150 46.985 33.205 47.395 ;
        RECT 39.595 46.985 39.650 47.395 ;
        RECT 39.950 46.985 40.005 47.395 ;
        RECT 33.150 31.385 33.205 31.795 ;
        RECT 34.495 31.385 34.550 31.795 ;
        RECT 40.260 35.240 40.800 35.740 ;
        RECT 34.850 31.385 34.905 31.795 ;
        RECT 36.195 36.585 36.250 36.995 ;
        RECT 36.550 36.585 36.605 36.995 ;
        RECT 35.160 46.940 35.700 47.440 ;
        RECT 28.360 40.440 28.900 40.940 ;
        RECT 30.060 40.440 30.600 40.940 ;
        RECT 35.160 40.440 35.700 40.940 ;
        RECT 36.860 40.440 37.400 40.940 ;
        RECT 36.860 24.840 37.400 25.340 ;
        RECT 38.560 40.440 39.100 40.940 ;
        RECT 37.895 36.585 37.950 36.995 ;
        RECT 38.250 36.585 38.305 36.995 ;
        RECT 27.695 26.185 27.750 26.595 ;
        RECT 28.050 26.185 28.105 26.595 ;
        RECT 36.195 26.185 36.250 26.595 ;
        RECT 36.550 26.185 36.605 26.595 ;
        RECT 33.460 28.740 34.000 29.240 ;
        RECT 29.395 28.785 29.450 29.195 ;
        RECT 29.395 41.785 29.450 42.195 ;
        RECT 29.750 41.785 29.805 42.195 ;
        RECT 30.060 26.140 30.600 26.640 ;
        RECT 35.160 26.140 35.700 26.640 ;
        RECT 32.795 41.785 32.850 42.195 ;
        RECT 33.150 41.785 33.205 42.195 ;
        RECT 27.695 27.485 27.750 27.895 ;
        RECT 28.050 27.485 28.105 27.895 ;
        RECT 37.895 27.485 37.950 27.895 ;
        RECT 38.250 27.485 38.305 27.895 ;
        RECT 40.260 27.440 40.800 27.940 ;
        RECT 37.895 41.785 37.950 42.195 ;
        RECT 31.450 23.585 31.505 23.995 ;
        RECT 36.860 11.840 37.400 12.340 ;
        RECT 34.850 7.985 34.905 8.395 ;
        RECT 36.195 1.485 36.250 1.895 ;
        RECT 39.950 9.285 40.005 9.695 ;
        RECT 30.060 18.340 30.600 18.840 ;
        RECT 34.495 5.385 34.550 5.795 ;
        RECT 34.850 5.385 34.905 5.795 ;
        RECT 36.550 1.485 36.605 1.895 ;
        RECT 35.160 4.040 35.700 4.540 ;
        RECT 28.360 15.740 28.900 16.240 ;
        RECT 35.160 15.740 35.700 16.240 ;
        RECT 39.595 20.985 39.650 21.395 ;
        RECT 39.950 20.985 40.005 21.395 ;
        RECT 33.150 2.785 33.205 3.195 ;
        RECT 37.895 2.785 37.950 3.195 ;
        RECT 36.195 5.385 36.250 5.795 ;
        RECT 36.550 5.385 36.605 5.795 ;
        RECT 36.860 13.140 37.400 13.640 ;
        RECT 38.560 13.140 39.100 13.640 ;
        RECT 35.160 23.540 35.700 24.040 ;
        RECT 28.360 9.240 28.900 9.740 ;
        RECT 35.160 1.440 35.700 1.940 ;
        RECT 36.860 2.740 37.400 3.240 ;
        RECT 40.260 23.540 40.800 24.040 ;
        RECT 36.550 0.185 36.605 0.595 ;
        RECT 40.260 15.740 40.800 16.240 ;
        RECT 34.495 7.985 34.550 8.395 ;
        RECT 31.760 9.240 32.300 9.740 ;
        RECT 38.250 2.785 38.305 3.195 ;
        RECT 33.460 20.940 34.000 21.440 ;
        RECT 36.860 20.940 37.400 21.440 ;
        RECT 38.560 20.940 39.100 21.440 ;
        RECT 39.595 2.785 39.650 3.195 ;
        RECT 39.950 2.785 40.005 3.195 ;
        RECT 36.195 0.185 36.250 0.595 ;
        RECT 27.695 17.085 27.750 17.495 ;
        RECT 28.050 17.085 28.105 17.495 ;
        RECT 32.795 17.085 32.850 17.495 ;
        RECT 33.150 17.085 33.205 17.495 ;
        RECT 31.450 0.185 31.505 0.595 ;
        RECT 39.595 17.085 39.650 17.495 ;
        RECT 36.860 17.040 37.400 17.540 ;
        RECT 32.795 2.785 32.850 3.195 ;
        RECT 39.595 9.285 39.650 9.695 ;
        RECT 27.695 18.385 27.750 18.795 ;
        RECT 31.095 19.685 31.150 20.095 ;
        RECT 31.450 19.685 31.505 20.095 ;
        RECT 28.050 18.385 28.105 18.795 ;
        RECT 37.895 0.185 37.950 0.595 ;
        RECT 33.460 5.340 34.000 5.840 ;
        RECT 38.560 5.340 39.100 5.840 ;
        RECT 38.560 17.040 39.100 17.540 ;
        RECT 32.795 19.685 32.850 20.095 ;
        RECT 33.150 19.685 33.205 20.095 ;
        RECT 27.695 5.385 27.750 5.795 ;
        RECT 38.250 0.185 38.305 0.595 ;
        RECT 31.095 0.185 31.150 0.595 ;
        RECT 31.095 1.485 31.150 1.895 ;
        RECT 36.195 14.485 36.250 14.895 ;
        RECT 36.550 14.485 36.605 14.895 ;
        RECT 31.450 1.485 31.505 1.895 ;
        RECT 34.495 6.685 34.550 7.095 ;
        RECT 39.595 19.685 39.650 20.095 ;
        RECT 39.950 19.685 40.005 20.095 ;
        RECT 28.050 5.385 28.105 5.795 ;
        RECT 27.695 23.585 27.750 23.995 ;
        RECT 27.695 11.885 27.750 12.295 ;
        RECT 28.050 11.885 28.105 12.295 ;
        RECT 39.595 11.885 39.650 12.295 ;
        RECT 39.950 17.085 40.005 17.495 ;
        RECT 34.850 6.685 34.905 7.095 ;
        RECT 36.195 6.685 36.250 7.095 ;
        RECT 36.550 6.685 36.605 7.095 ;
        RECT 33.460 7.940 34.000 8.440 ;
        RECT 36.860 7.940 37.400 8.440 ;
        RECT 36.195 18.385 36.250 18.795 ;
        RECT 36.550 18.385 36.605 18.795 ;
        RECT 32.795 4.085 32.850 4.495 ;
        RECT 33.150 4.085 33.205 4.495 ;
        RECT 30.060 6.640 30.600 7.140 ;
        RECT 29.395 15.785 29.450 16.195 ;
        RECT 29.750 15.785 29.805 16.195 ;
        RECT 31.095 15.785 31.150 16.195 ;
        RECT 31.450 15.785 31.505 16.195 ;
        RECT 36.195 15.785 36.250 16.195 ;
        RECT 36.550 15.785 36.605 16.195 ;
        RECT 30.060 17.040 30.600 17.540 ;
        RECT 39.950 11.885 40.005 12.295 ;
        RECT 28.360 19.640 28.900 20.140 ;
        RECT 35.160 19.640 35.700 20.140 ;
        RECT 28.050 23.585 28.105 23.995 ;
        RECT 31.095 23.585 31.150 23.995 ;
        RECT 49.795 4.085 49.850 4.495 ;
        RECT 45.360 20.940 45.900 21.440 ;
        RECT 48.760 20.940 49.300 21.440 ;
        RECT 49.795 5.385 49.850 5.795 ;
        RECT 41.960 18.340 42.500 18.840 ;
        RECT 42.995 19.685 43.050 20.095 ;
        RECT 43.350 19.685 43.405 20.095 ;
        RECT 53.195 19.685 53.250 20.095 ;
        RECT 53.550 19.685 53.605 20.095 ;
        RECT 47.060 23.540 47.600 24.040 ;
        RECT 50.150 5.385 50.205 5.795 ;
        RECT 41.650 9.285 41.705 9.695 ;
        RECT 48.095 9.285 48.150 9.695 ;
        RECT 48.450 9.285 48.505 9.695 ;
        RECT 41.960 17.040 42.500 17.540 ;
        RECT 52.160 20.940 52.700 21.440 ;
        RECT 53.860 20.940 54.400 21.440 ;
        RECT 53.860 1.440 54.400 1.940 ;
        RECT 53.860 0.140 54.400 0.640 ;
        RECT 53.860 4.040 54.400 4.540 ;
        RECT 45.050 7.985 45.105 8.395 ;
        RECT 48.095 7.985 48.150 8.395 ;
        RECT 48.450 7.985 48.505 8.395 ;
        RECT 48.450 15.785 48.505 16.195 ;
        RECT 43.660 9.240 44.200 9.740 ;
        RECT 49.795 11.885 49.850 12.295 ;
        RECT 53.860 6.640 54.400 7.140 ;
        RECT 45.360 17.040 45.900 17.540 ;
        RECT 47.060 19.640 47.600 20.140 ;
        RECT 52.160 19.640 52.700 20.140 ;
        RECT 48.095 13.185 48.150 13.595 ;
        RECT 48.450 13.185 48.505 13.595 ;
        RECT 49.795 13.185 49.850 13.595 ;
        RECT 50.150 13.185 50.205 13.595 ;
        RECT 50.150 11.885 50.205 12.295 ;
        RECT 51.495 11.885 51.550 12.295 ;
        RECT 51.495 13.185 51.550 13.595 ;
        RECT 51.850 13.185 51.905 13.595 ;
        RECT 45.360 5.340 45.900 5.840 ;
        RECT 51.850 11.885 51.905 12.295 ;
        RECT 53.195 11.885 53.250 12.295 ;
        RECT 53.550 11.885 53.605 12.295 ;
        RECT 45.360 0.140 45.900 0.640 ;
        RECT 48.760 5.340 49.300 5.840 ;
        RECT 53.860 5.340 54.400 5.840 ;
        RECT 47.060 17.040 47.600 17.540 ;
        RECT 47.060 11.840 47.600 12.340 ;
        RECT 42.995 2.785 43.050 3.195 ;
        RECT 43.350 2.785 43.405 3.195 ;
        RECT 53.195 2.785 53.250 3.195 ;
        RECT 49.795 14.485 49.850 14.895 ;
        RECT 50.150 14.485 50.205 14.895 ;
        RECT 53.550 2.785 53.605 3.195 ;
        RECT 47.060 7.940 47.600 8.440 ;
        RECT 41.960 14.440 42.500 14.940 ;
        RECT 50.460 7.940 51.000 8.440 ;
        RECT 52.160 7.940 52.700 8.440 ;
        RECT 44.695 7.985 44.750 8.395 ;
        RECT 50.150 4.085 50.205 4.495 ;
        RECT 46.395 1.485 46.450 1.895 ;
        RECT 41.295 20.985 41.350 21.395 ;
        RECT 41.295 23.585 41.350 23.995 ;
        RECT 41.650 23.585 41.705 23.995 ;
        RECT 41.650 20.985 41.705 21.395 ;
        RECT 42.995 18.385 43.050 18.795 ;
        RECT 46.750 1.485 46.805 1.895 ;
        RECT 41.295 6.685 41.350 7.095 ;
        RECT 41.650 6.685 41.705 7.095 ;
        RECT 51.495 4.085 51.550 4.495 ;
        RECT 48.760 11.840 49.300 12.340 ;
        RECT 48.095 23.585 48.150 23.995 ;
        RECT 48.450 23.585 48.505 23.995 ;
        RECT 51.495 23.585 51.550 23.995 ;
        RECT 51.850 23.585 51.905 23.995 ;
        RECT 44.695 4.085 44.750 4.495 ;
        RECT 45.050 4.085 45.105 4.495 ;
        RECT 46.395 4.085 46.450 4.495 ;
        RECT 53.195 23.585 53.250 23.995 ;
        RECT 47.060 6.640 47.600 7.140 ;
        RECT 53.550 23.585 53.605 23.995 ;
        RECT 51.850 4.085 51.905 4.495 ;
        RECT 45.360 1.440 45.900 1.940 ;
        RECT 48.760 1.440 49.300 1.940 ;
        RECT 43.350 18.385 43.405 18.795 ;
        RECT 45.360 2.740 45.900 3.240 ;
        RECT 41.295 15.785 41.350 16.195 ;
        RECT 46.750 4.085 46.805 4.495 ;
        RECT 41.295 9.285 41.350 9.695 ;
        RECT 43.660 15.740 44.200 16.240 ;
        RECT 53.860 15.740 54.400 16.240 ;
        RECT 41.650 15.785 41.705 16.195 ;
        RECT 46.395 15.785 46.450 16.195 ;
        RECT 46.750 15.785 46.805 16.195 ;
        RECT 48.095 15.785 48.150 16.195 ;
        RECT 48.095 4.085 48.150 4.495 ;
        RECT 48.450 4.085 48.505 4.495 ;
      LAYER met4 ;
        RECT 30.060 71.640 30.300 72.140 ;
        RECT 33.460 71.640 33.700 72.140 ;
        RECT 35.160 71.640 35.400 72.140 ;
        RECT 43.660 71.640 43.900 72.140 ;
        RECT 45.360 71.640 45.600 72.140 ;
        RECT 47.060 71.640 47.300 72.140 ;
        RECT 48.760 72.940 49.000 73.440 ;
        RECT 50.460 72.940 50.700 73.440 ;
        RECT 45.360 74.240 45.600 74.740 ;
        RECT 50.460 74.240 50.700 74.740 ;
        RECT 52.160 74.240 52.400 74.740 ;
        RECT 45.360 75.540 45.600 76.040 ;
        RECT 47.060 75.540 47.300 76.040 ;
        RECT 50.460 75.540 50.700 76.040 ;
        RECT 47.060 76.840 47.300 77.340 ;
        RECT 52.160 76.840 52.400 77.340 ;
        RECT 43.660 78.140 43.900 78.640 ;
        RECT 47.060 78.140 47.300 78.640 ;
        RECT 48.760 78.140 49.000 78.640 ;
        RECT 52.160 78.140 52.400 78.640 ;
        RECT 48.760 79.440 49.000 79.940 ;
        RECT 52.160 79.440 52.400 79.940 ;
        RECT 53.860 79.440 54.100 79.940 ;
        RECT 41.960 82.040 42.200 82.540 ;
        RECT 43.660 82.040 43.900 82.540 ;
        RECT 47.060 83.340 47.300 83.840 ;
        RECT 48.760 83.340 49.000 83.840 ;
        RECT 53.860 83.340 54.100 83.840 ;
        RECT 43.660 84.640 43.900 85.140 ;
        RECT 45.360 85.940 45.600 86.440 ;
        RECT 53.860 87.240 54.100 87.740 ;
        RECT 45.360 88.540 45.600 89.040 ;
        RECT 47.060 88.540 47.300 89.040 ;
        RECT 48.760 88.540 49.000 89.040 ;
        RECT 50.460 88.540 50.700 89.040 ;
        RECT 43.660 89.840 43.900 90.340 ;
        RECT 52.160 89.840 52.400 90.340 ;
        RECT 53.860 89.840 54.100 90.340 ;
        RECT 41.960 91.140 42.200 91.640 ;
        RECT 42.000 95.160 42.200 95.660 ;
        RECT 43.700 95.160 43.900 95.660 ;
        RECT 45.400 95.160 45.600 95.660 ;
        RECT 47.100 95.160 47.300 95.660 ;
        RECT 48.800 95.160 49.000 95.660 ;
        RECT 50.500 95.160 50.700 95.660 ;
        RECT 52.200 95.160 52.400 95.660 ;
        RECT 53.900 95.160 54.100 95.660 ;
        RECT 33.460 84.640 33.700 85.140 ;
        RECT 33.460 75.540 33.700 76.040 ;
        RECT 33.460 85.940 33.700 86.440 ;
        RECT 40.260 85.940 40.500 86.440 ;
        RECT 35.160 75.540 35.400 76.040 ;
        RECT 30.060 87.240 30.300 87.740 ;
        RECT 31.760 87.240 32.000 87.740 ;
        RECT 36.860 74.240 37.100 74.740 ;
        RECT 31.760 88.540 32.000 89.040 ;
        RECT 36.860 88.540 37.100 89.040 ;
        RECT 31.760 79.440 32.000 79.940 ;
        RECT 35.160 79.440 35.400 79.940 ;
        RECT 40.260 74.240 40.500 74.740 ;
        RECT 38.560 72.940 38.800 73.440 ;
        RECT 38.560 89.840 38.800 90.340 ;
        RECT 35.160 76.840 35.400 77.340 ;
        RECT 30.060 82.040 30.300 82.540 ;
        RECT 33.460 72.940 33.700 73.440 ;
        RECT 33.460 91.140 33.700 91.640 ;
        RECT 35.160 91.140 35.400 91.640 ;
        RECT 35.160 72.940 35.400 73.440 ;
        RECT 28.400 95.160 28.600 95.660 ;
        RECT 30.100 95.160 30.300 95.660 ;
        RECT 31.800 95.160 32.000 95.660 ;
        RECT 33.500 95.160 33.700 95.660 ;
        RECT 35.200 95.160 35.400 95.660 ;
        RECT 36.900 95.160 37.100 95.660 ;
        RECT 38.600 95.160 38.800 95.660 ;
        RECT 40.300 95.160 40.500 95.660 ;
        RECT 28.360 83.340 28.600 83.840 ;
        RECT 35.160 83.340 35.400 83.840 ;
        RECT 36.860 83.340 37.100 83.840 ;
        RECT 38.560 83.340 38.800 83.840 ;
        RECT 28.360 78.140 28.600 78.640 ;
        RECT 35.160 78.140 35.400 78.640 ;
        RECT 28.360 75.540 28.600 76.040 ;
        RECT 31.760 84.640 32.000 85.140 ;
        RECT 28.360 65.140 28.600 65.640 ;
        RECT 30.060 65.140 30.300 65.640 ;
        RECT 35.160 65.140 35.400 65.640 ;
        RECT 36.860 65.140 37.100 65.640 ;
        RECT 28.360 66.440 28.600 66.940 ;
        RECT 35.160 66.440 35.400 66.940 ;
        RECT 38.560 66.440 38.800 66.940 ;
        RECT 40.260 66.440 40.500 66.940 ;
        RECT 30.060 67.740 30.300 68.240 ;
        RECT 35.160 67.740 35.400 68.240 ;
        RECT 38.560 67.740 38.800 68.240 ;
        RECT 38.560 70.340 38.800 70.840 ;
        RECT 38.560 48.240 38.800 48.740 ;
        RECT 40.260 48.240 40.500 48.740 ;
        RECT 35.160 49.540 35.400 50.040 ;
        RECT 31.760 50.840 32.000 51.340 ;
        RECT 28.360 52.140 28.600 52.640 ;
        RECT 30.060 52.140 30.300 52.640 ;
        RECT 35.160 53.440 35.400 53.940 ;
        RECT 40.260 53.440 40.500 53.940 ;
        RECT 30.060 54.740 30.300 55.240 ;
        RECT 38.560 58.640 38.800 59.140 ;
        RECT 40.260 58.640 40.500 59.140 ;
        RECT 31.760 59.940 32.000 60.440 ;
        RECT 40.260 59.940 40.500 60.440 ;
        RECT 28.360 61.240 28.600 61.740 ;
        RECT 31.760 61.240 32.000 61.740 ;
        RECT 38.560 61.240 38.800 61.740 ;
        RECT 31.760 62.540 32.000 63.040 ;
        RECT 30.060 63.840 30.300 64.340 ;
        RECT 33.460 63.840 33.700 64.340 ;
        RECT 36.860 63.840 37.100 64.340 ;
        RECT 50.460 63.840 50.700 64.340 ;
        RECT 53.860 50.840 54.100 51.340 ;
        RECT 41.960 48.240 42.200 48.740 ;
        RECT 41.960 58.640 42.200 59.140 ;
        RECT 50.460 49.540 50.700 50.040 ;
        RECT 45.360 65.140 45.600 65.640 ;
        RECT 50.460 65.140 50.700 65.640 ;
        RECT 47.060 52.140 47.300 52.640 ;
        RECT 41.960 59.940 42.200 60.440 ;
        RECT 50.460 59.940 50.700 60.440 ;
        RECT 53.860 59.940 54.100 60.440 ;
        RECT 41.960 66.440 42.200 66.940 ;
        RECT 43.660 66.440 43.900 66.940 ;
        RECT 53.860 48.240 54.100 48.740 ;
        RECT 45.360 50.840 45.600 51.340 ;
        RECT 41.960 53.440 42.200 53.940 ;
        RECT 41.960 67.740 42.200 68.240 ;
        RECT 43.660 67.740 43.900 68.240 ;
        RECT 53.860 67.740 54.100 68.240 ;
        RECT 48.760 61.240 49.000 61.740 ;
        RECT 48.760 50.840 49.000 51.340 ;
        RECT 53.860 62.540 54.100 63.040 ;
        RECT 48.760 54.740 49.000 55.240 ;
        RECT 43.660 56.040 43.900 56.540 ;
        RECT 45.360 56.040 45.600 56.540 ;
        RECT 45.360 63.840 45.600 64.340 ;
        RECT 1.160 71.640 1.400 72.140 ;
        RECT 9.660 71.640 9.900 72.140 ;
        RECT 14.760 71.640 15.000 72.140 ;
        RECT 24.960 71.640 25.200 72.140 ;
        RECT 26.660 71.640 26.900 72.140 ;
        RECT 16.460 76.840 16.700 77.340 ;
        RECT 23.260 76.840 23.500 77.340 ;
        RECT 24.960 76.840 25.200 77.340 ;
        RECT 14.760 78.140 15.000 78.640 ;
        RECT 16.460 78.140 16.700 78.640 ;
        RECT 26.660 78.140 26.900 78.640 ;
        RECT 18.160 79.440 18.400 79.940 ;
        RECT 23.260 79.440 23.500 79.940 ;
        RECT 14.760 82.040 15.000 82.540 ;
        RECT 16.460 82.040 16.700 82.540 ;
        RECT 21.560 82.040 21.800 82.540 ;
        RECT 21.560 83.340 21.800 83.840 ;
        RECT 23.260 83.340 23.500 83.840 ;
        RECT 24.960 84.640 25.200 85.140 ;
        RECT 14.760 85.940 15.000 86.440 ;
        RECT 18.160 85.940 18.400 86.440 ;
        RECT 16.460 87.240 16.700 87.740 ;
        RECT 21.560 87.240 21.800 87.740 ;
        RECT 24.960 87.240 25.200 87.740 ;
        RECT 26.660 87.240 26.900 87.740 ;
        RECT 23.260 88.540 23.500 89.040 ;
        RECT 24.960 88.540 25.200 89.040 ;
        RECT 26.660 88.540 26.900 89.040 ;
        RECT 16.460 89.840 16.700 90.340 ;
        RECT 24.960 89.840 25.200 90.340 ;
        RECT 16.460 91.140 16.700 91.640 ;
        RECT 14.760 74.240 15.000 74.740 ;
        RECT 14.800 95.160 15.000 95.660 ;
        RECT 16.500 95.160 16.700 95.660 ;
        RECT 18.200 95.160 18.400 95.660 ;
        RECT 19.900 95.160 20.100 95.660 ;
        RECT 21.600 95.160 21.800 95.660 ;
        RECT 23.300 95.160 23.500 95.660 ;
        RECT 25.000 95.160 25.200 95.660 ;
        RECT 26.700 95.160 26.900 95.660 ;
        RECT 18.160 74.240 18.400 74.740 ;
        RECT 23.260 74.240 23.500 74.740 ;
        RECT 18.160 75.540 18.400 76.040 ;
        RECT 14.760 76.840 15.000 77.340 ;
        RECT 14.760 72.940 15.000 73.440 ;
        RECT 21.560 72.940 21.800 73.440 ;
        RECT 24.960 72.940 25.200 73.440 ;
        RECT 26.660 72.940 26.900 73.440 ;
        RECT 9.660 74.240 9.900 74.740 ;
        RECT 1.160 91.140 1.400 91.640 ;
        RECT 4.560 91.140 4.800 91.640 ;
        RECT 7.960 91.140 8.200 91.640 ;
        RECT 7.960 84.640 8.200 85.140 ;
        RECT 11.360 79.440 11.600 79.940 ;
        RECT 1.200 95.160 1.400 95.660 ;
        RECT 2.900 95.160 3.100 95.660 ;
        RECT 4.600 95.160 4.800 95.660 ;
        RECT 6.300 95.160 6.500 95.660 ;
        RECT 8.000 95.160 8.200 95.660 ;
        RECT 9.700 95.160 9.900 95.660 ;
        RECT 11.400 95.160 11.600 95.660 ;
        RECT 13.100 95.160 13.300 95.660 ;
        RECT 7.960 85.940 8.200 86.440 ;
        RECT 13.060 85.940 13.300 86.440 ;
        RECT 1.160 76.840 1.400 77.340 ;
        RECT 9.660 76.840 9.900 77.340 ;
        RECT 4.560 87.240 4.800 87.740 ;
        RECT 4.560 82.040 4.800 82.540 ;
        RECT 6.260 82.040 6.500 82.540 ;
        RECT 6.260 78.140 6.500 78.640 ;
        RECT 13.060 78.140 13.300 78.640 ;
        RECT 2.860 88.540 3.100 89.040 ;
        RECT 7.960 88.540 8.200 89.040 ;
        RECT 9.660 88.540 9.900 89.040 ;
        RECT 2.860 72.940 3.100 73.440 ;
        RECT 4.560 72.940 4.800 73.440 ;
        RECT 13.060 76.840 13.300 77.340 ;
        RECT 1.160 83.340 1.400 83.840 ;
        RECT 13.060 83.340 13.300 83.840 ;
        RECT 1.160 75.540 1.400 76.040 ;
        RECT 6.260 59.940 6.500 60.440 ;
        RECT 9.660 53.440 9.900 53.940 ;
        RECT 9.660 63.840 9.900 64.340 ;
        RECT 13.060 49.540 13.300 50.040 ;
        RECT 13.060 52.140 13.300 52.640 ;
        RECT 11.360 53.440 11.600 53.940 ;
        RECT 1.160 62.540 1.400 63.040 ;
        RECT 7.960 62.540 8.200 63.040 ;
        RECT 2.860 48.240 3.100 48.740 ;
        RECT 6.260 48.240 6.500 48.740 ;
        RECT 6.260 58.640 6.500 59.140 ;
        RECT 7.960 58.640 8.200 59.140 ;
        RECT 4.560 53.440 4.800 53.940 ;
        RECT 2.860 61.240 3.100 61.740 ;
        RECT 4.560 61.240 4.800 61.740 ;
        RECT 9.660 48.240 9.900 48.740 ;
        RECT 11.360 49.540 11.600 50.040 ;
        RECT 4.560 56.040 4.800 56.540 ;
        RECT 6.260 67.740 6.500 68.240 ;
        RECT 9.660 67.740 9.900 68.240 ;
        RECT 6.260 56.040 6.500 56.540 ;
        RECT 9.660 54.740 9.900 55.240 ;
        RECT 9.660 59.940 9.900 60.440 ;
        RECT 11.360 59.940 11.600 60.440 ;
        RECT 13.060 59.940 13.300 60.440 ;
        RECT 2.860 59.940 3.100 60.440 ;
        RECT 4.560 70.340 4.800 70.840 ;
        RECT 2.860 63.840 3.100 64.340 ;
        RECT 9.660 66.440 9.900 66.940 ;
        RECT 11.360 61.240 11.600 61.740 ;
        RECT 13.060 61.240 13.300 61.740 ;
        RECT 24.960 56.040 25.200 56.540 ;
        RECT 21.560 70.340 21.800 70.840 ;
        RECT 18.160 49.540 18.400 50.040 ;
        RECT 24.960 54.740 25.200 55.240 ;
        RECT 26.660 54.740 26.900 55.240 ;
        RECT 14.760 65.140 15.000 65.640 ;
        RECT 24.960 61.240 25.200 61.740 ;
        RECT 14.760 62.540 15.000 63.040 ;
        RECT 26.660 61.240 26.900 61.740 ;
        RECT 16.460 53.440 16.700 53.940 ;
        RECT 16.460 65.140 16.700 65.640 ;
        RECT 14.760 58.640 15.000 59.140 ;
        RECT 18.160 65.140 18.400 65.640 ;
        RECT 26.660 48.240 26.900 48.740 ;
        RECT 26.660 53.440 26.900 53.940 ;
        RECT 16.460 61.240 16.700 61.740 ;
        RECT 24.960 63.840 25.200 64.340 ;
        RECT 16.460 56.040 16.700 56.540 ;
        RECT 14.760 54.740 15.000 55.240 ;
        RECT 19.860 54.740 20.100 55.240 ;
        RECT 18.160 67.740 18.400 68.240 ;
        RECT 18.160 58.640 18.400 59.140 ;
        RECT 19.860 58.640 20.100 59.140 ;
        RECT 14.760 52.140 15.000 52.640 ;
        RECT 19.860 56.040 20.100 56.540 ;
        RECT 23.260 54.740 23.500 55.240 ;
        RECT 26.660 52.140 26.900 52.640 ;
        RECT 18.160 59.940 18.400 60.440 ;
        RECT 19.860 59.940 20.100 60.440 ;
        RECT 26.660 59.940 26.900 60.440 ;
        RECT 16.460 49.540 16.700 50.040 ;
        RECT 14.760 66.440 15.000 66.940 ;
        RECT 19.860 49.540 20.100 50.040 ;
        RECT 23.260 62.540 23.500 63.040 ;
        RECT 24.960 62.540 25.200 63.040 ;
        RECT 26.660 62.540 26.900 63.040 ;
        RECT 2.860 23.540 3.100 24.040 ;
        RECT 4.560 23.540 4.800 24.040 ;
        RECT 11.360 23.540 11.600 24.040 ;
        RECT 16.460 23.540 16.700 24.040 ;
        RECT 21.560 23.540 21.800 24.040 ;
        RECT 24.960 23.540 25.200 24.040 ;
        RECT 26.660 23.540 26.900 24.040 ;
        RECT 18.160 24.840 18.400 25.340 ;
        RECT 24.960 24.840 25.200 25.340 ;
        RECT 26.660 24.840 26.900 25.340 ;
        RECT 21.560 26.140 21.800 26.640 ;
        RECT 23.260 26.140 23.500 26.640 ;
        RECT 21.560 27.440 21.800 27.940 ;
        RECT 24.960 28.740 25.200 29.240 ;
        RECT 16.460 30.040 16.700 30.540 ;
        RECT 19.860 30.040 20.100 30.540 ;
        RECT 24.960 31.340 25.200 31.840 ;
        RECT 14.760 32.640 15.000 33.140 ;
        RECT 21.560 32.640 21.800 33.140 ;
        RECT 18.160 35.240 18.400 35.740 ;
        RECT 21.560 35.240 21.800 35.740 ;
        RECT 26.660 35.240 26.900 35.740 ;
        RECT 21.560 36.540 21.800 37.040 ;
        RECT 23.260 36.540 23.500 37.040 ;
        RECT 14.760 37.840 15.000 38.340 ;
        RECT 18.160 37.840 18.400 38.340 ;
        RECT 18.160 39.140 18.400 39.640 ;
        RECT 19.860 39.140 20.100 39.640 ;
        RECT 23.260 39.140 23.500 39.640 ;
        RECT 14.760 40.440 15.000 40.940 ;
        RECT 18.160 40.440 18.400 40.940 ;
        RECT 21.560 40.440 21.800 40.940 ;
        RECT 19.860 41.740 20.100 42.240 ;
        RECT 24.960 41.740 25.200 42.240 ;
        RECT 26.660 41.740 26.900 42.240 ;
        RECT 19.860 43.040 20.100 43.540 ;
        RECT 21.560 43.040 21.800 43.540 ;
        RECT 16.460 44.340 16.700 44.840 ;
        RECT 19.860 44.340 20.100 44.840 ;
        RECT 21.560 44.340 21.800 44.840 ;
        RECT 1.160 37.840 1.400 38.340 ;
        RECT 4.560 37.840 4.800 38.340 ;
        RECT 13.060 37.840 13.300 38.340 ;
        RECT 2.860 24.840 3.100 25.340 ;
        RECT 1.160 26.140 1.400 26.640 ;
        RECT 7.960 39.140 8.200 39.640 ;
        RECT 11.360 31.340 11.600 31.840 ;
        RECT 1.160 27.440 1.400 27.940 ;
        RECT 6.260 32.640 6.500 33.140 ;
        RECT 4.560 40.440 4.800 40.940 ;
        RECT 9.660 40.440 9.900 40.940 ;
        RECT 4.560 27.440 4.800 27.940 ;
        RECT 6.260 27.440 6.500 27.940 ;
        RECT 1.160 35.240 1.400 35.740 ;
        RECT 1.160 41.740 1.400 42.240 ;
        RECT 9.660 41.740 9.900 42.240 ;
        RECT 6.260 35.240 6.500 35.740 ;
        RECT 7.960 35.240 8.200 35.740 ;
        RECT 11.360 35.240 11.600 35.740 ;
        RECT 4.560 43.040 4.800 43.540 ;
        RECT 7.960 43.040 8.200 43.540 ;
        RECT 13.060 43.040 13.300 43.540 ;
        RECT 7.960 26.140 8.200 26.640 ;
        RECT 6.260 28.740 6.500 29.240 ;
        RECT 2.860 44.340 3.100 44.840 ;
        RECT 4.560 44.340 4.800 44.840 ;
        RECT 9.660 44.340 9.900 44.840 ;
        RECT 13.060 28.740 13.300 29.240 ;
        RECT 11.360 26.140 11.600 26.640 ;
        RECT 4.560 30.040 4.800 30.540 ;
        RECT 7.960 46.940 8.200 47.440 ;
        RECT 9.660 46.940 9.900 47.440 ;
        RECT 11.360 19.640 11.600 20.140 ;
        RECT 2.860 20.940 3.100 21.440 ;
        RECT 6.260 20.940 6.500 21.440 ;
        RECT 2.860 0.140 3.100 0.640 ;
        RECT 4.560 0.140 4.800 0.640 ;
        RECT 1.160 1.440 1.400 1.940 ;
        RECT 4.560 1.440 4.800 1.940 ;
        RECT 4.560 2.740 4.800 3.240 ;
        RECT 9.660 2.740 9.900 3.240 ;
        RECT 9.660 4.040 9.900 4.540 ;
        RECT 7.960 5.340 8.200 5.840 ;
        RECT 1.160 6.640 1.400 7.140 ;
        RECT 6.260 6.640 6.500 7.140 ;
        RECT 7.960 6.640 8.200 7.140 ;
        RECT 6.260 7.940 6.500 8.440 ;
        RECT 9.660 7.940 9.900 8.440 ;
        RECT 1.160 13.140 1.400 13.640 ;
        RECT 4.560 13.140 4.800 13.640 ;
        RECT 13.060 13.140 13.300 13.640 ;
        RECT 6.260 14.440 6.500 14.940 ;
        RECT 13.060 15.740 13.300 16.240 ;
        RECT 7.960 17.040 8.200 17.540 ;
        RECT 11.360 17.040 11.600 17.540 ;
        RECT 9.660 18.340 9.900 18.840 ;
        RECT 24.960 4.040 25.200 4.540 ;
        RECT 26.660 4.040 26.900 4.540 ;
        RECT 26.660 20.940 26.900 21.440 ;
        RECT 26.660 5.340 26.900 5.840 ;
        RECT 19.860 19.640 20.100 20.140 ;
        RECT 26.660 19.640 26.900 20.140 ;
        RECT 18.160 0.140 18.400 0.640 ;
        RECT 18.160 6.640 18.400 7.140 ;
        RECT 21.560 6.640 21.800 7.140 ;
        RECT 16.460 19.640 16.700 20.140 ;
        RECT 18.160 19.640 18.400 20.140 ;
        RECT 21.560 7.940 21.800 8.440 ;
        RECT 21.560 9.240 21.800 9.740 ;
        RECT 23.260 9.240 23.500 9.740 ;
        RECT 14.760 11.840 15.000 12.340 ;
        RECT 21.560 1.440 21.800 1.940 ;
        RECT 18.160 20.940 18.400 21.440 ;
        RECT 19.860 20.940 20.100 21.440 ;
        RECT 14.760 13.140 15.000 13.640 ;
        RECT 26.660 13.140 26.900 13.640 ;
        RECT 16.460 2.740 16.700 3.240 ;
        RECT 18.160 14.440 18.400 14.940 ;
        RECT 18.160 2.740 18.400 3.240 ;
        RECT 23.260 15.740 23.500 16.240 ;
        RECT 26.660 2.740 26.900 3.240 ;
        RECT 24.960 20.940 25.200 21.440 ;
        RECT 18.160 4.040 18.400 4.540 ;
        RECT 19.860 18.340 20.100 18.840 ;
        RECT 35.160 23.540 35.400 24.040 ;
        RECT 40.260 23.540 40.500 24.040 ;
        RECT 47.060 23.540 47.300 24.040 ;
        RECT 45.360 37.840 45.600 38.340 ;
        RECT 52.160 37.840 52.400 38.340 ;
        RECT 53.860 37.840 54.100 38.340 ;
        RECT 41.960 39.140 42.200 39.640 ;
        RECT 50.460 39.140 50.700 39.640 ;
        RECT 47.060 40.440 47.300 40.940 ;
        RECT 50.460 40.440 50.700 40.940 ;
        RECT 52.160 40.440 52.400 40.940 ;
        RECT 53.860 40.440 54.100 40.940 ;
        RECT 48.760 41.740 49.000 42.240 ;
        RECT 50.460 41.740 50.700 42.240 ;
        RECT 53.860 35.240 54.100 35.740 ;
        RECT 45.360 43.040 45.600 43.540 ;
        RECT 53.860 43.040 54.100 43.540 ;
        RECT 53.860 36.540 54.100 37.040 ;
        RECT 41.960 37.840 42.200 38.340 ;
        RECT 52.160 44.340 52.400 44.840 ;
        RECT 43.660 24.840 43.900 25.340 ;
        RECT 48.760 46.940 49.000 47.440 ;
        RECT 50.460 46.940 50.700 47.440 ;
        RECT 48.760 24.840 49.000 25.340 ;
        RECT 50.460 24.840 50.700 25.340 ;
        RECT 47.060 26.140 47.300 26.640 ;
        RECT 52.160 26.140 52.400 26.640 ;
        RECT 45.360 27.440 45.600 27.940 ;
        RECT 47.060 27.440 47.300 27.940 ;
        RECT 48.760 27.440 49.000 27.940 ;
        RECT 41.960 28.740 42.200 29.240 ;
        RECT 48.760 28.740 49.000 29.240 ;
        RECT 43.660 30.040 43.900 30.540 ;
        RECT 52.160 30.040 52.400 30.540 ;
        RECT 52.160 31.340 52.400 31.840 ;
        RECT 41.960 32.640 42.200 33.140 ;
        RECT 45.360 32.640 45.600 33.140 ;
        RECT 28.360 40.440 28.600 40.940 ;
        RECT 30.060 40.440 30.300 40.940 ;
        RECT 35.160 40.440 35.400 40.940 ;
        RECT 31.760 43.040 32.000 43.540 ;
        RECT 30.060 26.140 30.300 26.640 ;
        RECT 35.160 26.140 35.400 26.640 ;
        RECT 33.460 43.040 33.700 43.540 ;
        RECT 35.160 43.040 35.400 43.540 ;
        RECT 40.260 27.440 40.500 27.940 ;
        RECT 36.860 40.440 37.100 40.940 ;
        RECT 38.560 40.440 38.800 40.940 ;
        RECT 40.260 36.540 40.500 37.040 ;
        RECT 33.460 28.740 33.700 29.240 ;
        RECT 36.860 39.140 37.100 39.640 ;
        RECT 38.560 44.340 38.800 44.840 ;
        RECT 28.360 30.040 28.600 30.540 ;
        RECT 36.860 30.040 37.100 30.540 ;
        RECT 40.260 30.040 40.500 30.540 ;
        RECT 40.260 44.340 40.500 44.840 ;
        RECT 28.360 37.840 28.600 38.340 ;
        RECT 40.260 31.340 40.500 31.840 ;
        RECT 36.860 24.840 37.100 25.340 ;
        RECT 38.560 32.640 38.800 33.140 ;
        RECT 38.560 37.840 38.800 38.340 ;
        RECT 35.160 46.940 35.400 47.440 ;
        RECT 40.260 35.240 40.500 35.740 ;
        RECT 38.560 20.940 38.800 21.440 ;
        RECT 31.760 9.240 32.000 9.740 ;
        RECT 30.060 6.640 30.300 7.140 ;
        RECT 28.360 19.640 28.600 20.140 ;
        RECT 33.460 5.340 33.700 5.840 ;
        RECT 36.860 11.840 37.100 12.340 ;
        RECT 30.060 17.040 30.300 17.540 ;
        RECT 36.860 17.040 37.100 17.540 ;
        RECT 35.160 19.640 35.400 20.140 ;
        RECT 38.560 13.140 38.800 13.640 ;
        RECT 36.860 2.740 37.100 3.240 ;
        RECT 36.860 13.140 37.100 13.640 ;
        RECT 28.360 9.240 28.600 9.740 ;
        RECT 38.560 17.040 38.800 17.540 ;
        RECT 38.560 5.340 38.800 5.840 ;
        RECT 28.360 15.740 28.600 16.240 ;
        RECT 35.160 15.740 35.400 16.240 ;
        RECT 40.260 15.740 40.500 16.240 ;
        RECT 33.460 20.940 33.700 21.440 ;
        RECT 35.160 1.440 35.400 1.940 ;
        RECT 30.060 18.340 30.300 18.840 ;
        RECT 35.160 4.040 35.400 4.540 ;
        RECT 33.460 7.940 33.700 8.440 ;
        RECT 36.860 7.940 37.100 8.440 ;
        RECT 36.860 20.940 37.100 21.440 ;
        RECT 53.860 15.740 54.100 16.240 ;
        RECT 48.760 1.440 49.000 1.940 ;
        RECT 47.060 19.640 47.300 20.140 ;
        RECT 45.360 20.940 45.600 21.440 ;
        RECT 48.760 20.940 49.000 21.440 ;
        RECT 47.060 6.640 47.300 7.140 ;
        RECT 52.160 20.940 52.400 21.440 ;
        RECT 53.860 20.940 54.100 21.440 ;
        RECT 45.360 2.740 45.600 3.240 ;
        RECT 53.860 1.440 54.100 1.940 ;
        RECT 41.960 14.440 42.200 14.940 ;
        RECT 53.860 0.140 54.100 0.640 ;
        RECT 43.660 9.240 43.900 9.740 ;
        RECT 52.160 19.640 52.400 20.140 ;
        RECT 41.960 17.040 42.200 17.540 ;
        RECT 48.760 5.340 49.000 5.840 ;
        RECT 53.860 5.340 54.100 5.840 ;
        RECT 45.360 17.040 45.600 17.540 ;
        RECT 47.060 17.040 47.300 17.540 ;
        RECT 53.860 6.640 54.100 7.140 ;
        RECT 45.360 0.140 45.600 0.640 ;
        RECT 50.460 7.940 50.700 8.440 ;
        RECT 52.160 7.940 52.400 8.440 ;
        RECT 47.060 7.940 47.300 8.440 ;
        RECT 47.060 11.840 47.300 12.340 ;
        RECT 41.960 18.340 42.200 18.840 ;
        RECT 48.760 11.840 49.000 12.340 ;
        RECT 53.860 4.040 54.100 4.540 ;
        RECT 45.360 1.440 45.600 1.940 ;
        RECT 45.360 5.340 45.600 5.840 ;
        RECT 43.660 15.740 43.900 16.240 ;
  END
END macro_array_pc_64x32_test0
END LIBRARY

